VERSION 5.8 ;
BUSBITCHARS "[]" ;
DIVIDERCHAR "/" ;
UNITS
  DATABASE MICRONS 1000 ;
END UNITS
LAYER metal1
  TYPE ROUTING ;
  DIRECTION HORIZONTAL ;
  PITCH 0.1 ;
  WIDTH 0.1 ;
END metal1
MANUFACTURINGGRID 0.001 ;
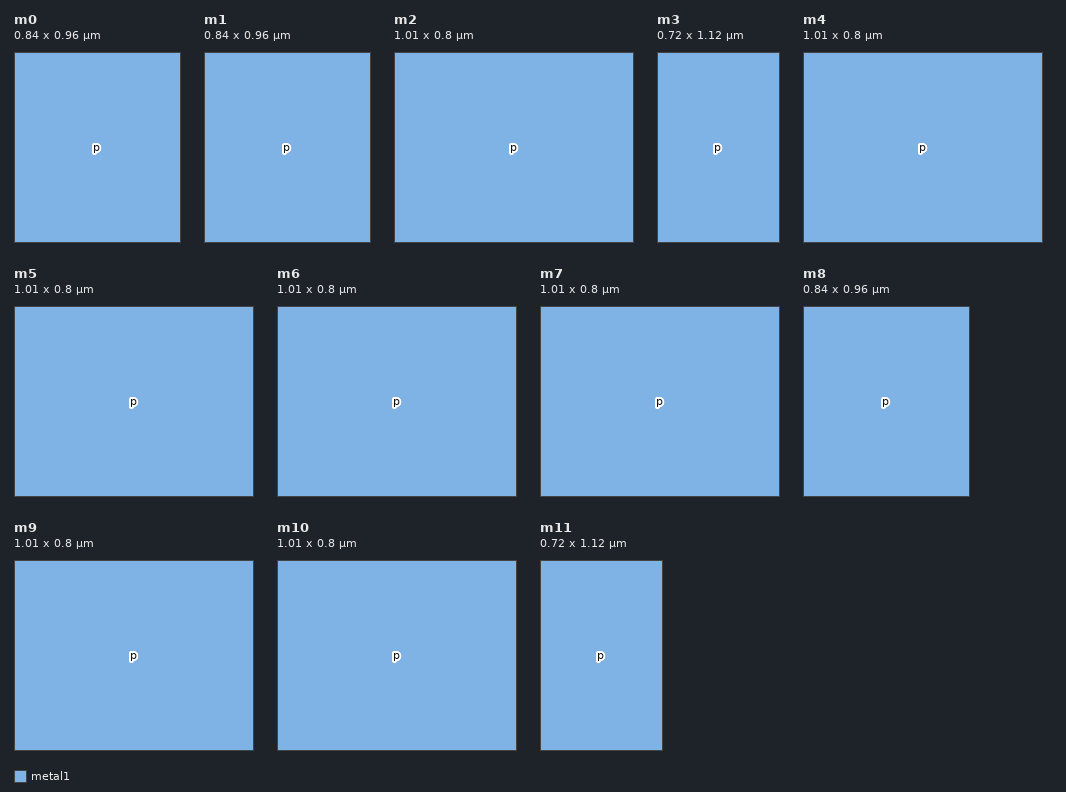
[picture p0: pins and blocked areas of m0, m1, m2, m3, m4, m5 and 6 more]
MACRO m0
  SIZE 0.840 BY 0.960 ;
  PIN p
    DIRECTION INOUT ;
    USE SIGNAL ;
    PORT
      LAYER metal1 ;
      RECT 0 0 0.840 0.960 ;
    END
  END p
END m0
MACRO m1
  SIZE 0.840 BY 0.960 ;
  PIN p
    DIRECTION INOUT ;
    USE SIGNAL ;
    PORT
      LAYER metal1 ;
      RECT 0 0 0.840 0.960 ;
    END
  END p
END m1
MACRO m2
  SIZE 1.010 BY 0.800 ;
  PIN p
    DIRECTION INOUT ;
    USE SIGNAL ;
    PORT
      LAYER metal1 ;
      RECT 0 0 1.010 0.800 ;
    END
  END p
END m2
MACRO m3
  SIZE 0.720 BY 1.120 ;
  PIN p
    DIRECTION INOUT ;
    USE SIGNAL ;
    PORT
      LAYER metal1 ;
      RECT 0 0 0.720 1.120 ;
    END
  END p
END m3
MACRO m4
  SIZE 1.010 BY 0.800 ;
  PIN p
    DIRECTION INOUT ;
    USE SIGNAL ;
    PORT
      LAYER metal1 ;
      RECT 0 0 1.010 0.800 ;
    END
  END p
END m4
MACRO m5
  SIZE 1.010 BY 0.800 ;
  PIN p
    DIRECTION INOUT ;
    USE SIGNAL ;
    PORT
      LAYER metal1 ;
      RECT 0 0 1.010 0.800 ;
    END
  END p
END m5
MACRO m6
  SIZE 1.010 BY 0.800 ;
  PIN p
    DIRECTION INOUT ;
    USE SIGNAL ;
    PORT
      LAYER metal1 ;
      RECT 0 0 1.010 0.800 ;
    END
  END p
END m6
MACRO m7
  SIZE 1.010 BY 0.800 ;
  PIN p
    DIRECTION INOUT ;
    USE SIGNAL ;
    PORT
      LAYER metal1 ;
      RECT 0 0 1.010 0.800 ;
    END
  END p
END m7
MACRO m8
  SIZE 0.840 BY 0.960 ;
  PIN p
    DIRECTION INOUT ;
    USE SIGNAL ;
    PORT
      LAYER metal1 ;
      RECT 0 0 0.840 0.960 ;
    END
  END p
END m8
MACRO m9
  SIZE 1.010 BY 0.800 ;
  PIN p
    DIRECTION INOUT ;
    USE SIGNAL ;
    PORT
      LAYER metal1 ;
      RECT 0 0 1.010 0.800 ;
    END
  END p
END m9
MACRO m10
  SIZE 1.010 BY 0.800 ;
  PIN p
    DIRECTION INOUT ;
    USE SIGNAL ;
    PORT
      LAYER metal1 ;
      RECT 0 0 1.010 0.800 ;
    END
  END p
END m10
MACRO m11
  SIZE 0.720 BY 1.120 ;
  PIN p
    DIRECTION INOUT ;
    USE SIGNAL ;
    PORT
      LAYER metal1 ;
      RECT 0 0 0.720 1.120 ;
    END
  END p
END m11
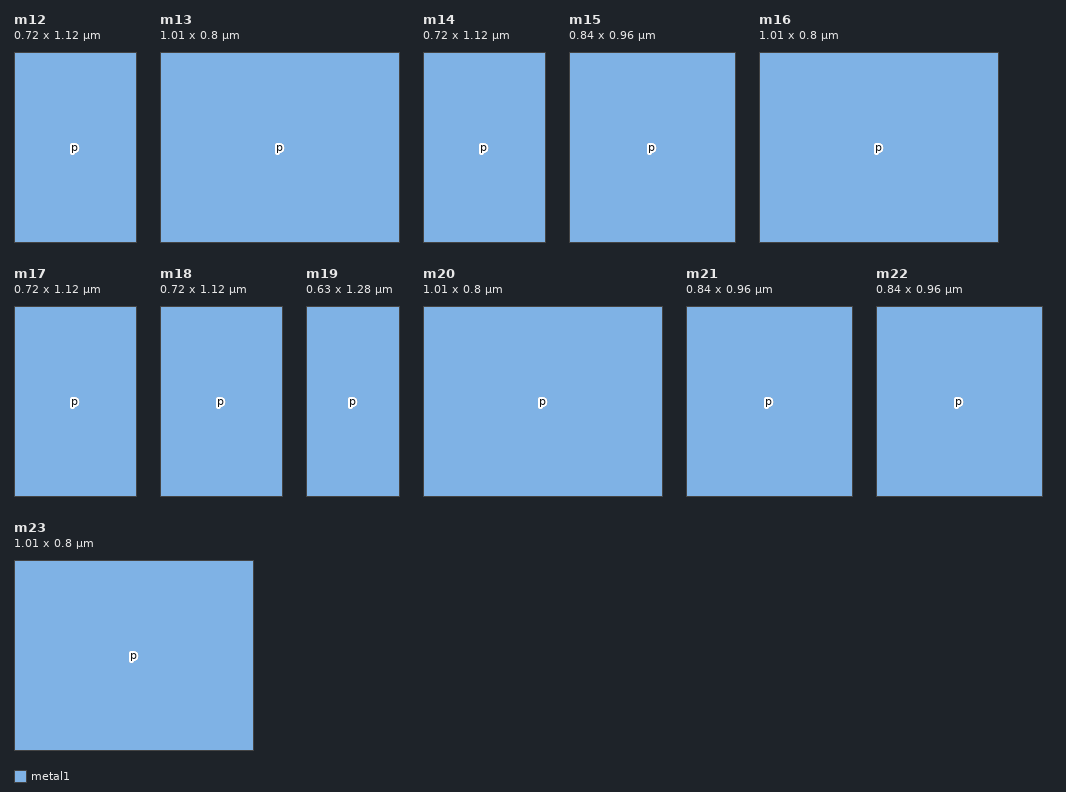
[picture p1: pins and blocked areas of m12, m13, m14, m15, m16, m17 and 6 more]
MACRO m12
  SIZE 0.720 BY 1.120 ;
  PIN p
    DIRECTION INOUT ;
    USE SIGNAL ;
    PORT
      LAYER metal1 ;
      RECT 0 0 0.720 1.120 ;
    END
  END p
END m12
MACRO m13
  SIZE 1.010 BY 0.800 ;
  PIN p
    DIRECTION INOUT ;
    USE SIGNAL ;
    PORT
      LAYER metal1 ;
      RECT 0 0 1.010 0.800 ;
    END
  END p
END m13
MACRO m14
  SIZE 0.720 BY 1.120 ;
  PIN p
    DIRECTION INOUT ;
    USE SIGNAL ;
    PORT
      LAYER metal1 ;
      RECT 0 0 0.720 1.120 ;
    END
  END p
END m14
MACRO m15
  SIZE 0.840 BY 0.960 ;
  PIN p
    DIRECTION INOUT ;
    USE SIGNAL ;
    PORT
      LAYER metal1 ;
      RECT 0 0 0.840 0.960 ;
    END
  END p
END m15
MACRO m16
  SIZE 1.010 BY 0.800 ;
  PIN p
    DIRECTION INOUT ;
    USE SIGNAL ;
    PORT
      LAYER metal1 ;
      RECT 0 0 1.010 0.800 ;
    END
  END p
END m16
MACRO m17
  SIZE 0.720 BY 1.120 ;
  PIN p
    DIRECTION INOUT ;
    USE SIGNAL ;
    PORT
      LAYER metal1 ;
      RECT 0 0 0.720 1.120 ;
    END
  END p
END m17
MACRO m18
  SIZE 0.720 BY 1.120 ;
  PIN p
    DIRECTION INOUT ;
    USE SIGNAL ;
    PORT
      LAYER metal1 ;
      RECT 0 0 0.720 1.120 ;
    END
  END p
END m18
MACRO m19
  SIZE 0.630 BY 1.280 ;
  PIN p
    DIRECTION INOUT ;
    USE SIGNAL ;
    PORT
      LAYER metal1 ;
      RECT 0 0 0.630 1.280 ;
    END
  END p
END m19
MACRO m20
  SIZE 1.010 BY 0.800 ;
  PIN p
    DIRECTION INOUT ;
    USE SIGNAL ;
    PORT
      LAYER metal1 ;
      RECT 0 0 1.010 0.800 ;
    END
  END p
END m20
MACRO m21
  SIZE 0.840 BY 0.960 ;
  PIN p
    DIRECTION INOUT ;
    USE SIGNAL ;
    PORT
      LAYER metal1 ;
      RECT 0 0 0.840 0.960 ;
    END
  END p
END m21
MACRO m22
  SIZE 0.840 BY 0.960 ;
  PIN p
    DIRECTION INOUT ;
    USE SIGNAL ;
    PORT
      LAYER metal1 ;
      RECT 0 0 0.840 0.960 ;
    END
  END p
END m22
MACRO m23
  SIZE 1.010 BY 0.800 ;
  PIN p
    DIRECTION INOUT ;
    USE SIGNAL ;
    PORT
      LAYER metal1 ;
      RECT 0 0 1.010 0.800 ;
    END
  END p
END m23
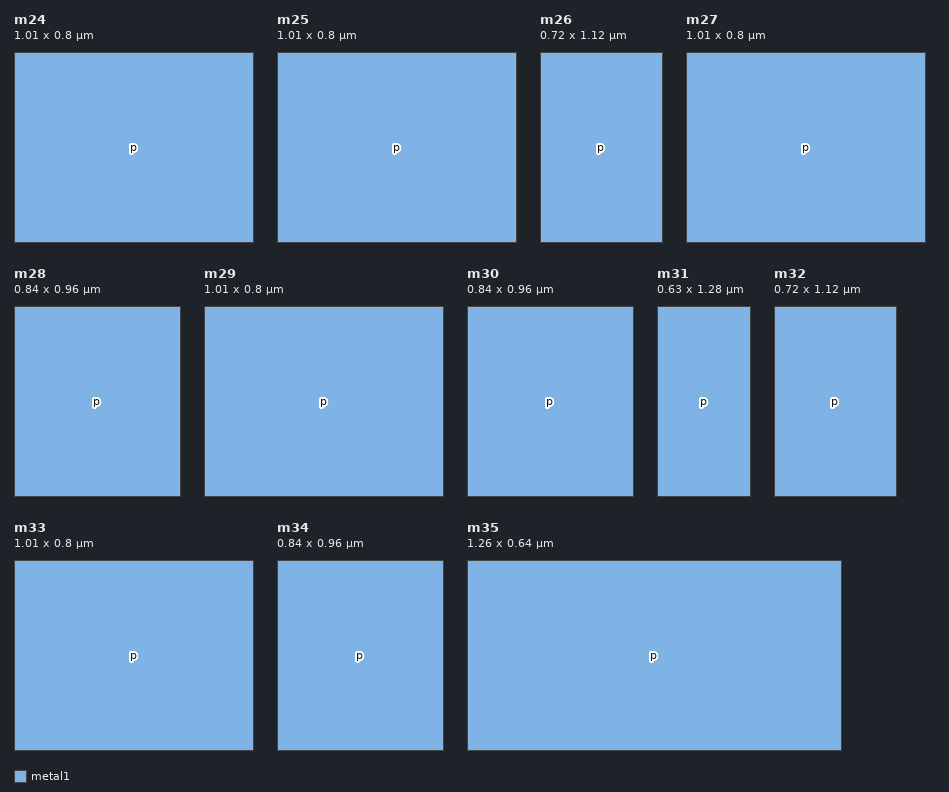
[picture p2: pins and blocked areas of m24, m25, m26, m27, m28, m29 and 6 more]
MACRO m24
  SIZE 1.010 BY 0.800 ;
  PIN p
    DIRECTION INOUT ;
    USE SIGNAL ;
    PORT
      LAYER metal1 ;
      RECT 0 0 1.010 0.800 ;
    END
  END p
END m24
MACRO m25
  SIZE 1.010 BY 0.800 ;
  PIN p
    DIRECTION INOUT ;
    USE SIGNAL ;
    PORT
      LAYER metal1 ;
      RECT 0 0 1.010 0.800 ;
    END
  END p
END m25
MACRO m26
  SIZE 0.720 BY 1.120 ;
  PIN p
    DIRECTION INOUT ;
    USE SIGNAL ;
    PORT
      LAYER metal1 ;
      RECT 0 0 0.720 1.120 ;
    END
  END p
END m26
MACRO m27
  SIZE 1.010 BY 0.800 ;
  PIN p
    DIRECTION INOUT ;
    USE SIGNAL ;
    PORT
      LAYER metal1 ;
      RECT 0 0 1.010 0.800 ;
    END
  END p
END m27
MACRO m28
  SIZE 0.840 BY 0.960 ;
  PIN p
    DIRECTION INOUT ;
    USE SIGNAL ;
    PORT
      LAYER metal1 ;
      RECT 0 0 0.840 0.960 ;
    END
  END p
END m28
MACRO m29
  SIZE 1.010 BY 0.800 ;
  PIN p
    DIRECTION INOUT ;
    USE SIGNAL ;
    PORT
      LAYER metal1 ;
      RECT 0 0 1.010 0.800 ;
    END
  END p
END m29
MACRO m30
  SIZE 0.840 BY 0.960 ;
  PIN p
    DIRECTION INOUT ;
    USE SIGNAL ;
    PORT
      LAYER metal1 ;
      RECT 0 0 0.840 0.960 ;
    END
  END p
END m30
MACRO m31
  SIZE 0.630 BY 1.280 ;
  PIN p
    DIRECTION INOUT ;
    USE SIGNAL ;
    PORT
      LAYER metal1 ;
      RECT 0 0 0.630 1.280 ;
    END
  END p
END m31
MACRO m32
  SIZE 0.720 BY 1.120 ;
  PIN p
    DIRECTION INOUT ;
    USE SIGNAL ;
    PORT
      LAYER metal1 ;
      RECT 0 0 0.720 1.120 ;
    END
  END p
END m32
MACRO m33
  SIZE 1.010 BY 0.800 ;
  PIN p
    DIRECTION INOUT ;
    USE SIGNAL ;
    PORT
      LAYER metal1 ;
      RECT 0 0 1.010 0.800 ;
    END
  END p
END m33
MACRO m34
  SIZE 0.840 BY 0.960 ;
  PIN p
    DIRECTION INOUT ;
    USE SIGNAL ;
    PORT
      LAYER metal1 ;
      RECT 0 0 0.840 0.960 ;
    END
  END p
END m34
MACRO m35
  SIZE 1.260 BY 0.640 ;
  PIN p
    DIRECTION INOUT ;
    USE SIGNAL ;
    PORT
      LAYER metal1 ;
      RECT 0 0 1.260 0.640 ;
    END
  END p
END m35
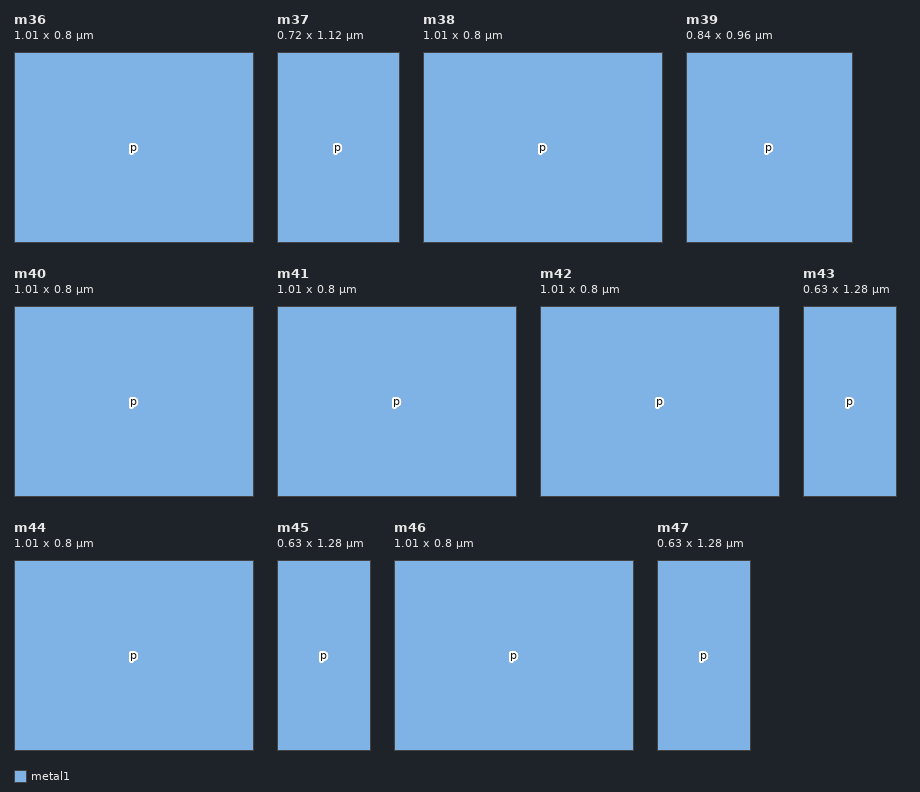
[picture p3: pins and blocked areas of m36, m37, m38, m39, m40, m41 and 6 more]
MACRO m36
  SIZE 1.010 BY 0.800 ;
  PIN p
    DIRECTION INOUT ;
    USE SIGNAL ;
    PORT
      LAYER metal1 ;
      RECT 0 0 1.010 0.800 ;
    END
  END p
END m36
MACRO m37
  SIZE 0.720 BY 1.120 ;
  PIN p
    DIRECTION INOUT ;
    USE SIGNAL ;
    PORT
      LAYER metal1 ;
      RECT 0 0 0.720 1.120 ;
    END
  END p
END m37
MACRO m38
  SIZE 1.010 BY 0.800 ;
  PIN p
    DIRECTION INOUT ;
    USE SIGNAL ;
    PORT
      LAYER metal1 ;
      RECT 0 0 1.010 0.800 ;
    END
  END p
END m38
MACRO m39
  SIZE 0.840 BY 0.960 ;
  PIN p
    DIRECTION INOUT ;
    USE SIGNAL ;
    PORT
      LAYER metal1 ;
      RECT 0 0 0.840 0.960 ;
    END
  END p
END m39
MACRO m40
  SIZE 1.010 BY 0.800 ;
  PIN p
    DIRECTION INOUT ;
    USE SIGNAL ;
    PORT
      LAYER metal1 ;
      RECT 0 0 1.010 0.800 ;
    END
  END p
END m40
MACRO m41
  SIZE 1.010 BY 0.800 ;
  PIN p
    DIRECTION INOUT ;
    USE SIGNAL ;
    PORT
      LAYER metal1 ;
      RECT 0 0 1.010 0.800 ;
    END
  END p
END m41
MACRO m42
  SIZE 1.010 BY 0.800 ;
  PIN p
    DIRECTION INOUT ;
    USE SIGNAL ;
    PORT
      LAYER metal1 ;
      RECT 0 0 1.010 0.800 ;
    END
  END p
END m42
MACRO m43
  SIZE 0.630 BY 1.280 ;
  PIN p
    DIRECTION INOUT ;
    USE SIGNAL ;
    PORT
      LAYER metal1 ;
      RECT 0 0 0.630 1.280 ;
    END
  END p
END m43
MACRO m44
  SIZE 1.010 BY 0.800 ;
  PIN p
    DIRECTION INOUT ;
    USE SIGNAL ;
    PORT
      LAYER metal1 ;
      RECT 0 0 1.010 0.800 ;
    END
  END p
END m44
MACRO m45
  SIZE 0.630 BY 1.280 ;
  PIN p
    DIRECTION INOUT ;
    USE SIGNAL ;
    PORT
      LAYER metal1 ;
      RECT 0 0 0.630 1.280 ;
    END
  END p
END m45
MACRO m46
  SIZE 1.010 BY 0.800 ;
  PIN p
    DIRECTION INOUT ;
    USE SIGNAL ;
    PORT
      LAYER metal1 ;
      RECT 0 0 1.010 0.800 ;
    END
  END p
END m46
MACRO m47
  SIZE 0.630 BY 1.280 ;
  PIN p
    DIRECTION INOUT ;
    USE SIGNAL ;
    PORT
      LAYER metal1 ;
      RECT 0 0 0.630 1.280 ;
    END
  END p
END m47
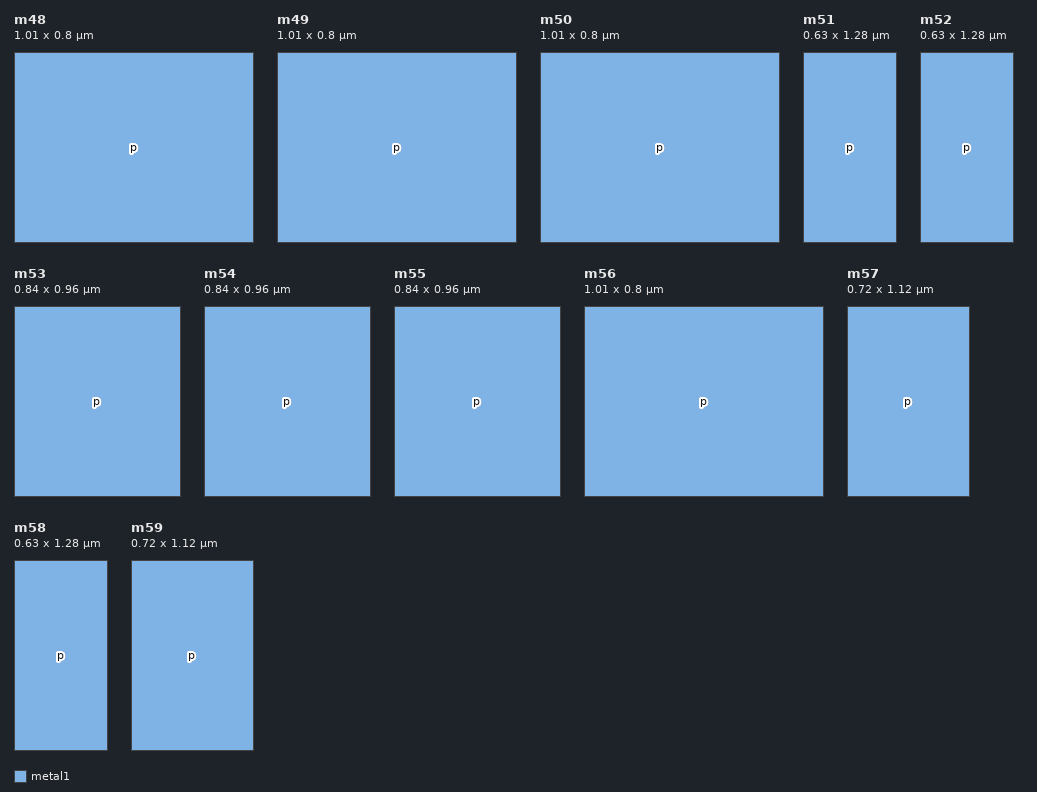
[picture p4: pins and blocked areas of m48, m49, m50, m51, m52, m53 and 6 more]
MACRO m48
  SIZE 1.010 BY 0.800 ;
  PIN p
    DIRECTION INOUT ;
    USE SIGNAL ;
    PORT
      LAYER metal1 ;
      RECT 0 0 1.010 0.800 ;
    END
  END p
END m48
MACRO m49
  SIZE 1.010 BY 0.800 ;
  PIN p
    DIRECTION INOUT ;
    USE SIGNAL ;
    PORT
      LAYER metal1 ;
      RECT 0 0 1.010 0.800 ;
    END
  END p
END m49
MACRO m50
  SIZE 1.010 BY 0.800 ;
  PIN p
    DIRECTION INOUT ;
    USE SIGNAL ;
    PORT
      LAYER metal1 ;
      RECT 0 0 1.010 0.800 ;
    END
  END p
END m50
MACRO m51
  SIZE 0.630 BY 1.280 ;
  PIN p
    DIRECTION INOUT ;
    USE SIGNAL ;
    PORT
      LAYER metal1 ;
      RECT 0 0 0.630 1.280 ;
    END
  END p
END m51
MACRO m52
  SIZE 0.630 BY 1.280 ;
  PIN p
    DIRECTION INOUT ;
    USE SIGNAL ;
    PORT
      LAYER metal1 ;
      RECT 0 0 0.630 1.280 ;
    END
  END p
END m52
MACRO m53
  SIZE 0.840 BY 0.960 ;
  PIN p
    DIRECTION INOUT ;
    USE SIGNAL ;
    PORT
      LAYER metal1 ;
      RECT 0 0 0.840 0.960 ;
    END
  END p
END m53
MACRO m54
  SIZE 0.840 BY 0.960 ;
  PIN p
    DIRECTION INOUT ;
    USE SIGNAL ;
    PORT
      LAYER metal1 ;
      RECT 0 0 0.840 0.960 ;
    END
  END p
END m54
MACRO m55
  SIZE 0.840 BY 0.960 ;
  PIN p
    DIRECTION INOUT ;
    USE SIGNAL ;
    PORT
      LAYER metal1 ;
      RECT 0 0 0.840 0.960 ;
    END
  END p
END m55
MACRO m56
  SIZE 1.010 BY 0.800 ;
  PIN p
    DIRECTION INOUT ;
    USE SIGNAL ;
    PORT
      LAYER metal1 ;
      RECT 0 0 1.010 0.800 ;
    END
  END p
END m56
MACRO m57
  SIZE 0.720 BY 1.120 ;
  PIN p
    DIRECTION INOUT ;
    USE SIGNAL ;
    PORT
      LAYER metal1 ;
      RECT 0 0 0.720 1.120 ;
    END
  END p
END m57
MACRO m58
  SIZE 0.630 BY 1.280 ;
  PIN p
    DIRECTION INOUT ;
    USE SIGNAL ;
    PORT
      LAYER metal1 ;
      RECT 0 0 0.630 1.280 ;
    END
  END p
END m58
MACRO m59
  SIZE 0.720 BY 1.120 ;
  PIN p
    DIRECTION INOUT ;
    USE SIGNAL ;
    PORT
      LAYER metal1 ;
      RECT 0 0 0.720 1.120 ;
    END
  END p
END m59
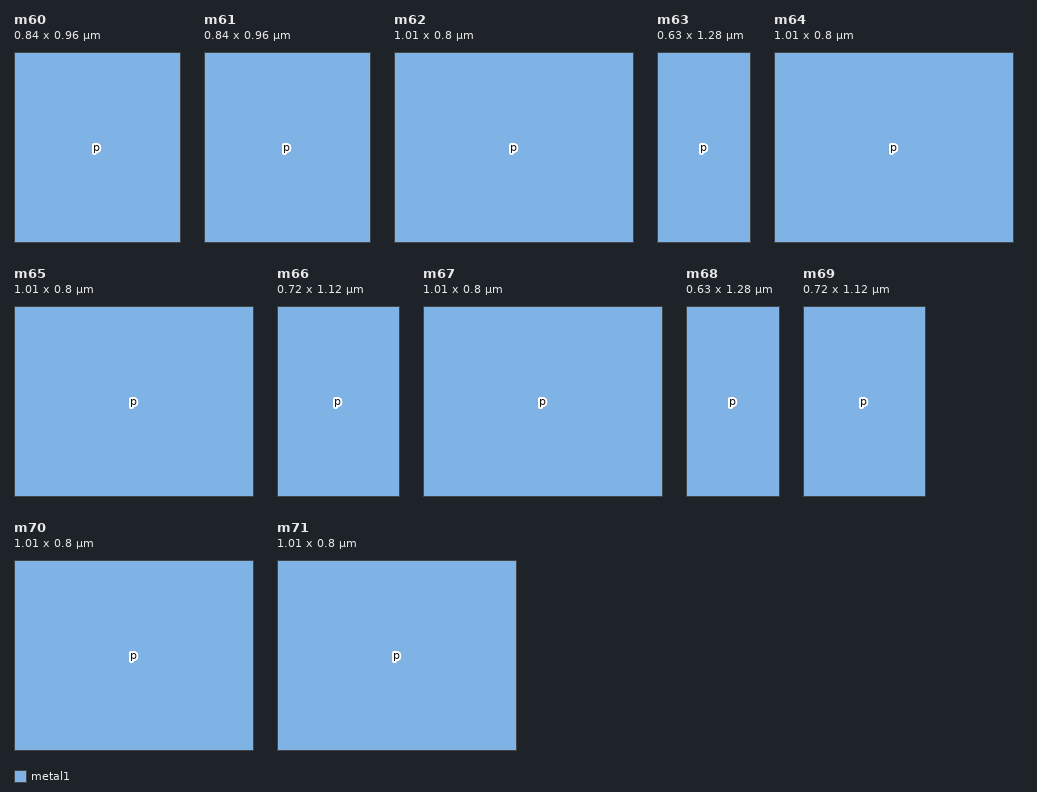
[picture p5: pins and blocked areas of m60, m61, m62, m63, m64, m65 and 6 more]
MACRO m60
  SIZE 0.840 BY 0.960 ;
  PIN p
    DIRECTION INOUT ;
    USE SIGNAL ;
    PORT
      LAYER metal1 ;
      RECT 0 0 0.840 0.960 ;
    END
  END p
END m60
MACRO m61
  SIZE 0.840 BY 0.960 ;
  PIN p
    DIRECTION INOUT ;
    USE SIGNAL ;
    PORT
      LAYER metal1 ;
      RECT 0 0 0.840 0.960 ;
    END
  END p
END m61
MACRO m62
  SIZE 1.010 BY 0.800 ;
  PIN p
    DIRECTION INOUT ;
    USE SIGNAL ;
    PORT
      LAYER metal1 ;
      RECT 0 0 1.010 0.800 ;
    END
  END p
END m62
MACRO m63
  SIZE 0.630 BY 1.280 ;
  PIN p
    DIRECTION INOUT ;
    USE SIGNAL ;
    PORT
      LAYER metal1 ;
      RECT 0 0 0.630 1.280 ;
    END
  END p
END m63
MACRO m64
  SIZE 1.010 BY 0.800 ;
  PIN p
    DIRECTION INOUT ;
    USE SIGNAL ;
    PORT
      LAYER metal1 ;
      RECT 0 0 1.010 0.800 ;
    END
  END p
END m64
MACRO m65
  SIZE 1.010 BY 0.800 ;
  PIN p
    DIRECTION INOUT ;
    USE SIGNAL ;
    PORT
      LAYER metal1 ;
      RECT 0 0 1.010 0.800 ;
    END
  END p
END m65
MACRO m66
  SIZE 0.720 BY 1.120 ;
  PIN p
    DIRECTION INOUT ;
    USE SIGNAL ;
    PORT
      LAYER metal1 ;
      RECT 0 0 0.720 1.120 ;
    END
  END p
END m66
MACRO m67
  SIZE 1.010 BY 0.800 ;
  PIN p
    DIRECTION INOUT ;
    USE SIGNAL ;
    PORT
      LAYER metal1 ;
      RECT 0 0 1.010 0.800 ;
    END
  END p
END m67
MACRO m68
  SIZE 0.630 BY 1.280 ;
  PIN p
    DIRECTION INOUT ;
    USE SIGNAL ;
    PORT
      LAYER metal1 ;
      RECT 0 0 0.630 1.280 ;
    END
  END p
END m68
MACRO m69
  SIZE 0.720 BY 1.120 ;
  PIN p
    DIRECTION INOUT ;
    USE SIGNAL ;
    PORT
      LAYER metal1 ;
      RECT 0 0 0.720 1.120 ;
    END
  END p
END m69
MACRO m70
  SIZE 1.010 BY 0.800 ;
  PIN p
    DIRECTION INOUT ;
    USE SIGNAL ;
    PORT
      LAYER metal1 ;
      RECT 0 0 1.010 0.800 ;
    END
  END p
END m70
MACRO m71
  SIZE 1.010 BY 0.800 ;
  PIN p
    DIRECTION INOUT ;
    USE SIGNAL ;
    PORT
      LAYER metal1 ;
      RECT 0 0 1.010 0.800 ;
    END
  END p
END m71
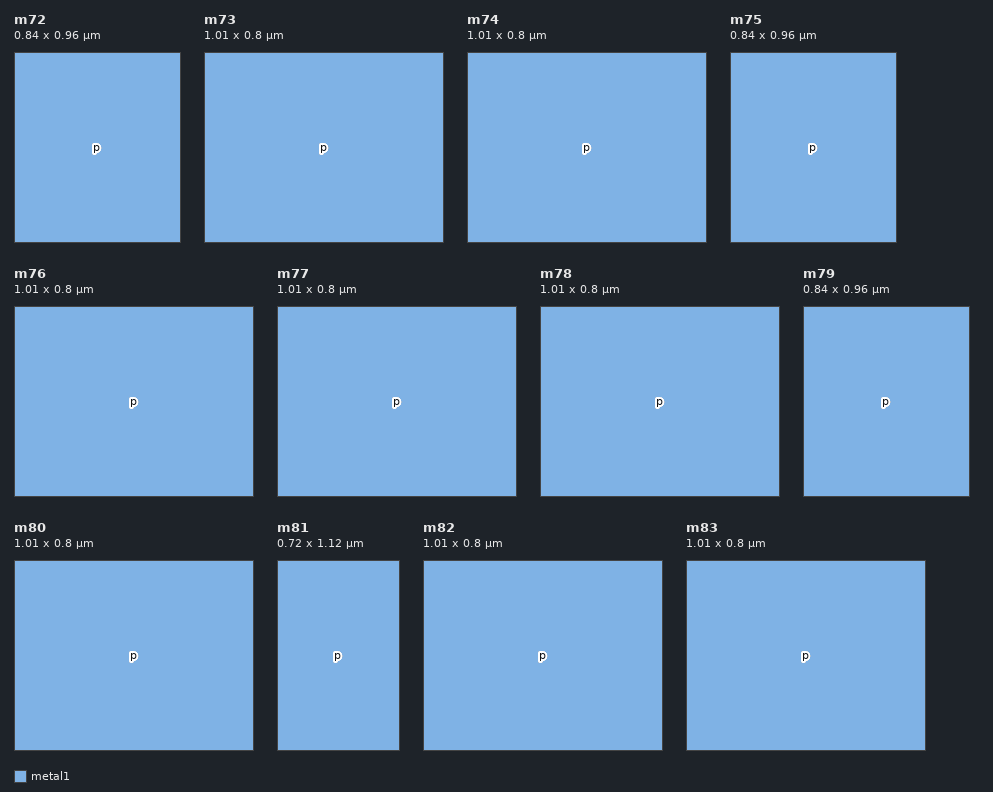
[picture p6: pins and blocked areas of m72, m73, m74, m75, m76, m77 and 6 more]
MACRO m72
  SIZE 0.840 BY 0.960 ;
  PIN p
    DIRECTION INOUT ;
    USE SIGNAL ;
    PORT
      LAYER metal1 ;
      RECT 0 0 0.840 0.960 ;
    END
  END p
END m72
MACRO m73
  SIZE 1.010 BY 0.800 ;
  PIN p
    DIRECTION INOUT ;
    USE SIGNAL ;
    PORT
      LAYER metal1 ;
      RECT 0 0 1.010 0.800 ;
    END
  END p
END m73
MACRO m74
  SIZE 1.010 BY 0.800 ;
  PIN p
    DIRECTION INOUT ;
    USE SIGNAL ;
    PORT
      LAYER metal1 ;
      RECT 0 0 1.010 0.800 ;
    END
  END p
END m74
MACRO m75
  SIZE 0.840 BY 0.960 ;
  PIN p
    DIRECTION INOUT ;
    USE SIGNAL ;
    PORT
      LAYER metal1 ;
      RECT 0 0 0.840 0.960 ;
    END
  END p
END m75
MACRO m76
  SIZE 1.010 BY 0.800 ;
  PIN p
    DIRECTION INOUT ;
    USE SIGNAL ;
    PORT
      LAYER metal1 ;
      RECT 0 0 1.010 0.800 ;
    END
  END p
END m76
MACRO m77
  SIZE 1.010 BY 0.800 ;
  PIN p
    DIRECTION INOUT ;
    USE SIGNAL ;
    PORT
      LAYER metal1 ;
      RECT 0 0 1.010 0.800 ;
    END
  END p
END m77
MACRO m78
  SIZE 1.010 BY 0.800 ;
  PIN p
    DIRECTION INOUT ;
    USE SIGNAL ;
    PORT
      LAYER metal1 ;
      RECT 0 0 1.010 0.800 ;
    END
  END p
END m78
MACRO m79
  SIZE 0.840 BY 0.960 ;
  PIN p
    DIRECTION INOUT ;
    USE SIGNAL ;
    PORT
      LAYER metal1 ;
      RECT 0 0 0.840 0.960 ;
    END
  END p
END m79
MACRO m80
  SIZE 1.010 BY 0.800 ;
  PIN p
    DIRECTION INOUT ;
    USE SIGNAL ;
    PORT
      LAYER metal1 ;
      RECT 0 0 1.010 0.800 ;
    END
  END p
END m80
MACRO m81
  SIZE 0.720 BY 1.120 ;
  PIN p
    DIRECTION INOUT ;
    USE SIGNAL ;
    PORT
      LAYER metal1 ;
      RECT 0 0 0.720 1.120 ;
    END
  END p
END m81
MACRO m82
  SIZE 1.010 BY 0.800 ;
  PIN p
    DIRECTION INOUT ;
    USE SIGNAL ;
    PORT
      LAYER metal1 ;
      RECT 0 0 1.010 0.800 ;
    END
  END p
END m82
MACRO m83
  SIZE 1.010 BY 0.800 ;
  PIN p
    DIRECTION INOUT ;
    USE SIGNAL ;
    PORT
      LAYER metal1 ;
      RECT 0 0 1.010 0.800 ;
    END
  END p
END m83
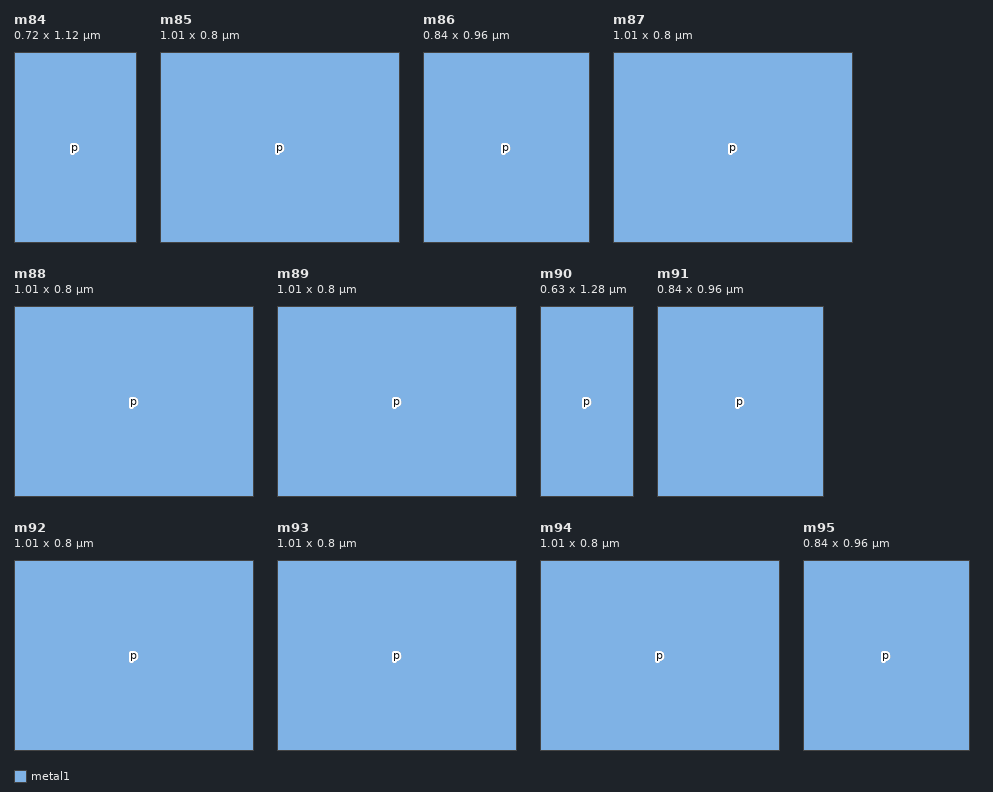
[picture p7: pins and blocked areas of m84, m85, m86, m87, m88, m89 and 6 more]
MACRO m84
  SIZE 0.720 BY 1.120 ;
  PIN p
    DIRECTION INOUT ;
    USE SIGNAL ;
    PORT
      LAYER metal1 ;
      RECT 0 0 0.720 1.120 ;
    END
  END p
END m84
MACRO m85
  SIZE 1.010 BY 0.800 ;
  PIN p
    DIRECTION INOUT ;
    USE SIGNAL ;
    PORT
      LAYER metal1 ;
      RECT 0 0 1.010 0.800 ;
    END
  END p
END m85
MACRO m86
  SIZE 0.840 BY 0.960 ;
  PIN p
    DIRECTION INOUT ;
    USE SIGNAL ;
    PORT
      LAYER metal1 ;
      RECT 0 0 0.840 0.960 ;
    END
  END p
END m86
MACRO m87
  SIZE 1.010 BY 0.800 ;
  PIN p
    DIRECTION INOUT ;
    USE SIGNAL ;
    PORT
      LAYER metal1 ;
      RECT 0 0 1.010 0.800 ;
    END
  END p
END m87
MACRO m88
  SIZE 1.010 BY 0.800 ;
  PIN p
    DIRECTION INOUT ;
    USE SIGNAL ;
    PORT
      LAYER metal1 ;
      RECT 0 0 1.010 0.800 ;
    END
  END p
END m88
MACRO m89
  SIZE 1.010 BY 0.800 ;
  PIN p
    DIRECTION INOUT ;
    USE SIGNAL ;
    PORT
      LAYER metal1 ;
      RECT 0 0 1.010 0.800 ;
    END
  END p
END m89
MACRO m90
  SIZE 0.630 BY 1.280 ;
  PIN p
    DIRECTION INOUT ;
    USE SIGNAL ;
    PORT
      LAYER metal1 ;
      RECT 0 0 0.630 1.280 ;
    END
  END p
END m90
MACRO m91
  SIZE 0.840 BY 0.960 ;
  PIN p
    DIRECTION INOUT ;
    USE SIGNAL ;
    PORT
      LAYER metal1 ;
      RECT 0 0 0.840 0.960 ;
    END
  END p
END m91
MACRO m92
  SIZE 1.010 BY 0.800 ;
  PIN p
    DIRECTION INOUT ;
    USE SIGNAL ;
    PORT
      LAYER metal1 ;
      RECT 0 0 1.010 0.800 ;
    END
  END p
END m92
MACRO m93
  SIZE 1.010 BY 0.800 ;
  PIN p
    DIRECTION INOUT ;
    USE SIGNAL ;
    PORT
      LAYER metal1 ;
      RECT 0 0 1.010 0.800 ;
    END
  END p
END m93
MACRO m94
  SIZE 1.010 BY 0.800 ;
  PIN p
    DIRECTION INOUT ;
    USE SIGNAL ;
    PORT
      LAYER metal1 ;
      RECT 0 0 1.010 0.800 ;
    END
  END p
END m94
MACRO m95
  SIZE 0.840 BY 0.960 ;
  PIN p
    DIRECTION INOUT ;
    USE SIGNAL ;
    PORT
      LAYER metal1 ;
      RECT 0 0 0.840 0.960 ;
    END
  END p
END m95
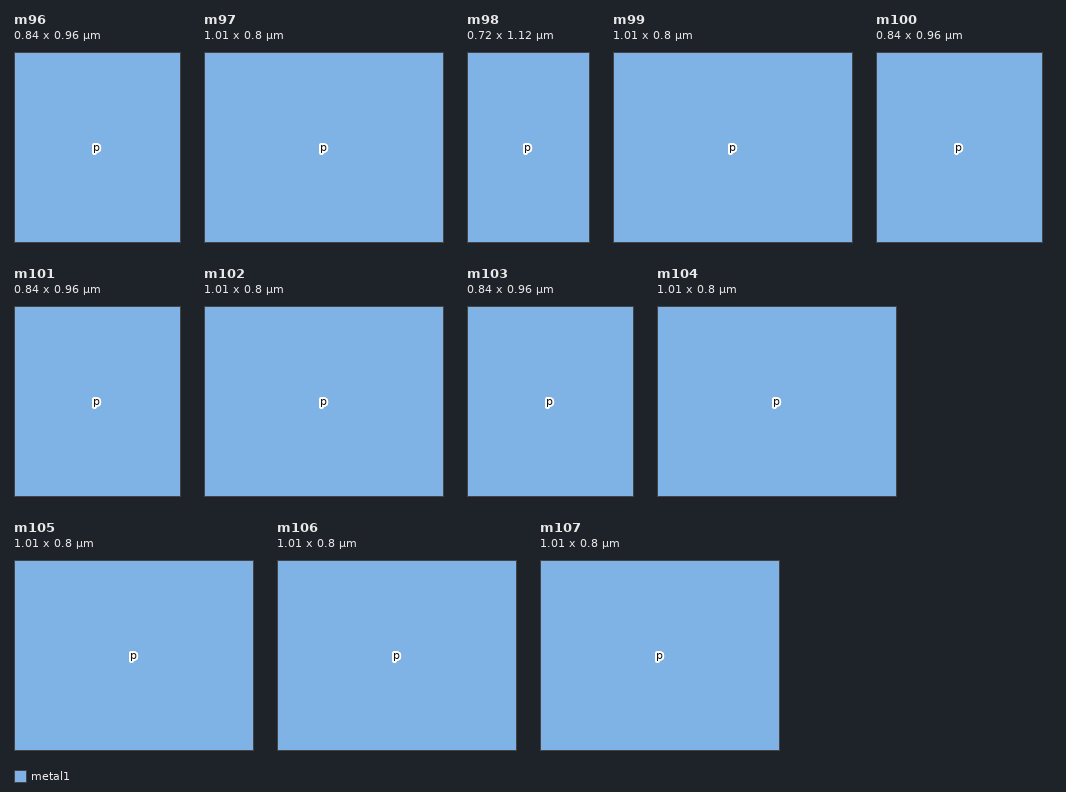
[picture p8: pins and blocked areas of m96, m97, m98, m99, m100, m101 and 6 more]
MACRO m96
  SIZE 0.840 BY 0.960 ;
  PIN p
    DIRECTION INOUT ;
    USE SIGNAL ;
    PORT
      LAYER metal1 ;
      RECT 0 0 0.840 0.960 ;
    END
  END p
END m96
MACRO m97
  SIZE 1.010 BY 0.800 ;
  PIN p
    DIRECTION INOUT ;
    USE SIGNAL ;
    PORT
      LAYER metal1 ;
      RECT 0 0 1.010 0.800 ;
    END
  END p
END m97
MACRO m98
  SIZE 0.720 BY 1.120 ;
  PIN p
    DIRECTION INOUT ;
    USE SIGNAL ;
    PORT
      LAYER metal1 ;
      RECT 0 0 0.720 1.120 ;
    END
  END p
END m98
MACRO m99
  SIZE 1.010 BY 0.800 ;
  PIN p
    DIRECTION INOUT ;
    USE SIGNAL ;
    PORT
      LAYER metal1 ;
      RECT 0 0 1.010 0.800 ;
    END
  END p
END m99
MACRO m100
  SIZE 0.840 BY 0.960 ;
  PIN p
    DIRECTION INOUT ;
    USE SIGNAL ;
    PORT
      LAYER metal1 ;
      RECT 0 0 0.840 0.960 ;
    END
  END p
END m100
MACRO m101
  SIZE 0.840 BY 0.960 ;
  PIN p
    DIRECTION INOUT ;
    USE SIGNAL ;
    PORT
      LAYER metal1 ;
      RECT 0 0 0.840 0.960 ;
    END
  END p
END m101
MACRO m102
  SIZE 1.010 BY 0.800 ;
  PIN p
    DIRECTION INOUT ;
    USE SIGNAL ;
    PORT
      LAYER metal1 ;
      RECT 0 0 1.010 0.800 ;
    END
  END p
END m102
MACRO m103
  SIZE 0.840 BY 0.960 ;
  PIN p
    DIRECTION INOUT ;
    USE SIGNAL ;
    PORT
      LAYER metal1 ;
      RECT 0 0 0.840 0.960 ;
    END
  END p
END m103
MACRO m104
  SIZE 1.010 BY 0.800 ;
  PIN p
    DIRECTION INOUT ;
    USE SIGNAL ;
    PORT
      LAYER metal1 ;
      RECT 0 0 1.010 0.800 ;
    END
  END p
END m104
MACRO m105
  SIZE 1.010 BY 0.800 ;
  PIN p
    DIRECTION INOUT ;
    USE SIGNAL ;
    PORT
      LAYER metal1 ;
      RECT 0 0 1.010 0.800 ;
    END
  END p
END m105
MACRO m106
  SIZE 1.010 BY 0.800 ;
  PIN p
    DIRECTION INOUT ;
    USE SIGNAL ;
    PORT
      LAYER metal1 ;
      RECT 0 0 1.010 0.800 ;
    END
  END p
END m106
MACRO m107
  SIZE 1.010 BY 0.800 ;
  PIN p
    DIRECTION INOUT ;
    USE SIGNAL ;
    PORT
      LAYER metal1 ;
      RECT 0 0 1.010 0.800 ;
    END
  END p
END m107
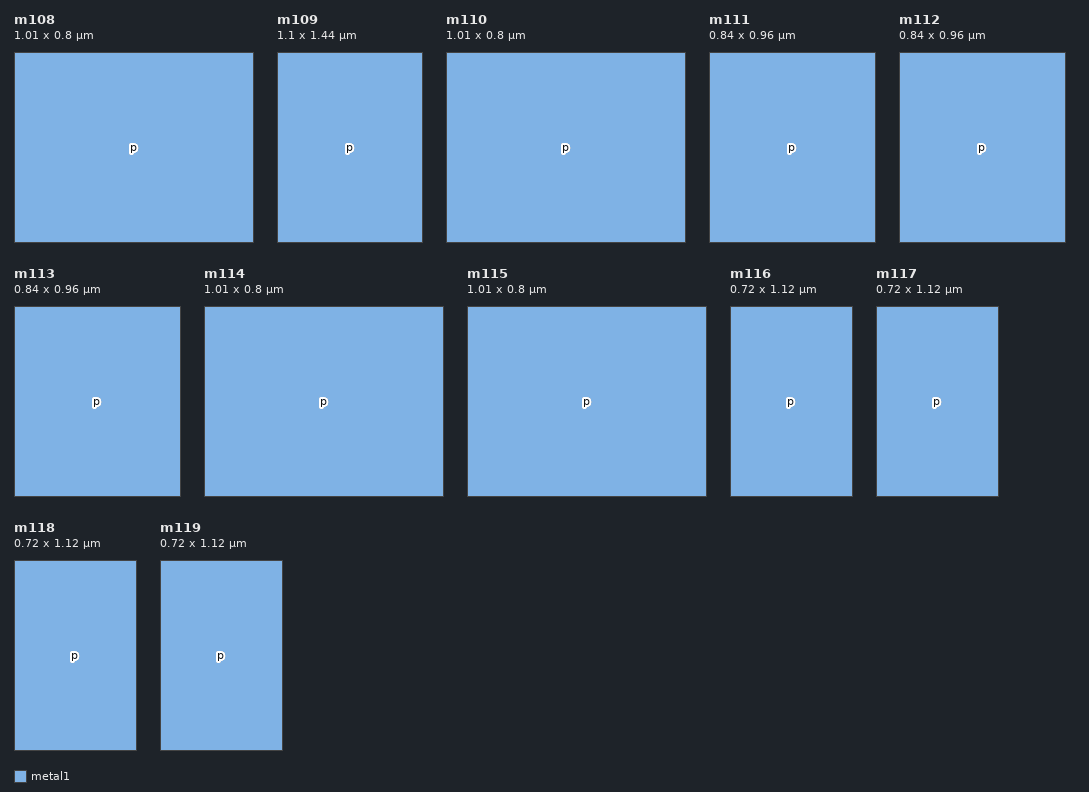
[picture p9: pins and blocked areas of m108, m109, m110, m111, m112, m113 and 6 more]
MACRO m108
  SIZE 1.010 BY 0.800 ;
  PIN p
    DIRECTION INOUT ;
    USE SIGNAL ;
    PORT
      LAYER metal1 ;
      RECT 0 0 1.010 0.800 ;
    END
  END p
END m108
MACRO m109
  SIZE 1.100 BY 1.440 ;
  PIN p
    DIRECTION INOUT ;
    USE SIGNAL ;
    PORT
      LAYER metal1 ;
      RECT 0 0 1.100 1.440 ;
    END
  END p
END m109
MACRO m110
  SIZE 1.010 BY 0.800 ;
  PIN p
    DIRECTION INOUT ;
    USE SIGNAL ;
    PORT
      LAYER metal1 ;
      RECT 0 0 1.010 0.800 ;
    END
  END p
END m110
MACRO m111
  SIZE 0.840 BY 0.960 ;
  PIN p
    DIRECTION INOUT ;
    USE SIGNAL ;
    PORT
      LAYER metal1 ;
      RECT 0 0 0.840 0.960 ;
    END
  END p
END m111
MACRO m112
  SIZE 0.840 BY 0.960 ;
  PIN p
    DIRECTION INOUT ;
    USE SIGNAL ;
    PORT
      LAYER metal1 ;
      RECT 0 0 0.840 0.960 ;
    END
  END p
END m112
MACRO m113
  SIZE 0.840 BY 0.960 ;
  PIN p
    DIRECTION INOUT ;
    USE SIGNAL ;
    PORT
      LAYER metal1 ;
      RECT 0 0 0.840 0.960 ;
    END
  END p
END m113
MACRO m114
  SIZE 1.010 BY 0.800 ;
  PIN p
    DIRECTION INOUT ;
    USE SIGNAL ;
    PORT
      LAYER metal1 ;
      RECT 0 0 1.010 0.800 ;
    END
  END p
END m114
MACRO m115
  SIZE 1.010 BY 0.800 ;
  PIN p
    DIRECTION INOUT ;
    USE SIGNAL ;
    PORT
      LAYER metal1 ;
      RECT 0 0 1.010 0.800 ;
    END
  END p
END m115
MACRO m116
  SIZE 0.720 BY 1.120 ;
  PIN p
    DIRECTION INOUT ;
    USE SIGNAL ;
    PORT
      LAYER metal1 ;
      RECT 0 0 0.720 1.120 ;
    END
  END p
END m116
MACRO m117
  SIZE 0.720 BY 1.120 ;
  PIN p
    DIRECTION INOUT ;
    USE SIGNAL ;
    PORT
      LAYER metal1 ;
      RECT 0 0 0.720 1.120 ;
    END
  END p
END m117
MACRO m118
  SIZE 0.720 BY 1.120 ;
  PIN p
    DIRECTION INOUT ;
    USE SIGNAL ;
    PORT
      LAYER metal1 ;
      RECT 0 0 0.720 1.120 ;
    END
  END p
END m118
MACRO m119
  SIZE 0.720 BY 1.120 ;
  PIN p
    DIRECTION INOUT ;
    USE SIGNAL ;
    PORT
      LAYER metal1 ;
      RECT 0 0 0.720 1.120 ;
    END
  END p
END m119
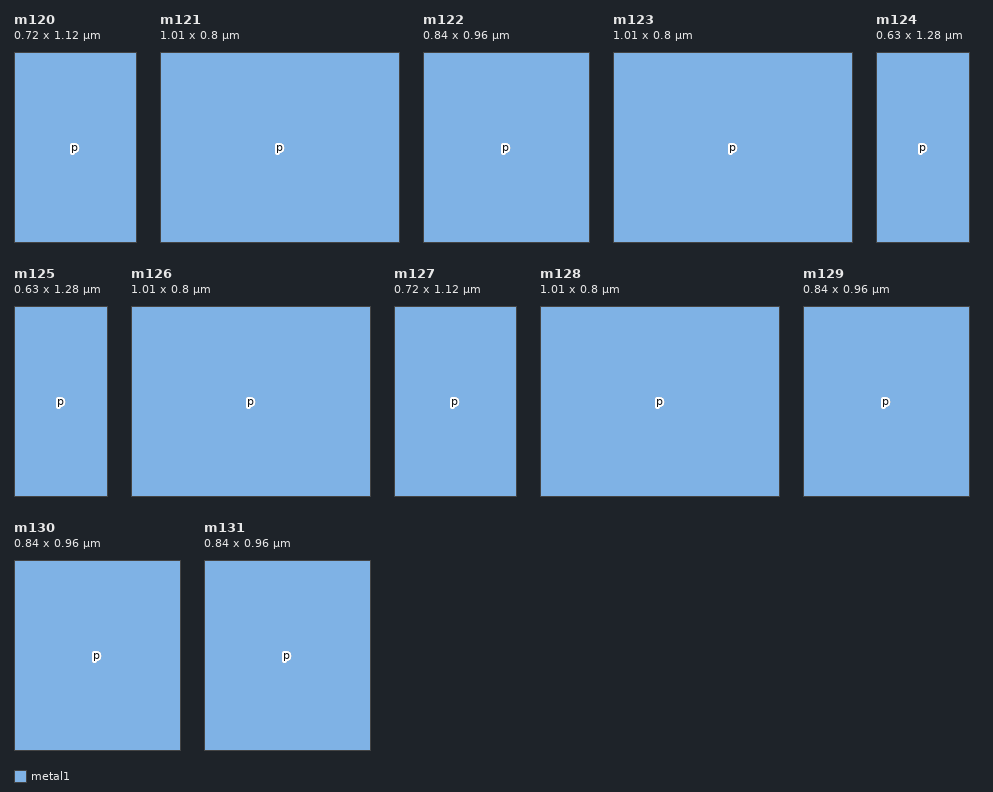
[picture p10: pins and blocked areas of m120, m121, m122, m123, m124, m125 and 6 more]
MACRO m120
  SIZE 0.720 BY 1.120 ;
  PIN p
    DIRECTION INOUT ;
    USE SIGNAL ;
    PORT
      LAYER metal1 ;
      RECT 0 0 0.720 1.120 ;
    END
  END p
END m120
MACRO m121
  SIZE 1.010 BY 0.800 ;
  PIN p
    DIRECTION INOUT ;
    USE SIGNAL ;
    PORT
      LAYER metal1 ;
      RECT 0 0 1.010 0.800 ;
    END
  END p
END m121
MACRO m122
  SIZE 0.840 BY 0.960 ;
  PIN p
    DIRECTION INOUT ;
    USE SIGNAL ;
    PORT
      LAYER metal1 ;
      RECT 0 0 0.840 0.960 ;
    END
  END p
END m122
MACRO m123
  SIZE 1.010 BY 0.800 ;
  PIN p
    DIRECTION INOUT ;
    USE SIGNAL ;
    PORT
      LAYER metal1 ;
      RECT 0 0 1.010 0.800 ;
    END
  END p
END m123
MACRO m124
  SIZE 0.630 BY 1.280 ;
  PIN p
    DIRECTION INOUT ;
    USE SIGNAL ;
    PORT
      LAYER metal1 ;
      RECT 0 0 0.630 1.280 ;
    END
  END p
END m124
MACRO m125
  SIZE 0.630 BY 1.280 ;
  PIN p
    DIRECTION INOUT ;
    USE SIGNAL ;
    PORT
      LAYER metal1 ;
      RECT 0 0 0.630 1.280 ;
    END
  END p
END m125
MACRO m126
  SIZE 1.010 BY 0.800 ;
  PIN p
    DIRECTION INOUT ;
    USE SIGNAL ;
    PORT
      LAYER metal1 ;
      RECT 0 0 1.010 0.800 ;
    END
  END p
END m126
MACRO m127
  SIZE 0.720 BY 1.120 ;
  PIN p
    DIRECTION INOUT ;
    USE SIGNAL ;
    PORT
      LAYER metal1 ;
      RECT 0 0 0.720 1.120 ;
    END
  END p
END m127
MACRO m128
  SIZE 1.010 BY 0.800 ;
  PIN p
    DIRECTION INOUT ;
    USE SIGNAL ;
    PORT
      LAYER metal1 ;
      RECT 0 0 1.010 0.800 ;
    END
  END p
END m128
MACRO m129
  SIZE 0.840 BY 0.960 ;
  PIN p
    DIRECTION INOUT ;
    USE SIGNAL ;
    PORT
      LAYER metal1 ;
      RECT 0 0 0.840 0.960 ;
    END
  END p
END m129
MACRO m130
  SIZE 0.840 BY 0.960 ;
  PIN p
    DIRECTION INOUT ;
    USE SIGNAL ;
    PORT
      LAYER metal1 ;
      RECT 0 0 0.840 0.960 ;
    END
  END p
END m130
MACRO m131
  SIZE 0.840 BY 0.960 ;
  PIN p
    DIRECTION INOUT ;
    USE SIGNAL ;
    PORT
      LAYER metal1 ;
      RECT 0 0 0.840 0.960 ;
    END
  END p
END m131
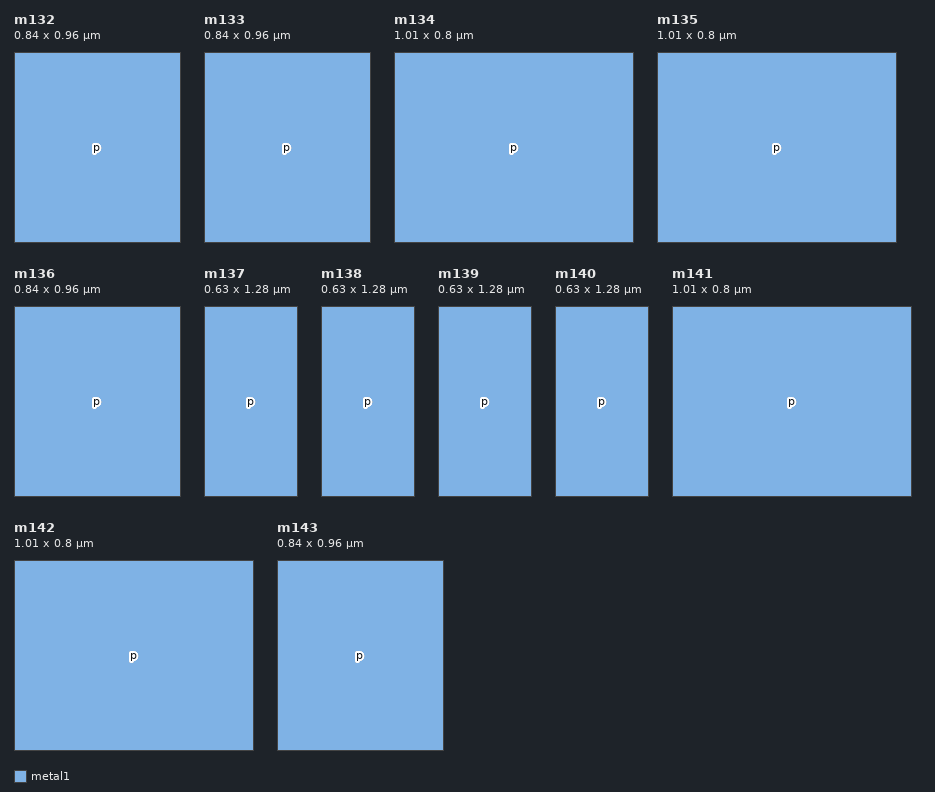
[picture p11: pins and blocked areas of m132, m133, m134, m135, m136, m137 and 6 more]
MACRO m132
  SIZE 0.840 BY 0.960 ;
  PIN p
    DIRECTION INOUT ;
    USE SIGNAL ;
    PORT
      LAYER metal1 ;
      RECT 0 0 0.840 0.960 ;
    END
  END p
END m132
MACRO m133
  SIZE 0.840 BY 0.960 ;
  PIN p
    DIRECTION INOUT ;
    USE SIGNAL ;
    PORT
      LAYER metal1 ;
      RECT 0 0 0.840 0.960 ;
    END
  END p
END m133
MACRO m134
  SIZE 1.010 BY 0.800 ;
  PIN p
    DIRECTION INOUT ;
    USE SIGNAL ;
    PORT
      LAYER metal1 ;
      RECT 0 0 1.010 0.800 ;
    END
  END p
END m134
MACRO m135
  SIZE 1.010 BY 0.800 ;
  PIN p
    DIRECTION INOUT ;
    USE SIGNAL ;
    PORT
      LAYER metal1 ;
      RECT 0 0 1.010 0.800 ;
    END
  END p
END m135
MACRO m136
  SIZE 0.840 BY 0.960 ;
  PIN p
    DIRECTION INOUT ;
    USE SIGNAL ;
    PORT
      LAYER metal1 ;
      RECT 0 0 0.840 0.960 ;
    END
  END p
END m136
MACRO m137
  SIZE 0.630 BY 1.280 ;
  PIN p
    DIRECTION INOUT ;
    USE SIGNAL ;
    PORT
      LAYER metal1 ;
      RECT 0 0 0.630 1.280 ;
    END
  END p
END m137
MACRO m138
  SIZE 0.630 BY 1.280 ;
  PIN p
    DIRECTION INOUT ;
    USE SIGNAL ;
    PORT
      LAYER metal1 ;
      RECT 0 0 0.630 1.280 ;
    END
  END p
END m138
MACRO m139
  SIZE 0.630 BY 1.280 ;
  PIN p
    DIRECTION INOUT ;
    USE SIGNAL ;
    PORT
      LAYER metal1 ;
      RECT 0 0 0.630 1.280 ;
    END
  END p
END m139
MACRO m140
  SIZE 0.630 BY 1.280 ;
  PIN p
    DIRECTION INOUT ;
    USE SIGNAL ;
    PORT
      LAYER metal1 ;
      RECT 0 0 0.630 1.280 ;
    END
  END p
END m140
MACRO m141
  SIZE 1.010 BY 0.800 ;
  PIN p
    DIRECTION INOUT ;
    USE SIGNAL ;
    PORT
      LAYER metal1 ;
      RECT 0 0 1.010 0.800 ;
    END
  END p
END m141
MACRO m142
  SIZE 1.010 BY 0.800 ;
  PIN p
    DIRECTION INOUT ;
    USE SIGNAL ;
    PORT
      LAYER metal1 ;
      RECT 0 0 1.010 0.800 ;
    END
  END p
END m142
MACRO m143
  SIZE 0.840 BY 0.960 ;
  PIN p
    DIRECTION INOUT ;
    USE SIGNAL ;
    PORT
      LAYER metal1 ;
      RECT 0 0 0.840 0.960 ;
    END
  END p
END m143
MACRO m144
  SIZE 0.840 BY 0.960 ;
  PIN p
    DIRECTION INOUT ;
    USE SIGNAL ;
    PORT
      LAYER metal1 ;
      RECT 0 0 0.840 0.960 ;
    END
  END p
END m144
MACRO m145
  SIZE 0.840 BY 0.960 ;
  PIN p
    DIRECTION INOUT ;
    USE SIGNAL ;
    PORT
      LAYER metal1 ;
      RECT 0 0 0.840 0.960 ;
    END
  END p
END m145
MACRO m146
  SIZE 0.720 BY 1.120 ;
  PIN p
    DIRECTION INOUT ;
    USE SIGNAL ;
    PORT
      LAYER metal1 ;
      RECT 0 0 0.720 1.120 ;
    END
  END p
END m146
MACRO m147
  SIZE 0.720 BY 1.120 ;
  PIN p
    DIRECTION INOUT ;
    USE SIGNAL ;
    PORT
      LAYER metal1 ;
      RECT 0 0 0.720 1.120 ;
    END
  END p
END m147
MACRO m148
  SIZE 0.720 BY 1.120 ;
  PIN p
    DIRECTION INOUT ;
    USE SIGNAL ;
    PORT
      LAYER metal1 ;
      RECT 0 0 0.720 1.120 ;
    END
  END p
END m148
MACRO m149
  SIZE 0.630 BY 1.280 ;
  PIN p
    DIRECTION INOUT ;
    USE SIGNAL ;
    PORT
      LAYER metal1 ;
      RECT 0 0 0.630 1.280 ;
    END
  END p
END m149
MACRO m150
  SIZE 1.010 BY 0.800 ;
  PIN p
    DIRECTION INOUT ;
    USE SIGNAL ;
    PORT
      LAYER metal1 ;
      RECT 0 0 1.010 0.800 ;
    END
  END p
END m150
MACRO m151
  SIZE 1.440 BY 1.120 ;
  PIN p
    DIRECTION INOUT ;
    USE SIGNAL ;
    PORT
      LAYER metal1 ;
      RECT 0 0 1.440 1.120 ;
    END
  END p
END m151
MACRO m152
  SIZE 0.840 BY 0.960 ;
  PIN p
    DIRECTION INOUT ;
    USE SIGNAL ;
    PORT
      LAYER metal1 ;
      RECT 0 0 0.840 0.960 ;
    END
  END p
END m152
MACRO m153
  SIZE 0.720 BY 1.120 ;
  PIN p
    DIRECTION INOUT ;
    USE SIGNAL ;
    PORT
      LAYER metal1 ;
      RECT 0 0 0.720 1.120 ;
    END
  END p
END m153
MACRO m154
  SIZE 0.840 BY 0.960 ;
  PIN p
    DIRECTION INOUT ;
    USE SIGNAL ;
    PORT
      LAYER metal1 ;
      RECT 0 0 0.840 0.960 ;
    END
  END p
END m154
MACRO m155
  SIZE 1.010 BY 0.800 ;
  PIN p
    DIRECTION INOUT ;
    USE SIGNAL ;
    PORT
      LAYER metal1 ;
      RECT 0 0 1.010 0.800 ;
    END
  END p
END m155
MACRO m156
  SIZE 0.840 BY 0.960 ;
  PIN p
    DIRECTION INOUT ;
    USE SIGNAL ;
    PORT
      LAYER metal1 ;
      RECT 0 0 0.840 0.960 ;
    END
  END p
END m156
MACRO m157
  SIZE 0.630 BY 1.280 ;
  PIN p
    DIRECTION INOUT ;
    USE SIGNAL ;
    PORT
      LAYER metal1 ;
      RECT 0 0 0.630 1.280 ;
    END
  END p
END m157
MACRO m158
  SIZE 1.010 BY 0.800 ;
  PIN p
    DIRECTION INOUT ;
    USE SIGNAL ;
    PORT
      LAYER metal1 ;
      RECT 0 0 1.010 0.800 ;
    END
  END p
END m158
MACRO m159
  SIZE 1.010 BY 0.800 ;
  PIN p
    DIRECTION INOUT ;
    USE SIGNAL ;
    PORT
      LAYER metal1 ;
      RECT 0 0 1.010 0.800 ;
    END
  END p
END m159
MACRO m160
  SIZE 0.840 BY 0.960 ;
  PIN p
    DIRECTION INOUT ;
    USE SIGNAL ;
    PORT
      LAYER metal1 ;
      RECT 0 0 0.840 0.960 ;
    END
  END p
END m160
MACRO m161
  SIZE 1.010 BY 0.800 ;
  PIN p
    DIRECTION INOUT ;
    USE SIGNAL ;
    PORT
      LAYER metal1 ;
      RECT 0 0 1.010 0.800 ;
    END
  END p
END m161
MACRO m162
  SIZE 0.840 BY 0.960 ;
  PIN p
    DIRECTION INOUT ;
    USE SIGNAL ;
    PORT
      LAYER metal1 ;
      RECT 0 0 0.840 0.960 ;
    END
  END p
END m162
MACRO m163
  SIZE 0.840 BY 0.960 ;
  PIN p
    DIRECTION INOUT ;
    USE SIGNAL ;
    PORT
      LAYER metal1 ;
      RECT 0 0 0.840 0.960 ;
    END
  END p
END m163
MACRO m164
  SIZE 1.010 BY 0.800 ;
  PIN p
    DIRECTION INOUT ;
    USE SIGNAL ;
    PORT
      LAYER metal1 ;
      RECT 0 0 1.010 0.800 ;
    END
  END p
END m164
MACRO m165
  SIZE 1.010 BY 0.800 ;
  PIN p
    DIRECTION INOUT ;
    USE SIGNAL ;
    PORT
      LAYER metal1 ;
      RECT 0 0 1.010 0.800 ;
    END
  END p
END m165
MACRO m166
  SIZE 0.840 BY 0.960 ;
  PIN p
    DIRECTION INOUT ;
    USE SIGNAL ;
    PORT
      LAYER metal1 ;
      RECT 0 0 0.840 0.960 ;
    END
  END p
END m166
MACRO m167
  SIZE 0.840 BY 0.960 ;
  PIN p
    DIRECTION INOUT ;
    USE SIGNAL ;
    PORT
      LAYER metal1 ;
      RECT 0 0 0.840 0.960 ;
    END
  END p
END m167
MACRO m168
  SIZE 1.010 BY 0.800 ;
  PIN p
    DIRECTION INOUT ;
    USE SIGNAL ;
    PORT
      LAYER metal1 ;
      RECT 0 0 1.010 0.800 ;
    END
  END p
END m168
MACRO m169
  SIZE 1.010 BY 0.800 ;
  PIN p
    DIRECTION INOUT ;
    USE SIGNAL ;
    PORT
      LAYER metal1 ;
      RECT 0 0 1.010 0.800 ;
    END
  END p
END m169
MACRO m170
  SIZE 0.840 BY 0.960 ;
  PIN p
    DIRECTION INOUT ;
    USE SIGNAL ;
    PORT
      LAYER metal1 ;
      RECT 0 0 0.840 0.960 ;
    END
  END p
END m170
MACRO m171
  SIZE 0.720 BY 1.120 ;
  PIN p
    DIRECTION INOUT ;
    USE SIGNAL ;
    PORT
      LAYER metal1 ;
      RECT 0 0 0.720 1.120 ;
    END
  END p
END m171
MACRO m172
  SIZE 1.010 BY 0.800 ;
  PIN p
    DIRECTION INOUT ;
    USE SIGNAL ;
    PORT
      LAYER metal1 ;
      RECT 0 0 1.010 0.800 ;
    END
  END p
END m172
MACRO m173
  SIZE 1.010 BY 0.800 ;
  PIN p
    DIRECTION INOUT ;
    USE SIGNAL ;
    PORT
      LAYER metal1 ;
      RECT 0 0 1.010 0.800 ;
    END
  END p
END m173
MACRO m174
  SIZE 1.010 BY 0.800 ;
  PIN p
    DIRECTION INOUT ;
    USE SIGNAL ;
    PORT
      LAYER metal1 ;
      RECT 0 0 1.010 0.800 ;
    END
  END p
END m174
MACRO m175
  SIZE 0.840 BY 0.960 ;
  PIN p
    DIRECTION INOUT ;
    USE SIGNAL ;
    PORT
      LAYER metal1 ;
      RECT 0 0 0.840 0.960 ;
    END
  END p
END m175
MACRO m176
  SIZE 1.010 BY 0.800 ;
  PIN p
    DIRECTION INOUT ;
    USE SIGNAL ;
    PORT
      LAYER metal1 ;
      RECT 0 0 1.010 0.800 ;
    END
  END p
END m176
MACRO m177
  SIZE 0.630 BY 1.280 ;
  PIN p
    DIRECTION INOUT ;
    USE SIGNAL ;
    PORT
      LAYER metal1 ;
      RECT 0 0 0.630 1.280 ;
    END
  END p
END m177
MACRO m178
  SIZE 1.010 BY 0.800 ;
  PIN p
    DIRECTION INOUT ;
    USE SIGNAL ;
    PORT
      LAYER metal1 ;
      RECT 0 0 1.010 0.800 ;
    END
  END p
END m178
MACRO m179
  SIZE 0.840 BY 0.960 ;
  PIN p
    DIRECTION INOUT ;
    USE SIGNAL ;
    PORT
      LAYER metal1 ;
      RECT 0 0 0.840 0.960 ;
    END
  END p
END m179
MACRO m180
  SIZE 1.010 BY 0.800 ;
  PIN p
    DIRECTION INOUT ;
    USE SIGNAL ;
    PORT
      LAYER metal1 ;
      RECT 0 0 1.010 0.800 ;
    END
  END p
END m180
MACRO m181
  SIZE 1.010 BY 0.800 ;
  PIN p
    DIRECTION INOUT ;
    USE SIGNAL ;
    PORT
      LAYER metal1 ;
      RECT 0 0 1.010 0.800 ;
    END
  END p
END m181
MACRO m182
  SIZE 1.010 BY 0.800 ;
  PIN p
    DIRECTION INOUT ;
    USE SIGNAL ;
    PORT
      LAYER metal1 ;
      RECT 0 0 1.010 0.800 ;
    END
  END p
END m182
MACRO m183
  SIZE 0.840 BY 0.960 ;
  PIN p
    DIRECTION INOUT ;
    USE SIGNAL ;
    PORT
      LAYER metal1 ;
      RECT 0 0 0.840 0.960 ;
    END
  END p
END m183
MACRO m184
  SIZE 0.840 BY 0.960 ;
  PIN p
    DIRECTION INOUT ;
    USE SIGNAL ;
    PORT
      LAYER metal1 ;
      RECT 0 0 0.840 0.960 ;
    END
  END p
END m184
MACRO m185
  SIZE 1.010 BY 0.800 ;
  PIN p
    DIRECTION INOUT ;
    USE SIGNAL ;
    PORT
      LAYER metal1 ;
      RECT 0 0 1.010 0.800 ;
    END
  END p
END m185
MACRO m186
  SIZE 1.010 BY 0.800 ;
  PIN p
    DIRECTION INOUT ;
    USE SIGNAL ;
    PORT
      LAYER metal1 ;
      RECT 0 0 1.010 0.800 ;
    END
  END p
END m186
MACRO m187
  SIZE 1.010 BY 0.800 ;
  PIN p
    DIRECTION INOUT ;
    USE SIGNAL ;
    PORT
      LAYER metal1 ;
      RECT 0 0 1.010 0.800 ;
    END
  END p
END m187
MACRO m188
  SIZE 1.010 BY 0.800 ;
  PIN p
    DIRECTION INOUT ;
    USE SIGNAL ;
    PORT
      LAYER metal1 ;
      RECT 0 0 1.010 0.800 ;
    END
  END p
END m188
MACRO m189
  SIZE 1.010 BY 0.800 ;
  PIN p
    DIRECTION INOUT ;
    USE SIGNAL ;
    PORT
      LAYER metal1 ;
      RECT 0 0 1.010 0.800 ;
    END
  END p
END m189
MACRO m190
  SIZE 1.010 BY 0.800 ;
  PIN p
    DIRECTION INOUT ;
    USE SIGNAL ;
    PORT
      LAYER metal1 ;
      RECT 0 0 1.010 0.800 ;
    END
  END p
END m190
MACRO m191
  SIZE 1.010 BY 0.800 ;
  PIN p
    DIRECTION INOUT ;
    USE SIGNAL ;
    PORT
      LAYER metal1 ;
      RECT 0 0 1.010 0.800 ;
    END
  END p
END m191
MACRO m192
  SIZE 0.720 BY 1.120 ;
  PIN p
    DIRECTION INOUT ;
    USE SIGNAL ;
    PORT
      LAYER metal1 ;
      RECT 0 0 0.720 1.120 ;
    END
  END p
END m192
MACRO m193
  SIZE 0.720 BY 1.120 ;
  PIN p
    DIRECTION INOUT ;
    USE SIGNAL ;
    PORT
      LAYER metal1 ;
      RECT 0 0 0.720 1.120 ;
    END
  END p
END m193
MACRO m194
  SIZE 1.010 BY 0.800 ;
  PIN p
    DIRECTION INOUT ;
    USE SIGNAL ;
    PORT
      LAYER metal1 ;
      RECT 0 0 1.010 0.800 ;
    END
  END p
END m194
MACRO m195
  SIZE 0.720 BY 1.120 ;
  PIN p
    DIRECTION INOUT ;
    USE SIGNAL ;
    PORT
      LAYER metal1 ;
      RECT 0 0 0.720 1.120 ;
    END
  END p
END m195
MACRO m196
  SIZE 1.010 BY 0.800 ;
  PIN p
    DIRECTION INOUT ;
    USE SIGNAL ;
    PORT
      LAYER metal1 ;
      RECT 0 0 1.010 0.800 ;
    END
  END p
END m196
MACRO m197
  SIZE 1.010 BY 0.800 ;
  PIN p
    DIRECTION INOUT ;
    USE SIGNAL ;
    PORT
      LAYER metal1 ;
      RECT 0 0 1.010 0.800 ;
    END
  END p
END m197
MACRO m198
  SIZE 1.010 BY 0.800 ;
  PIN p
    DIRECTION INOUT ;
    USE SIGNAL ;
    PORT
      LAYER metal1 ;
      RECT 0 0 1.010 0.800 ;
    END
  END p
END m198
MACRO m199
  SIZE 1.010 BY 0.800 ;
  PIN p
    DIRECTION INOUT ;
    USE SIGNAL ;
    PORT
      LAYER metal1 ;
      RECT 0 0 1.010 0.800 ;
    END
  END p
END m199
MACRO m200
  SIZE 0.840 BY 0.960 ;
  PIN p
    DIRECTION INOUT ;
    USE SIGNAL ;
    PORT
      LAYER metal1 ;
      RECT 0 0 0.840 0.960 ;
    END
  END p
END m200
MACRO m201
  SIZE 1.010 BY 0.800 ;
  PIN p
    DIRECTION INOUT ;
    USE SIGNAL ;
    PORT
      LAYER metal1 ;
      RECT 0 0 1.010 0.800 ;
    END
  END p
END m201
MACRO m202
  SIZE 1.010 BY 0.800 ;
  PIN p
    DIRECTION INOUT ;
    USE SIGNAL ;
    PORT
      LAYER metal1 ;
      RECT 0 0 1.010 0.800 ;
    END
  END p
END m202
MACRO m203
  SIZE 0.840 BY 0.960 ;
  PIN p
    DIRECTION INOUT ;
    USE SIGNAL ;
    PORT
      LAYER metal1 ;
      RECT 0 0 0.840 0.960 ;
    END
  END p
END m203
MACRO m204
  SIZE 1.010 BY 0.800 ;
  PIN p
    DIRECTION INOUT ;
    USE SIGNAL ;
    PORT
      LAYER metal1 ;
      RECT 0 0 1.010 0.800 ;
    END
  END p
END m204
MACRO m205
  SIZE 0.840 BY 0.960 ;
  PIN p
    DIRECTION INOUT ;
    USE SIGNAL ;
    PORT
      LAYER metal1 ;
      RECT 0 0 0.840 0.960 ;
    END
  END p
END m205
MACRO m206
  SIZE 1.010 BY 0.800 ;
  PIN p
    DIRECTION INOUT ;
    USE SIGNAL ;
    PORT
      LAYER metal1 ;
      RECT 0 0 1.010 0.800 ;
    END
  END p
END m206
MACRO m207
  SIZE 0.840 BY 0.960 ;
  PIN p
    DIRECTION INOUT ;
    USE SIGNAL ;
    PORT
      LAYER metal1 ;
      RECT 0 0 0.840 0.960 ;
    END
  END p
END m207
MACRO m208
  SIZE 1.010 BY 0.800 ;
  PIN p
    DIRECTION INOUT ;
    USE SIGNAL ;
    PORT
      LAYER metal1 ;
      RECT 0 0 1.010 0.800 ;
    END
  END p
END m208
MACRO m209
  SIZE 0.840 BY 0.960 ;
  PIN p
    DIRECTION INOUT ;
    USE SIGNAL ;
    PORT
      LAYER metal1 ;
      RECT 0 0 0.840 0.960 ;
    END
  END p
END m209
MACRO m210
  SIZE 0.840 BY 0.960 ;
  PIN p
    DIRECTION INOUT ;
    USE SIGNAL ;
    PORT
      LAYER metal1 ;
      RECT 0 0 0.840 0.960 ;
    END
  END p
END m210
MACRO m211
  SIZE 0.720 BY 1.120 ;
  PIN p
    DIRECTION INOUT ;
    USE SIGNAL ;
    PORT
      LAYER metal1 ;
      RECT 0 0 0.720 1.120 ;
    END
  END p
END m211
MACRO m212
  SIZE 1.010 BY 0.800 ;
  PIN p
    DIRECTION INOUT ;
    USE SIGNAL ;
    PORT
      LAYER metal1 ;
      RECT 0 0 1.010 0.800 ;
    END
  END p
END m212
MACRO m213
  SIZE 1.010 BY 0.800 ;
  PIN p
    DIRECTION INOUT ;
    USE SIGNAL ;
    PORT
      LAYER metal1 ;
      RECT 0 0 1.010 0.800 ;
    END
  END p
END m213
MACRO m214
  SIZE 0.720 BY 1.120 ;
  PIN p
    DIRECTION INOUT ;
    USE SIGNAL ;
    PORT
      LAYER metal1 ;
      RECT 0 0 0.720 1.120 ;
    END
  END p
END m214
MACRO m215
  SIZE 1.010 BY 0.800 ;
  PIN p
    DIRECTION INOUT ;
    USE SIGNAL ;
    PORT
      LAYER metal1 ;
      RECT 0 0 1.010 0.800 ;
    END
  END p
END m215
MACRO m216
  SIZE 1.260 BY 0.640 ;
  PIN p
    DIRECTION INOUT ;
    USE SIGNAL ;
    PORT
      LAYER metal1 ;
      RECT 0 0 1.260 0.640 ;
    END
  END p
END m216
MACRO m217
  SIZE 0.630 BY 1.280 ;
  PIN p
    DIRECTION INOUT ;
    USE SIGNAL ;
    PORT
      LAYER metal1 ;
      RECT 0 0 0.630 1.280 ;
    END
  END p
END m217
MACRO m218
  SIZE 0.840 BY 0.960 ;
  PIN p
    DIRECTION INOUT ;
    USE SIGNAL ;
    PORT
      LAYER metal1 ;
      RECT 0 0 0.840 0.960 ;
    END
  END p
END m218
MACRO m219
  SIZE 1.010 BY 0.800 ;
  PIN p
    DIRECTION INOUT ;
    USE SIGNAL ;
    PORT
      LAYER metal1 ;
      RECT 0 0 1.010 0.800 ;
    END
  END p
END m219
MACRO m220
  SIZE 1.010 BY 0.800 ;
  PIN p
    DIRECTION INOUT ;
    USE SIGNAL ;
    PORT
      LAYER metal1 ;
      RECT 0 0 1.010 0.800 ;
    END
  END p
END m220
MACRO m221
  SIZE 1.010 BY 0.800 ;
  PIN p
    DIRECTION INOUT ;
    USE SIGNAL ;
    PORT
      LAYER metal1 ;
      RECT 0 0 1.010 0.800 ;
    END
  END p
END m221
MACRO m222
  SIZE 0.840 BY 0.960 ;
  PIN p
    DIRECTION INOUT ;
    USE SIGNAL ;
    PORT
      LAYER metal1 ;
      RECT 0 0 0.840 0.960 ;
    END
  END p
END m222
MACRO m223
  SIZE 0.840 BY 0.960 ;
  PIN p
    DIRECTION INOUT ;
    USE SIGNAL ;
    PORT
      LAYER metal1 ;
      RECT 0 0 0.840 0.960 ;
    END
  END p
END m223
MACRO m224
  SIZE 1.010 BY 0.800 ;
  PIN p
    DIRECTION INOUT ;
    USE SIGNAL ;
    PORT
      LAYER metal1 ;
      RECT 0 0 1.010 0.800 ;
    END
  END p
END m224
MACRO m225
  SIZE 1.010 BY 0.800 ;
  PIN p
    DIRECTION INOUT ;
    USE SIGNAL ;
    PORT
      LAYER metal1 ;
      RECT 0 0 1.010 0.800 ;
    END
  END p
END m225
MACRO m226
  SIZE 0.840 BY 0.960 ;
  PIN p
    DIRECTION INOUT ;
    USE SIGNAL ;
    PORT
      LAYER metal1 ;
      RECT 0 0 0.840 0.960 ;
    END
  END p
END m226
MACRO m227
  SIZE 1.010 BY 0.800 ;
  PIN p
    DIRECTION INOUT ;
    USE SIGNAL ;
    PORT
      LAYER metal1 ;
      RECT 0 0 1.010 0.800 ;
    END
  END p
END m227
MACRO m228
  SIZE 0.840 BY 0.960 ;
  PIN p
    DIRECTION INOUT ;
    USE SIGNAL ;
    PORT
      LAYER metal1 ;
      RECT 0 0 0.840 0.960 ;
    END
  END p
END m228
MACRO m229
  SIZE 0.630 BY 1.280 ;
  PIN p
    DIRECTION INOUT ;
    USE SIGNAL ;
    PORT
      LAYER metal1 ;
      RECT 0 0 0.630 1.280 ;
    END
  END p
END m229
MACRO m230
  SIZE 0.840 BY 0.960 ;
  PIN p
    DIRECTION INOUT ;
    USE SIGNAL ;
    PORT
      LAYER metal1 ;
      RECT 0 0 0.840 0.960 ;
    END
  END p
END m230
MACRO m231
  SIZE 0.840 BY 0.960 ;
  PIN p
    DIRECTION INOUT ;
    USE SIGNAL ;
    PORT
      LAYER metal1 ;
      RECT 0 0 0.840 0.960 ;
    END
  END p
END m231
MACRO m232
  SIZE 1.010 BY 0.800 ;
  PIN p
    DIRECTION INOUT ;
    USE SIGNAL ;
    PORT
      LAYER metal1 ;
      RECT 0 0 1.010 0.800 ;
    END
  END p
END m232
MACRO m233
  SIZE 1.010 BY 0.800 ;
  PIN p
    DIRECTION INOUT ;
    USE SIGNAL ;
    PORT
      LAYER metal1 ;
      RECT 0 0 1.010 0.800 ;
    END
  END p
END m233
MACRO m234
  SIZE 0.720 BY 1.120 ;
  PIN p
    DIRECTION INOUT ;
    USE SIGNAL ;
    PORT
      LAYER metal1 ;
      RECT 0 0 0.720 1.120 ;
    END
  END p
END m234
MACRO m235
  SIZE 1.010 BY 0.800 ;
  PIN p
    DIRECTION INOUT ;
    USE SIGNAL ;
    PORT
      LAYER metal1 ;
      RECT 0 0 1.010 0.800 ;
    END
  END p
END m235
MACRO m236
  SIZE 0.720 BY 1.120 ;
  PIN p
    DIRECTION INOUT ;
    USE SIGNAL ;
    PORT
      LAYER metal1 ;
      RECT 0 0 0.720 1.120 ;
    END
  END p
END m236
MACRO m237
  SIZE 0.720 BY 1.120 ;
  PIN p
    DIRECTION INOUT ;
    USE SIGNAL ;
    PORT
      LAYER metal1 ;
      RECT 0 0 0.720 1.120 ;
    END
  END p
END m237
MACRO m238
  SIZE 1.010 BY 0.800 ;
  PIN p
    DIRECTION INOUT ;
    USE SIGNAL ;
    PORT
      LAYER metal1 ;
      RECT 0 0 1.010 0.800 ;
    END
  END p
END m238
MACRO m239
  SIZE 1.010 BY 0.800 ;
  PIN p
    DIRECTION INOUT ;
    USE SIGNAL ;
    PORT
      LAYER metal1 ;
      RECT 0 0 1.010 0.800 ;
    END
  END p
END m239
MACRO m240
  SIZE 0.630 BY 1.280 ;
  PIN p
    DIRECTION INOUT ;
    USE SIGNAL ;
    PORT
      LAYER metal1 ;
      RECT 0 0 0.630 1.280 ;
    END
  END p
END m240
MACRO m241
  SIZE 0.840 BY 0.960 ;
  PIN p
    DIRECTION INOUT ;
    USE SIGNAL ;
    PORT
      LAYER metal1 ;
      RECT 0 0 0.840 0.960 ;
    END
  END p
END m241
MACRO m242
  SIZE 0.840 BY 0.960 ;
  PIN p
    DIRECTION INOUT ;
    USE SIGNAL ;
    PORT
      LAYER metal1 ;
      RECT 0 0 0.840 0.960 ;
    END
  END p
END m242
MACRO m243
  SIZE 7.010 BY 3.840 ;
  PIN p
    DIRECTION INOUT ;
    USE SIGNAL ;
    PORT
      LAYER metal1 ;
      RECT 0 0 7.010 3.840 ;
    END
  END p
END m243
MACRO m244
  SIZE 1.010 BY 0.800 ;
  PIN p
    DIRECTION INOUT ;
    USE SIGNAL ;
    PORT
      LAYER metal1 ;
      RECT 0 0 1.010 0.800 ;
    END
  END p
END m244
MACRO m245
  SIZE 1.010 BY 0.800 ;
  PIN p
    DIRECTION INOUT ;
    USE SIGNAL ;
    PORT
      LAYER metal1 ;
      RECT 0 0 1.010 0.800 ;
    END
  END p
END m245
MACRO m246
  SIZE 0.510 BY 0.226 ;
  PIN p
    DIRECTION INOUT ;
    USE SIGNAL ;
    PORT
      LAYER metal1 ;
      RECT 0 0 0.510 0.226 ;
    END
  END p
END m246
MACRO m247
  SIZE 0.510 BY 0.207 ;
  PIN p
    DIRECTION INOUT ;
    USE SIGNAL ;
    PORT
      LAYER metal1 ;
      RECT 0 0 0.510 0.207 ;
    END
  END p
END m247
MACRO m248
  SIZE 0.510 BY 0.533 ;
  PIN p
    DIRECTION INOUT ;
    USE SIGNAL ;
    PORT
      LAYER metal1 ;
      RECT 0 0 0.510 0.533 ;
    END
  END p
END m248
MACRO m249
  SIZE 0.510 BY 0.307 ;
  PIN p
    DIRECTION INOUT ;
    USE SIGNAL ;
    PORT
      LAYER metal1 ;
      RECT 0 0 0.510 0.307 ;
    END
  END p
END m249
MACRO m250
  SIZE 0.510 BY 0.264 ;
  PIN p
    DIRECTION INOUT ;
    USE SIGNAL ;
    PORT
      LAYER metal1 ;
      RECT 0 0 0.510 0.264 ;
    END
  END p
END m250
MACRO m251
  SIZE 0.510 BY 0.496 ;
  PIN p
    DIRECTION INOUT ;
    USE SIGNAL ;
    PORT
      LAYER metal1 ;
      RECT 0 0 0.510 0.496 ;
    END
  END p
END m251
MACRO m252
  SIZE 0.510 BY 0.464 ;
  PIN p
    DIRECTION INOUT ;
    USE SIGNAL ;
    PORT
      LAYER metal1 ;
      RECT 0 0 0.510 0.464 ;
    END
  END p
END m252
MACRO m253
  SIZE 0.510 BY 0.226 ;
  PIN p
    DIRECTION INOUT ;
    USE SIGNAL ;
    PORT
      LAYER metal1 ;
      RECT 0 0 0.510 0.226 ;
    END
  END p
END m253
MACRO m254
  SIZE 0.510 BY 0.540 ;
  PIN p
    DIRECTION INOUT ;
    USE SIGNAL ;
    PORT
      LAYER metal1 ;
      RECT 0 0 0.510 0.540 ;
    END
  END p
END m254
MACRO m255
  SIZE 0.510 BY 0.264 ;
  PIN p
    DIRECTION INOUT ;
    USE SIGNAL ;
    PORT
      LAYER metal1 ;
      RECT 0 0 0.510 0.264 ;
    END
  END p
END m255
MACRO m256
  SIZE 0.510 BY 0.408 ;
  PIN p
    DIRECTION INOUT ;
    USE SIGNAL ;
    PORT
      LAYER metal1 ;
      RECT 0 0 0.510 0.408 ;
    END
  END p
END m256
MACRO m257
  SIZE 0.510 BY 0.333 ;
  PIN p
    DIRECTION INOUT ;
    USE SIGNAL ;
    PORT
      LAYER metal1 ;
      RECT 0 0 0.510 0.333 ;
    END
  END p
END m257
MACRO m258
  SIZE 0.510 BY 0.270 ;
  PIN p
    DIRECTION INOUT ;
    USE SIGNAL ;
    PORT
      LAYER metal1 ;
      RECT 0 0 0.510 0.270 ;
    END
  END p
END m258
MACRO m259
  SIZE 0.510 BY 0.345 ;
  PIN p
    DIRECTION INOUT ;
    USE SIGNAL ;
    PORT
      LAYER metal1 ;
      RECT 0 0 0.510 0.345 ;
    END
  END p
END m259
MACRO m260
  SIZE 0.510 BY 0.295 ;
  PIN p
    DIRECTION INOUT ;
    USE SIGNAL ;
    PORT
      LAYER metal1 ;
      RECT 0 0 0.510 0.295 ;
    END
  END p
END m260
MACRO m261
  SIZE 0.510 BY 0.264 ;
  PIN p
    DIRECTION INOUT ;
    USE SIGNAL ;
    PORT
      LAYER metal1 ;
      RECT 0 0 0.510 0.264 ;
    END
  END p
END m261
MACRO m262
  SIZE 0.510 BY 0.207 ;
  PIN p
    DIRECTION INOUT ;
    USE SIGNAL ;
    PORT
      LAYER metal1 ;
      RECT 0 0 0.510 0.207 ;
    END
  END p
END m262
MACRO m263
  SIZE 0.510 BY 0.289 ;
  PIN p
    DIRECTION INOUT ;
    USE SIGNAL ;
    PORT
      LAYER metal1 ;
      RECT 0 0 0.510 0.289 ;
    END
  END p
END m263
MACRO m264
  SIZE 0.510 BY 0.251 ;
  PIN p
    DIRECTION INOUT ;
    USE SIGNAL ;
    PORT
      LAYER metal1 ;
      RECT 0 0 0.510 0.251 ;
    END
  END p
END m264
MACRO m265
  SIZE 0.510 BY 0.245 ;
  PIN p
    DIRECTION INOUT ;
    USE SIGNAL ;
    PORT
      LAYER metal1 ;
      RECT 0 0 0.510 0.245 ;
    END
  END p
END m265
MACRO m266
  SIZE 0.510 BY 0.345 ;
  PIN p
    DIRECTION INOUT ;
    USE SIGNAL ;
    PORT
      LAYER metal1 ;
      RECT 0 0 0.510 0.345 ;
    END
  END p
END m266
MACRO m267
  SIZE 0.510 BY 0.257 ;
  PIN p
    DIRECTION INOUT ;
    USE SIGNAL ;
    PORT
      LAYER metal1 ;
      RECT 0 0 0.510 0.257 ;
    END
  END p
END m267
MACRO m268
  SIZE 0.510 BY 0.207 ;
  PIN p
    DIRECTION INOUT ;
    USE SIGNAL ;
    PORT
      LAYER metal1 ;
      RECT 0 0 0.510 0.207 ;
    END
  END p
END m268
MACRO m269
  SIZE 0.510 BY 0.264 ;
  PIN p
    DIRECTION INOUT ;
    USE SIGNAL ;
    PORT
      LAYER metal1 ;
      RECT 0 0 0.510 0.264 ;
    END
  END p
END m269
MACRO m270
  SIZE 0.510 BY 0.207 ;
  PIN p
    DIRECTION INOUT ;
    USE SIGNAL ;
    PORT
      LAYER metal1 ;
      RECT 0 0 0.510 0.207 ;
    END
  END p
END m270
MACRO m271
  SIZE 0.510 BY 0.427 ;
  PIN p
    DIRECTION INOUT ;
    USE SIGNAL ;
    PORT
      LAYER metal1 ;
      RECT 0 0 0.510 0.427 ;
    END
  END p
END m271
MACRO m272
  SIZE 0.510 BY 0.226 ;
  PIN p
    DIRECTION INOUT ;
    USE SIGNAL ;
    PORT
      LAYER metal1 ;
      RECT 0 0 0.510 0.226 ;
    END
  END p
END m272
MACRO m273
  SIZE 0.510 BY 0.226 ;
  PIN p
    DIRECTION INOUT ;
    USE SIGNAL ;
    PORT
      LAYER metal1 ;
      RECT 0 0 0.510 0.226 ;
    END
  END p
END m273
MACRO m274
  SIZE 0.510 BY 0.201 ;
  PIN p
    DIRECTION INOUT ;
    USE SIGNAL ;
    PORT
      LAYER metal1 ;
      RECT 0 0 0.510 0.201 ;
    END
  END p
END m274
MACRO m275
  SIZE 0.510 BY 0.207 ;
  PIN p
    DIRECTION INOUT ;
    USE SIGNAL ;
    PORT
      LAYER metal1 ;
      RECT 0 0 0.510 0.207 ;
    END
  END p
END m275
MACRO m276
  SIZE 0.510 BY 0.207 ;
  PIN p
    DIRECTION INOUT ;
    USE SIGNAL ;
    PORT
      LAYER metal1 ;
      RECT 0 0 0.510 0.207 ;
    END
  END p
END m276
MACRO m277
  SIZE 0.510 BY 0.207 ;
  PIN p
    DIRECTION INOUT ;
    USE SIGNAL ;
    PORT
      LAYER metal1 ;
      RECT 0 0 0.510 0.207 ;
    END
  END p
END m277
MACRO m278
  SIZE 0.510 BY 0.358 ;
  PIN p
    DIRECTION INOUT ;
    USE SIGNAL ;
    PORT
      LAYER metal1 ;
      RECT 0 0 0.510 0.358 ;
    END
  END p
END m278
MACRO m279
  SIZE 0.510 BY 0.295 ;
  PIN p
    DIRECTION INOUT ;
    USE SIGNAL ;
    PORT
      LAYER metal1 ;
      RECT 0 0 0.510 0.295 ;
    END
  END p
END m279
MACRO m280
  SIZE 0.510 BY 0.207 ;
  PIN p
    DIRECTION INOUT ;
    USE SIGNAL ;
    PORT
      LAYER metal1 ;
      RECT 0 0 0.510 0.207 ;
    END
  END p
END m280
MACRO m281
  SIZE 0.510 BY 0.232 ;
  PIN p
    DIRECTION INOUT ;
    USE SIGNAL ;
    PORT
      LAYER metal1 ;
      RECT 0 0 0.510 0.232 ;
    END
  END p
END m281
MACRO m282
  SIZE 0.510 BY 0.207 ;
  PIN p
    DIRECTION INOUT ;
    USE SIGNAL ;
    PORT
      LAYER metal1 ;
      RECT 0 0 0.510 0.207 ;
    END
  END p
END m282
MACRO m283
  SIZE 0.510 BY 0.207 ;
  PIN p
    DIRECTION INOUT ;
    USE SIGNAL ;
    PORT
      LAYER metal1 ;
      RECT 0 0 0.510 0.207 ;
    END
  END p
END m283
MACRO m284
  SIZE 0.510 BY 0.351 ;
  PIN p
    DIRECTION INOUT ;
    USE SIGNAL ;
    PORT
      LAYER metal1 ;
      RECT 0 0 0.510 0.351 ;
    END
  END p
END m284
MACRO m285
  SIZE 0.510 BY 0.251 ;
  PIN p
    DIRECTION INOUT ;
    USE SIGNAL ;
    PORT
      LAYER metal1 ;
      RECT 0 0 0.510 0.251 ;
    END
  END p
END m285
MACRO m286
  SIZE 0.510 BY 0.257 ;
  PIN p
    DIRECTION INOUT ;
    USE SIGNAL ;
    PORT
      LAYER metal1 ;
      RECT 0 0 0.510 0.257 ;
    END
  END p
END m286
MACRO m287
  SIZE 0.510 BY 0.364 ;
  PIN p
    DIRECTION INOUT ;
    USE SIGNAL ;
    PORT
      LAYER metal1 ;
      RECT 0 0 0.510 0.364 ;
    END
  END p
END m287
MACRO m288
  SIZE 0.510 BY 0.207 ;
  PIN p
    DIRECTION INOUT ;
    USE SIGNAL ;
    PORT
      LAYER metal1 ;
      RECT 0 0 0.510 0.207 ;
    END
  END p
END m288
MACRO m289
  SIZE 0.510 BY 0.207 ;
  PIN p
    DIRECTION INOUT ;
    USE SIGNAL ;
    PORT
      LAYER metal1 ;
      RECT 0 0 0.510 0.207 ;
    END
  END p
END m289
MACRO m290
  SIZE 0.510 BY 0.238 ;
  PIN p
    DIRECTION INOUT ;
    USE SIGNAL ;
    PORT
      LAYER metal1 ;
      RECT 0 0 0.510 0.238 ;
    END
  END p
END m290
MACRO m291
  SIZE 0.510 BY 0.207 ;
  PIN p
    DIRECTION INOUT ;
    USE SIGNAL ;
    PORT
      LAYER metal1 ;
      RECT 0 0 0.510 0.207 ;
    END
  END p
END m291
MACRO m292
  SIZE 0.510 BY 0.151 ;
  PIN p
    DIRECTION INOUT ;
    USE SIGNAL ;
    PORT
      LAYER metal1 ;
      RECT 0 0 0.510 0.151 ;
    END
  END p
END m292
MACRO m293
  SIZE 0.510 BY 0.207 ;
  PIN p
    DIRECTION INOUT ;
    USE SIGNAL ;
    PORT
      LAYER metal1 ;
      RECT 0 0 0.510 0.207 ;
    END
  END p
END m293
MACRO m294
  SIZE 0.510 BY 0.207 ;
  PIN p
    DIRECTION INOUT ;
    USE SIGNAL ;
    PORT
      LAYER metal1 ;
      RECT 0 0 0.510 0.207 ;
    END
  END p
END m294
MACRO m295
  SIZE 0.510 BY 0.207 ;
  PIN p
    DIRECTION INOUT ;
    USE SIGNAL ;
    PORT
      LAYER metal1 ;
      RECT 0 0 0.510 0.207 ;
    END
  END p
END m295
MACRO m296
  SIZE 0.510 BY 0.207 ;
  PIN p
    DIRECTION INOUT ;
    USE SIGNAL ;
    PORT
      LAYER metal1 ;
      RECT 0 0 0.510 0.207 ;
    END
  END p
END m296
MACRO m297
  SIZE 0.510 BY 0.489 ;
  PIN p
    DIRECTION INOUT ;
    USE SIGNAL ;
    PORT
      LAYER metal1 ;
      RECT 0 0 0.510 0.489 ;
    END
  END p
END m297
MACRO m298
  SIZE 0.510 BY 0.019 ;
  PIN p
    DIRECTION INOUT ;
    USE SIGNAL ;
    PORT
      LAYER metal1 ;
      RECT 0 0 0.510 0.019 ;
    END
  END p
END m298
MACRO m299
  SIZE 0.510 BY 0.458 ;
  PIN p
    DIRECTION INOUT ;
    USE SIGNAL ;
    PORT
      LAYER metal1 ;
      RECT 0 0 0.510 0.458 ;
    END
  END p
END m299
MACRO m300
  SIZE 0.510 BY 0.395 ;
  PIN p
    DIRECTION INOUT ;
    USE SIGNAL ;
    PORT
      LAYER metal1 ;
      RECT 0 0 0.510 0.395 ;
    END
  END p
END m300
MACRO m301
  SIZE 0.510 BY 0.207 ;
  PIN p
    DIRECTION INOUT ;
    USE SIGNAL ;
    PORT
      LAYER metal1 ;
      RECT 0 0 0.510 0.207 ;
    END
  END p
END m301
MACRO m302
  SIZE 0.510 BY 0.207 ;
  PIN p
    DIRECTION INOUT ;
    USE SIGNAL ;
    PORT
      LAYER metal1 ;
      RECT 0 0 0.510 0.207 ;
    END
  END p
END m302
MACRO m303
  SIZE 0.510 BY 0.207 ;
  PIN p
    DIRECTION INOUT ;
    USE SIGNAL ;
    PORT
      LAYER metal1 ;
      RECT 0 0 0.510 0.207 ;
    END
  END p
END m303
MACRO m304
  SIZE 0.510 BY 0.207 ;
  PIN p
    DIRECTION INOUT ;
    USE SIGNAL ;
    PORT
      LAYER metal1 ;
      RECT 0 0 0.510 0.207 ;
    END
  END p
END m304
MACRO m305
  SIZE 0.510 BY 0.232 ;
  PIN p
    DIRECTION INOUT ;
    USE SIGNAL ;
    PORT
      LAYER metal1 ;
      RECT 0 0 0.510 0.232 ;
    END
  END p
END m305
MACRO m306
  SIZE 0.510 BY 0.282 ;
  PIN p
    DIRECTION INOUT ;
    USE SIGNAL ;
    PORT
      LAYER metal1 ;
      RECT 0 0 0.510 0.282 ;
    END
  END p
END m306
MACRO m307
  SIZE 0.510 BY 0.358 ;
  PIN p
    DIRECTION INOUT ;
    USE SIGNAL ;
    PORT
      LAYER metal1 ;
      RECT 0 0 0.510 0.358 ;
    END
  END p
END m307
MACRO m308
  SIZE 0.510 BY 0.207 ;
  PIN p
    DIRECTION INOUT ;
    USE SIGNAL ;
    PORT
      LAYER metal1 ;
      RECT 0 0 0.510 0.207 ;
    END
  END p
END m308
MACRO m309
  SIZE 0.510 BY 0.207 ;
  PIN p
    DIRECTION INOUT ;
    USE SIGNAL ;
    PORT
      LAYER metal1 ;
      RECT 0 0 0.510 0.207 ;
    END
  END p
END m309
MACRO m310
  SIZE 0.510 BY 0.207 ;
  PIN p
    DIRECTION INOUT ;
    USE SIGNAL ;
    PORT
      LAYER metal1 ;
      RECT 0 0 0.510 0.207 ;
    END
  END p
END m310
MACRO m311
  SIZE 0.510 BY 0.251 ;
  PIN p
    DIRECTION INOUT ;
    USE SIGNAL ;
    PORT
      LAYER metal1 ;
      RECT 0 0 0.510 0.251 ;
    END
  END p
END m311
MACRO m312
  SIZE 0.510 BY 0.207 ;
  PIN p
    DIRECTION INOUT ;
    USE SIGNAL ;
    PORT
      LAYER metal1 ;
      RECT 0 0 0.510 0.207 ;
    END
  END p
END m312
MACRO m313
  SIZE 0.510 BY 0.207 ;
  PIN p
    DIRECTION INOUT ;
    USE SIGNAL ;
    PORT
      LAYER metal1 ;
      RECT 0 0 0.510 0.207 ;
    END
  END p
END m313
MACRO m314
  SIZE 0.510 BY 0.107 ;
  PIN p
    DIRECTION INOUT ;
    USE SIGNAL ;
    PORT
      LAYER metal1 ;
      RECT 0 0 0.510 0.107 ;
    END
  END p
END m314
MACRO m315
  SIZE 0.510 BY 0.402 ;
  PIN p
    DIRECTION INOUT ;
    USE SIGNAL ;
    PORT
      LAYER metal1 ;
      RECT 0 0 0.510 0.402 ;
    END
  END p
END m315
MACRO m316
  SIZE 0.510 BY 0.207 ;
  PIN p
    DIRECTION INOUT ;
    USE SIGNAL ;
    PORT
      LAYER metal1 ;
      RECT 0 0 0.510 0.207 ;
    END
  END p
END m316
MACRO m317
  SIZE 0.510 BY 0.282 ;
  PIN p
    DIRECTION INOUT ;
    USE SIGNAL ;
    PORT
      LAYER metal1 ;
      RECT 0 0 0.510 0.282 ;
    END
  END p
END m317
MACRO m318
  SIZE 0.510 BY 0.276 ;
  PIN p
    DIRECTION INOUT ;
    USE SIGNAL ;
    PORT
      LAYER metal1 ;
      RECT 0 0 0.510 0.276 ;
    END
  END p
END m318
MACRO m319
  SIZE 0.510 BY 0.552 ;
  PIN p
    DIRECTION INOUT ;
    USE SIGNAL ;
    PORT
      LAYER metal1 ;
      RECT 0 0 0.510 0.552 ;
    END
  END p
END m319
MACRO m320
  SIZE 0.510 BY 0.270 ;
  PIN p
    DIRECTION INOUT ;
    USE SIGNAL ;
    PORT
      LAYER metal1 ;
      RECT 0 0 0.510 0.270 ;
    END
  END p
END m320
MACRO m321
  SIZE 0.510 BY 0.307 ;
  PIN p
    DIRECTION INOUT ;
    USE SIGNAL ;
    PORT
      LAYER metal1 ;
      RECT 0 0 0.510 0.307 ;
    END
  END p
END m321
MACRO m322
  SIZE 0.510 BY 0.207 ;
  PIN p
    DIRECTION INOUT ;
    USE SIGNAL ;
    PORT
      LAYER metal1 ;
      RECT 0 0 0.510 0.207 ;
    END
  END p
END m322
MACRO m323
  SIZE 0.510 BY 0.207 ;
  PIN p
    DIRECTION INOUT ;
    USE SIGNAL ;
    PORT
      LAYER metal1 ;
      RECT 0 0 0.510 0.207 ;
    END
  END p
END m323
MACRO m324
  SIZE 0.510 BY 0.013 ;
  PIN p
    DIRECTION INOUT ;
    USE SIGNAL ;
    PORT
      LAYER metal1 ;
      RECT 0 0 0.510 0.013 ;
    END
  END p
END m324
MACRO m325
  SIZE 0.510 BY 0.270 ;
  PIN p
    DIRECTION INOUT ;
    USE SIGNAL ;
    PORT
      LAYER metal1 ;
      RECT 0 0 0.510 0.270 ;
    END
  END p
END m325
MACRO m326
  SIZE 0.510 BY 0.207 ;
  PIN p
    DIRECTION INOUT ;
    USE SIGNAL ;
    PORT
      LAYER metal1 ;
      RECT 0 0 0.510 0.207 ;
    END
  END p
END m326
MACRO m327
  SIZE 0.510 BY 0.207 ;
  PIN p
    DIRECTION INOUT ;
    USE SIGNAL ;
    PORT
      LAYER metal1 ;
      RECT 0 0 0.510 0.207 ;
    END
  END p
END m327
MACRO m328
  SIZE 0.510 BY 0.207 ;
  PIN p
    DIRECTION INOUT ;
    USE SIGNAL ;
    PORT
      LAYER metal1 ;
      RECT 0 0 0.510 0.207 ;
    END
  END p
END m328
MACRO m329
  SIZE 0.510 BY 0.207 ;
  PIN p
    DIRECTION INOUT ;
    USE SIGNAL ;
    PORT
      LAYER metal1 ;
      RECT 0 0 0.510 0.207 ;
    END
  END p
END m329
MACRO m330
  SIZE 0.510 BY 0.207 ;
  PIN p
    DIRECTION INOUT ;
    USE SIGNAL ;
    PORT
      LAYER metal1 ;
      RECT 0 0 0.510 0.207 ;
    END
  END p
END m330
MACRO m331
  SIZE 0.510 BY 0.264 ;
  PIN p
    DIRECTION INOUT ;
    USE SIGNAL ;
    PORT
      LAYER metal1 ;
      RECT 0 0 0.510 0.264 ;
    END
  END p
END m331
MACRO m332
  SIZE 0.510 BY 0.207 ;
  PIN p
    DIRECTION INOUT ;
    USE SIGNAL ;
    PORT
      LAYER metal1 ;
      RECT 0 0 0.510 0.207 ;
    END
  END p
END m332
MACRO m333
  SIZE 0.510 BY 0.207 ;
  PIN p
    DIRECTION INOUT ;
    USE SIGNAL ;
    PORT
      LAYER metal1 ;
      RECT 0 0 0.510 0.207 ;
    END
  END p
END m333
MACRO m334
  SIZE 0.510 BY 0.207 ;
  PIN p
    DIRECTION INOUT ;
    USE SIGNAL ;
    PORT
      LAYER metal1 ;
      RECT 0 0 0.510 0.207 ;
    END
  END p
END m334
MACRO m335
  SIZE 0.510 BY 0.207 ;
  PIN p
    DIRECTION INOUT ;
    USE SIGNAL ;
    PORT
      LAYER metal1 ;
      RECT 0 0 0.510 0.207 ;
    END
  END p
END m335
MACRO m336
  SIZE 0.510 BY 0.264 ;
  PIN p
    DIRECTION INOUT ;
    USE SIGNAL ;
    PORT
      LAYER metal1 ;
      RECT 0 0 0.510 0.264 ;
    END
  END p
END m336
MACRO m337
  SIZE 0.510 BY 0.207 ;
  PIN p
    DIRECTION INOUT ;
    USE SIGNAL ;
    PORT
      LAYER metal1 ;
      RECT 0 0 0.510 0.207 ;
    END
  END p
END m337
MACRO m338
  SIZE 0.510 BY 0.207 ;
  PIN p
    DIRECTION INOUT ;
    USE SIGNAL ;
    PORT
      LAYER metal1 ;
      RECT 0 0 0.510 0.207 ;
    END
  END p
END m338
MACRO m339
  SIZE 0.510 BY 0.282 ;
  PIN p
    DIRECTION INOUT ;
    USE SIGNAL ;
    PORT
      LAYER metal1 ;
      RECT 0 0 0.510 0.282 ;
    END
  END p
END m339
MACRO m340
  SIZE 0.510 BY 0.445 ;
  PIN p
    DIRECTION INOUT ;
    USE SIGNAL ;
    PORT
      LAYER metal1 ;
      RECT 0 0 0.510 0.445 ;
    END
  END p
END m340
MACRO m341
  SIZE 0.510 BY 0.207 ;
  PIN p
    DIRECTION INOUT ;
    USE SIGNAL ;
    PORT
      LAYER metal1 ;
      RECT 0 0 0.510 0.207 ;
    END
  END p
END m341
MACRO m342
  SIZE 0.510 BY 0.264 ;
  PIN p
    DIRECTION INOUT ;
    USE SIGNAL ;
    PORT
      LAYER metal1 ;
      RECT 0 0 0.510 0.264 ;
    END
  END p
END m342
MACRO m343
  SIZE 0.510 BY 0.207 ;
  PIN p
    DIRECTION INOUT ;
    USE SIGNAL ;
    PORT
      LAYER metal1 ;
      RECT 0 0 0.510 0.207 ;
    END
  END p
END m343
MACRO m344
  SIZE 0.510 BY 0.006 ;
  PIN p
    DIRECTION INOUT ;
    USE SIGNAL ;
    PORT
      LAYER metal1 ;
      RECT 0 0 0.510 0.006 ;
    END
  END p
END m344
MACRO m345
  SIZE 0.510 BY 0.809 ;
  PIN p
    DIRECTION INOUT ;
    USE SIGNAL ;
    PORT
      LAYER metal1 ;
      RECT 0 0 0.510 0.809 ;
    END
  END p
END m345
MACRO m346
  SIZE 0.510 BY 0.245 ;
  PIN p
    DIRECTION INOUT ;
    USE SIGNAL ;
    PORT
      LAYER metal1 ;
      RECT 0 0 0.510 0.245 ;
    END
  END p
END m346
MACRO m347
  SIZE 0.510 BY 0.232 ;
  PIN p
    DIRECTION INOUT ;
    USE SIGNAL ;
    PORT
      LAYER metal1 ;
      RECT 0 0 0.510 0.232 ;
    END
  END p
END m347
MACRO m348
  SIZE 0.510 BY 0.207 ;
  PIN p
    DIRECTION INOUT ;
    USE SIGNAL ;
    PORT
      LAYER metal1 ;
      RECT 0 0 0.510 0.207 ;
    END
  END p
END m348
MACRO m349
  SIZE 0.510 BY 0.220 ;
  PIN p
    DIRECTION INOUT ;
    USE SIGNAL ;
    PORT
      LAYER metal1 ;
      RECT 0 0 0.510 0.220 ;
    END
  END p
END m349
MACRO m350
  SIZE 0.510 BY 0.301 ;
  PIN p
    DIRECTION INOUT ;
    USE SIGNAL ;
    PORT
      LAYER metal1 ;
      RECT 0 0 0.510 0.301 ;
    END
  END p
END m350
MACRO m351
  SIZE 0.510 BY 0.251 ;
  PIN p
    DIRECTION INOUT ;
    USE SIGNAL ;
    PORT
      LAYER metal1 ;
      RECT 0 0 0.510 0.251 ;
    END
  END p
END m351
MACRO m352
  SIZE 0.510 BY 0.207 ;
  PIN p
    DIRECTION INOUT ;
    USE SIGNAL ;
    PORT
      LAYER metal1 ;
      RECT 0 0 0.510 0.207 ;
    END
  END p
END m352
MACRO m353
  SIZE 0.510 BY 0.207 ;
  PIN p
    DIRECTION INOUT ;
    USE SIGNAL ;
    PORT
      LAYER metal1 ;
      RECT 0 0 0.510 0.207 ;
    END
  END p
END m353
MACRO m354
  SIZE 0.510 BY 0.220 ;
  PIN p
    DIRECTION INOUT ;
    USE SIGNAL ;
    PORT
      LAYER metal1 ;
      RECT 0 0 0.510 0.220 ;
    END
  END p
END m354
MACRO m355
  SIZE 0.510 BY 0.251 ;
  PIN p
    DIRECTION INOUT ;
    USE SIGNAL ;
    PORT
      LAYER metal1 ;
      RECT 0 0 0.510 0.251 ;
    END
  END p
END m355
MACRO m356
  SIZE 0.510 BY 0.207 ;
  PIN p
    DIRECTION INOUT ;
    USE SIGNAL ;
    PORT
      LAYER metal1 ;
      RECT 0 0 0.510 0.207 ;
    END
  END p
END m356
MACRO m357
  SIZE 0.510 BY 0.207 ;
  PIN p
    DIRECTION INOUT ;
    USE SIGNAL ;
    PORT
      LAYER metal1 ;
      RECT 0 0 0.510 0.207 ;
    END
  END p
END m357
MACRO m358
  SIZE 0.510 BY 0.207 ;
  PIN p
    DIRECTION INOUT ;
    USE SIGNAL ;
    PORT
      LAYER metal1 ;
      RECT 0 0 0.510 0.207 ;
    END
  END p
END m358
MACRO m359
  SIZE 0.510 BY 0.207 ;
  PIN p
    DIRECTION INOUT ;
    USE SIGNAL ;
    PORT
      LAYER metal1 ;
      RECT 0 0 0.510 0.207 ;
    END
  END p
END m359
MACRO m360
  SIZE 0.510 BY 0.006 ;
  PIN p
    DIRECTION INOUT ;
    USE SIGNAL ;
    PORT
      LAYER metal1 ;
      RECT 0 0 0.510 0.006 ;
    END
  END p
END m360
MACRO m361
  SIZE 0.510 BY 0.207 ;
  PIN p
    DIRECTION INOUT ;
    USE SIGNAL ;
    PORT
      LAYER metal1 ;
      RECT 0 0 0.510 0.207 ;
    END
  END p
END m361
MACRO m362
  SIZE 0.510 BY 0.220 ;
  PIN p
    DIRECTION INOUT ;
    USE SIGNAL ;
    PORT
      LAYER metal1 ;
      RECT 0 0 0.510 0.220 ;
    END
  END p
END m362
MACRO m363
  SIZE 0.510 BY 0.238 ;
  PIN p
    DIRECTION INOUT ;
    USE SIGNAL ;
    PORT
      LAYER metal1 ;
      RECT 0 0 0.510 0.238 ;
    END
  END p
END m363
MACRO m364
  SIZE 0.510 BY 0.207 ;
  PIN p
    DIRECTION INOUT ;
    USE SIGNAL ;
    PORT
      LAYER metal1 ;
      RECT 0 0 0.510 0.207 ;
    END
  END p
END m364
MACRO m365
  SIZE 0.510 BY 0.690 ;
  PIN p
    DIRECTION INOUT ;
    USE SIGNAL ;
    PORT
      LAYER metal1 ;
      RECT 0 0 0.510 0.690 ;
    END
  END p
END m365
MACRO m366
  SIZE 0.510 BY 0.207 ;
  PIN p
    DIRECTION INOUT ;
    USE SIGNAL ;
    PORT
      LAYER metal1 ;
      RECT 0 0 0.510 0.207 ;
    END
  END p
END m366
MACRO m367
  SIZE 0.510 BY 0.207 ;
  PIN p
    DIRECTION INOUT ;
    USE SIGNAL ;
    PORT
      LAYER metal1 ;
      RECT 0 0 0.510 0.207 ;
    END
  END p
END m367
MACRO m368
  SIZE 0.510 BY 0.207 ;
  PIN p
    DIRECTION INOUT ;
    USE SIGNAL ;
    PORT
      LAYER metal1 ;
      RECT 0 0 0.510 0.207 ;
    END
  END p
END m368
MACRO m369
  SIZE 0.510 BY 0.226 ;
  PIN p
    DIRECTION INOUT ;
    USE SIGNAL ;
    PORT
      LAYER metal1 ;
      RECT 0 0 0.510 0.226 ;
    END
  END p
END m369
MACRO m370
  SIZE 0.510 BY 0.207 ;
  PIN p
    DIRECTION INOUT ;
    USE SIGNAL ;
    PORT
      LAYER metal1 ;
      RECT 0 0 0.510 0.207 ;
    END
  END p
END m370
MACRO m371
  SIZE 0.510 BY 0.207 ;
  PIN p
    DIRECTION INOUT ;
    USE SIGNAL ;
    PORT
      LAYER metal1 ;
      RECT 0 0 0.510 0.207 ;
    END
  END p
END m371
MACRO m372
  SIZE 0.510 BY 0.207 ;
  PIN p
    DIRECTION INOUT ;
    USE SIGNAL ;
    PORT
      LAYER metal1 ;
      RECT 0 0 0.510 0.207 ;
    END
  END p
END m372
MACRO m373
  SIZE 0.510 BY 0.226 ;
  PIN p
    DIRECTION INOUT ;
    USE SIGNAL ;
    PORT
      LAYER metal1 ;
      RECT 0 0 0.510 0.226 ;
    END
  END p
END m373
MACRO m374
  SIZE 0.510 BY 0.207 ;
  PIN p
    DIRECTION INOUT ;
    USE SIGNAL ;
    PORT
      LAYER metal1 ;
      RECT 0 0 0.510 0.207 ;
    END
  END p
END m374
MACRO m375
  SIZE 0.510 BY 0.251 ;
  PIN p
    DIRECTION INOUT ;
    USE SIGNAL ;
    PORT
      LAYER metal1 ;
      RECT 0 0 0.510 0.251 ;
    END
  END p
END m375
MACRO m376
  SIZE 0.510 BY 0.226 ;
  PIN p
    DIRECTION INOUT ;
    USE SIGNAL ;
    PORT
      LAYER metal1 ;
      RECT 0 0 0.510 0.226 ;
    END
  END p
END m376
MACRO m377
  SIZE 0.510 BY 0.207 ;
  PIN p
    DIRECTION INOUT ;
    USE SIGNAL ;
    PORT
      LAYER metal1 ;
      RECT 0 0 0.510 0.207 ;
    END
  END p
END m377
MACRO m378
  SIZE 0.510 BY 0.207 ;
  PIN p
    DIRECTION INOUT ;
    USE SIGNAL ;
    PORT
      LAYER metal1 ;
      RECT 0 0 0.510 0.207 ;
    END
  END p
END m378
MACRO m379
  SIZE 0.510 BY 0.207 ;
  PIN p
    DIRECTION INOUT ;
    USE SIGNAL ;
    PORT
      LAYER metal1 ;
      RECT 0 0 0.510 0.207 ;
    END
  END p
END m379
MACRO m380
  SIZE 0.510 BY 0.207 ;
  PIN p
    DIRECTION INOUT ;
    USE SIGNAL ;
    PORT
      LAYER metal1 ;
      RECT 0 0 0.510 0.207 ;
    END
  END p
END m380
MACRO m381
  SIZE 0.510 BY 0.207 ;
  PIN p
    DIRECTION INOUT ;
    USE SIGNAL ;
    PORT
      LAYER metal1 ;
      RECT 0 0 0.510 0.207 ;
    END
  END p
END m381
MACRO m382
  SIZE 0.510 BY 0.452 ;
  PIN p
    DIRECTION INOUT ;
    USE SIGNAL ;
    PORT
      LAYER metal1 ;
      RECT 0 0 0.510 0.452 ;
    END
  END p
END m382
MACRO m383
  SIZE 0.510 BY 0.207 ;
  PIN p
    DIRECTION INOUT ;
    USE SIGNAL ;
    PORT
      LAYER metal1 ;
      RECT 0 0 0.510 0.207 ;
    END
  END p
END m383
MACRO m384
  SIZE 0.510 BY 0.207 ;
  PIN p
    DIRECTION INOUT ;
    USE SIGNAL ;
    PORT
      LAYER metal1 ;
      RECT 0 0 0.510 0.207 ;
    END
  END p
END m384
MACRO m385
  SIZE 0.510 BY 0.207 ;
  PIN p
    DIRECTION INOUT ;
    USE SIGNAL ;
    PORT
      LAYER metal1 ;
      RECT 0 0 0.510 0.207 ;
    END
  END p
END m385
MACRO m386
  SIZE 0.510 BY 0.207 ;
  PIN p
    DIRECTION INOUT ;
    USE SIGNAL ;
    PORT
      LAYER metal1 ;
      RECT 0 0 0.510 0.207 ;
    END
  END p
END m386
MACRO m387
  SIZE 0.510 BY 0.213 ;
  PIN p
    DIRECTION INOUT ;
    USE SIGNAL ;
    PORT
      LAYER metal1 ;
      RECT 0 0 0.510 0.213 ;
    END
  END p
END m387
MACRO m388
  SIZE 0.510 BY 0.207 ;
  PIN p
    DIRECTION INOUT ;
    USE SIGNAL ;
    PORT
      LAYER metal1 ;
      RECT 0 0 0.510 0.207 ;
    END
  END p
END m388
MACRO m389
  SIZE 0.510 BY 0.264 ;
  PIN p
    DIRECTION INOUT ;
    USE SIGNAL ;
    PORT
      LAYER metal1 ;
      RECT 0 0 0.510 0.264 ;
    END
  END p
END m389
MACRO m390
  SIZE 0.510 BY 0.207 ;
  PIN p
    DIRECTION INOUT ;
    USE SIGNAL ;
    PORT
      LAYER metal1 ;
      RECT 0 0 0.510 0.207 ;
    END
  END p
END m390
MACRO m391
  SIZE 0.510 BY 0.207 ;
  PIN p
    DIRECTION INOUT ;
    USE SIGNAL ;
    PORT
      LAYER metal1 ;
      RECT 0 0 0.510 0.207 ;
    END
  END p
END m391
MACRO m392
  SIZE 0.510 BY 0.207 ;
  PIN p
    DIRECTION INOUT ;
    USE SIGNAL ;
    PORT
      LAYER metal1 ;
      RECT 0 0 0.510 0.207 ;
    END
  END p
END m392
MACRO m393
  SIZE 0.510 BY 0.245 ;
  PIN p
    DIRECTION INOUT ;
    USE SIGNAL ;
    PORT
      LAYER metal1 ;
      RECT 0 0 0.510 0.245 ;
    END
  END p
END m393
MACRO m394
  SIZE 0.510 BY 0.251 ;
  PIN p
    DIRECTION INOUT ;
    USE SIGNAL ;
    PORT
      LAYER metal1 ;
      RECT 0 0 0.510 0.251 ;
    END
  END p
END m394
MACRO m395
  SIZE 0.510 BY 0.257 ;
  PIN p
    DIRECTION INOUT ;
    USE SIGNAL ;
    PORT
      LAYER metal1 ;
      RECT 0 0 0.510 0.257 ;
    END
  END p
END m395
MACRO m396
  SIZE 0.510 BY 0.207 ;
  PIN p
    DIRECTION INOUT ;
    USE SIGNAL ;
    PORT
      LAYER metal1 ;
      RECT 0 0 0.510 0.207 ;
    END
  END p
END m396
MACRO m397
  SIZE 0.510 BY 0.307 ;
  PIN p
    DIRECTION INOUT ;
    USE SIGNAL ;
    PORT
      LAYER metal1 ;
      RECT 0 0 0.510 0.307 ;
    END
  END p
END m397
MACRO m398
  SIZE 0.510 BY 0.207 ;
  PIN p
    DIRECTION INOUT ;
    USE SIGNAL ;
    PORT
      LAYER metal1 ;
      RECT 0 0 0.510 0.207 ;
    END
  END p
END m398
MACRO m399
  SIZE 0.510 BY 0.207 ;
  PIN p
    DIRECTION INOUT ;
    USE SIGNAL ;
    PORT
      LAYER metal1 ;
      RECT 0 0 0.510 0.207 ;
    END
  END p
END m399
MACRO m400
  SIZE 0.510 BY 0.257 ;
  PIN p
    DIRECTION INOUT ;
    USE SIGNAL ;
    PORT
      LAYER metal1 ;
      RECT 0 0 0.510 0.257 ;
    END
  END p
END m400
MACRO m401
  SIZE 0.510 BY 0.295 ;
  PIN p
    DIRECTION INOUT ;
    USE SIGNAL ;
    PORT
      LAYER metal1 ;
      RECT 0 0 0.510 0.295 ;
    END
  END p
END m401
MACRO m402
  SIZE 0.510 BY 0.207 ;
  PIN p
    DIRECTION INOUT ;
    USE SIGNAL ;
    PORT
      LAYER metal1 ;
      RECT 0 0 0.510 0.207 ;
    END
  END p
END m402
MACRO m403
  SIZE 0.510 BY 0.207 ;
  PIN p
    DIRECTION INOUT ;
    USE SIGNAL ;
    PORT
      LAYER metal1 ;
      RECT 0 0 0.510 0.207 ;
    END
  END p
END m403
MACRO m404
  SIZE 0.510 BY 0.245 ;
  PIN p
    DIRECTION INOUT ;
    USE SIGNAL ;
    PORT
      LAYER metal1 ;
      RECT 0 0 0.510 0.245 ;
    END
  END p
END m404
MACRO m405
  SIZE 0.510 BY 0.207 ;
  PIN p
    DIRECTION INOUT ;
    USE SIGNAL ;
    PORT
      LAYER metal1 ;
      RECT 0 0 0.510 0.207 ;
    END
  END p
END m405
MACRO m406
  SIZE 0.510 BY 0.295 ;
  PIN p
    DIRECTION INOUT ;
    USE SIGNAL ;
    PORT
      LAYER metal1 ;
      RECT 0 0 0.510 0.295 ;
    END
  END p
END m406
MACRO m407
  SIZE 0.510 BY 0.207 ;
  PIN p
    DIRECTION INOUT ;
    USE SIGNAL ;
    PORT
      LAYER metal1 ;
      RECT 0 0 0.510 0.207 ;
    END
  END p
END m407
MACRO m408
  SIZE 0.510 BY 0.207 ;
  PIN p
    DIRECTION INOUT ;
    USE SIGNAL ;
    PORT
      LAYER metal1 ;
      RECT 0 0 0.510 0.207 ;
    END
  END p
END m408
MACRO m409
  SIZE 0.510 BY 0.301 ;
  PIN p
    DIRECTION INOUT ;
    USE SIGNAL ;
    PORT
      LAYER metal1 ;
      RECT 0 0 0.510 0.301 ;
    END
  END p
END m409
MACRO m410
  SIZE 0.510 BY 0.251 ;
  PIN p
    DIRECTION INOUT ;
    USE SIGNAL ;
    PORT
      LAYER metal1 ;
      RECT 0 0 0.510 0.251 ;
    END
  END p
END m410
MACRO m411
  SIZE 0.510 BY 0.207 ;
  PIN p
    DIRECTION INOUT ;
    USE SIGNAL ;
    PORT
      LAYER metal1 ;
      RECT 0 0 0.510 0.207 ;
    END
  END p
END m411
MACRO m412
  SIZE 0.510 BY 0.220 ;
  PIN p
    DIRECTION INOUT ;
    USE SIGNAL ;
    PORT
      LAYER metal1 ;
      RECT 0 0 0.510 0.220 ;
    END
  END p
END m412
MACRO m413
  SIZE 0.510 BY 0.207 ;
  PIN p
    DIRECTION INOUT ;
    USE SIGNAL ;
    PORT
      LAYER metal1 ;
      RECT 0 0 0.510 0.207 ;
    END
  END p
END m413
MACRO m414
  SIZE 0.510 BY 0.270 ;
  PIN p
    DIRECTION INOUT ;
    USE SIGNAL ;
    PORT
      LAYER metal1 ;
      RECT 0 0 0.510 0.270 ;
    END
  END p
END m414
MACRO m415
  SIZE 0.510 BY 0.207 ;
  PIN p
    DIRECTION INOUT ;
    USE SIGNAL ;
    PORT
      LAYER metal1 ;
      RECT 0 0 0.510 0.207 ;
    END
  END p
END m415
MACRO m416
  SIZE 0.510 BY 0.207 ;
  PIN p
    DIRECTION INOUT ;
    USE SIGNAL ;
    PORT
      LAYER metal1 ;
      RECT 0 0 0.510 0.207 ;
    END
  END p
END m416
MACRO m417
  SIZE 0.510 BY 0.207 ;
  PIN p
    DIRECTION INOUT ;
    USE SIGNAL ;
    PORT
      LAYER metal1 ;
      RECT 0 0 0.510 0.207 ;
    END
  END p
END m417
MACRO m418
  SIZE 0.510 BY 0.207 ;
  PIN p
    DIRECTION INOUT ;
    USE SIGNAL ;
    PORT
      LAYER metal1 ;
      RECT 0 0 0.510 0.207 ;
    END
  END p
END m418
MACRO m419
  SIZE 0.510 BY 0.207 ;
  PIN p
    DIRECTION INOUT ;
    USE SIGNAL ;
    PORT
      LAYER metal1 ;
      RECT 0 0 0.510 0.207 ;
    END
  END p
END m419
MACRO m420
  SIZE 0.510 BY 0.264 ;
  PIN p
    DIRECTION INOUT ;
    USE SIGNAL ;
    PORT
      LAYER metal1 ;
      RECT 0 0 0.510 0.264 ;
    END
  END p
END m420
MACRO m421
  SIZE 0.510 BY 0.207 ;
  PIN p
    DIRECTION INOUT ;
    USE SIGNAL ;
    PORT
      LAYER metal1 ;
      RECT 0 0 0.510 0.207 ;
    END
  END p
END m421
MACRO m422
  SIZE 0.510 BY 0.257 ;
  PIN p
    DIRECTION INOUT ;
    USE SIGNAL ;
    PORT
      LAYER metal1 ;
      RECT 0 0 0.510 0.257 ;
    END
  END p
END m422
MACRO m423
  SIZE 0.510 BY 0.282 ;
  PIN p
    DIRECTION INOUT ;
    USE SIGNAL ;
    PORT
      LAYER metal1 ;
      RECT 0 0 0.510 0.282 ;
    END
  END p
END m423
MACRO m424
  SIZE 0.510 BY 0.232 ;
  PIN p
    DIRECTION INOUT ;
    USE SIGNAL ;
    PORT
      LAYER metal1 ;
      RECT 0 0 0.510 0.232 ;
    END
  END p
END m424
MACRO m425
  SIZE 0.510 BY 0.207 ;
  PIN p
    DIRECTION INOUT ;
    USE SIGNAL ;
    PORT
      LAYER metal1 ;
      RECT 0 0 0.510 0.207 ;
    END
  END p
END m425
MACRO m426
  SIZE 0.510 BY 0.207 ;
  PIN p
    DIRECTION INOUT ;
    USE SIGNAL ;
    PORT
      LAYER metal1 ;
      RECT 0 0 0.510 0.207 ;
    END
  END p
END m426
MACRO m427
  SIZE 0.510 BY 0.207 ;
  PIN p
    DIRECTION INOUT ;
    USE SIGNAL ;
    PORT
      LAYER metal1 ;
      RECT 0 0 0.510 0.207 ;
    END
  END p
END m427
MACRO m428
  SIZE 0.510 BY 0.207 ;
  PIN p
    DIRECTION INOUT ;
    USE SIGNAL ;
    PORT
      LAYER metal1 ;
      RECT 0 0 0.510 0.207 ;
    END
  END p
END m428
MACRO m429
  SIZE 0.510 BY 0.207 ;
  PIN p
    DIRECTION INOUT ;
    USE SIGNAL ;
    PORT
      LAYER metal1 ;
      RECT 0 0 0.510 0.207 ;
    END
  END p
END m429
MACRO m430
  SIZE 0.510 BY 0.207 ;
  PIN p
    DIRECTION INOUT ;
    USE SIGNAL ;
    PORT
      LAYER metal1 ;
      RECT 0 0 0.510 0.207 ;
    END
  END p
END m430
MACRO m431
  SIZE 0.510 BY 0.207 ;
  PIN p
    DIRECTION INOUT ;
    USE SIGNAL ;
    PORT
      LAYER metal1 ;
      RECT 0 0 0.510 0.207 ;
    END
  END p
END m431
MACRO m432
  SIZE 0.510 BY 0.207 ;
  PIN p
    DIRECTION INOUT ;
    USE SIGNAL ;
    PORT
      LAYER metal1 ;
      RECT 0 0 0.510 0.207 ;
    END
  END p
END m432
MACRO m433
  SIZE 0.510 BY 0.602 ;
  PIN p
    DIRECTION INOUT ;
    USE SIGNAL ;
    PORT
      LAYER metal1 ;
      RECT 0 0 0.510 0.602 ;
    END
  END p
END m433
MACRO m434
  SIZE 0.510 BY 0.207 ;
  PIN p
    DIRECTION INOUT ;
    USE SIGNAL ;
    PORT
      LAYER metal1 ;
      RECT 0 0 0.510 0.207 ;
    END
  END p
END m434
MACRO m435
  SIZE 0.510 BY 0.276 ;
  PIN p
    DIRECTION INOUT ;
    USE SIGNAL ;
    PORT
      LAYER metal1 ;
      RECT 0 0 0.510 0.276 ;
    END
  END p
END m435
MACRO m436
  SIZE 0.510 BY 0.207 ;
  PIN p
    DIRECTION INOUT ;
    USE SIGNAL ;
    PORT
      LAYER metal1 ;
      RECT 0 0 0.510 0.207 ;
    END
  END p
END m436
MACRO m437
  SIZE 0.510 BY 0.207 ;
  PIN p
    DIRECTION INOUT ;
    USE SIGNAL ;
    PORT
      LAYER metal1 ;
      RECT 0 0 0.510 0.207 ;
    END
  END p
END m437
MACRO m438
  SIZE 0.510 BY 0.207 ;
  PIN p
    DIRECTION INOUT ;
    USE SIGNAL ;
    PORT
      LAYER metal1 ;
      RECT 0 0 0.510 0.207 ;
    END
  END p
END m438
MACRO m439
  SIZE 0.510 BY 0.207 ;
  PIN p
    DIRECTION INOUT ;
    USE SIGNAL ;
    PORT
      LAYER metal1 ;
      RECT 0 0 0.510 0.207 ;
    END
  END p
END m439
MACRO m440
  SIZE 0.510 BY 0.207 ;
  PIN p
    DIRECTION INOUT ;
    USE SIGNAL ;
    PORT
      LAYER metal1 ;
      RECT 0 0 0.510 0.207 ;
    END
  END p
END m440
MACRO m441
  SIZE 0.510 BY 0.207 ;
  PIN p
    DIRECTION INOUT ;
    USE SIGNAL ;
    PORT
      LAYER metal1 ;
      RECT 0 0 0.510 0.207 ;
    END
  END p
END m441
MACRO m442
  SIZE 0.510 BY 0.207 ;
  PIN p
    DIRECTION INOUT ;
    USE SIGNAL ;
    PORT
      LAYER metal1 ;
      RECT 0 0 0.510 0.207 ;
    END
  END p
END m442
MACRO m443
  SIZE 0.510 BY 0.264 ;
  PIN p
    DIRECTION INOUT ;
    USE SIGNAL ;
    PORT
      LAYER metal1 ;
      RECT 0 0 0.510 0.264 ;
    END
  END p
END m443
MACRO m444
  SIZE 0.510 BY 0.257 ;
  PIN p
    DIRECTION INOUT ;
    USE SIGNAL ;
    PORT
      LAYER metal1 ;
      RECT 0 0 0.510 0.257 ;
    END
  END p
END m444
MACRO m445
  SIZE 0.510 BY 0.207 ;
  PIN p
    DIRECTION INOUT ;
    USE SIGNAL ;
    PORT
      LAYER metal1 ;
      RECT 0 0 0.510 0.207 ;
    END
  END p
END m445
MACRO m446
  SIZE 0.510 BY 0.207 ;
  PIN p
    DIRECTION INOUT ;
    USE SIGNAL ;
    PORT
      LAYER metal1 ;
      RECT 0 0 0.510 0.207 ;
    END
  END p
END m446
MACRO m447
  SIZE 0.510 BY 0.245 ;
  PIN p
    DIRECTION INOUT ;
    USE SIGNAL ;
    PORT
      LAYER metal1 ;
      RECT 0 0 0.510 0.245 ;
    END
  END p
END m447
MACRO m448
  SIZE 0.510 BY 0.207 ;
  PIN p
    DIRECTION INOUT ;
    USE SIGNAL ;
    PORT
      LAYER metal1 ;
      RECT 0 0 0.510 0.207 ;
    END
  END p
END m448
MACRO m449
  SIZE 0.510 BY 0.207 ;
  PIN p
    DIRECTION INOUT ;
    USE SIGNAL ;
    PORT
      LAYER metal1 ;
      RECT 0 0 0.510 0.207 ;
    END
  END p
END m449
MACRO m450
  SIZE 0.510 BY 0.207 ;
  PIN p
    DIRECTION INOUT ;
    USE SIGNAL ;
    PORT
      LAYER metal1 ;
      RECT 0 0 0.510 0.207 ;
    END
  END p
END m450
MACRO m451
  SIZE 0.510 BY 0.207 ;
  PIN p
    DIRECTION INOUT ;
    USE SIGNAL ;
    PORT
      LAYER metal1 ;
      RECT 0 0 0.510 0.207 ;
    END
  END p
END m451
MACRO m452
  SIZE 0.510 BY 0.207 ;
  PIN p
    DIRECTION INOUT ;
    USE SIGNAL ;
    PORT
      LAYER metal1 ;
      RECT 0 0 0.510 0.207 ;
    END
  END p
END m452
MACRO m453
  SIZE 0.510 BY 0.207 ;
  PIN p
    DIRECTION INOUT ;
    USE SIGNAL ;
    PORT
      LAYER metal1 ;
      RECT 0 0 0.510 0.207 ;
    END
  END p
END m453
MACRO m454
  SIZE 0.510 BY 0.282 ;
  PIN p
    DIRECTION INOUT ;
    USE SIGNAL ;
    PORT
      LAYER metal1 ;
      RECT 0 0 0.510 0.282 ;
    END
  END p
END m454
MACRO m455
  SIZE 0.510 BY 0.207 ;
  PIN p
    DIRECTION INOUT ;
    USE SIGNAL ;
    PORT
      LAYER metal1 ;
      RECT 0 0 0.510 0.207 ;
    END
  END p
END m455
MACRO m456
  SIZE 0.510 BY 0.207 ;
  PIN p
    DIRECTION INOUT ;
    USE SIGNAL ;
    PORT
      LAYER metal1 ;
      RECT 0 0 0.510 0.207 ;
    END
  END p
END m456
MACRO m457
  SIZE 0.510 BY 0.207 ;
  PIN p
    DIRECTION INOUT ;
    USE SIGNAL ;
    PORT
      LAYER metal1 ;
      RECT 0 0 0.510 0.207 ;
    END
  END p
END m457
MACRO m458
  SIZE 0.510 BY 0.207 ;
  PIN p
    DIRECTION INOUT ;
    USE SIGNAL ;
    PORT
      LAYER metal1 ;
      RECT 0 0 0.510 0.207 ;
    END
  END p
END m458
MACRO m459
  SIZE 0.510 BY 0.207 ;
  PIN p
    DIRECTION INOUT ;
    USE SIGNAL ;
    PORT
      LAYER metal1 ;
      RECT 0 0 0.510 0.207 ;
    END
  END p
END m459
MACRO m460
  SIZE 0.510 BY 0.207 ;
  PIN p
    DIRECTION INOUT ;
    USE SIGNAL ;
    PORT
      LAYER metal1 ;
      RECT 0 0 0.510 0.207 ;
    END
  END p
END m460
MACRO m461
  SIZE 0.510 BY 0.207 ;
  PIN p
    DIRECTION INOUT ;
    USE SIGNAL ;
    PORT
      LAYER metal1 ;
      RECT 0 0 0.510 0.207 ;
    END
  END p
END m461
MACRO m462
  SIZE 0.510 BY 0.207 ;
  PIN p
    DIRECTION INOUT ;
    USE SIGNAL ;
    PORT
      LAYER metal1 ;
      RECT 0 0 0.510 0.207 ;
    END
  END p
END m462
MACRO m463
  SIZE 0.510 BY 0.307 ;
  PIN p
    DIRECTION INOUT ;
    USE SIGNAL ;
    PORT
      LAYER metal1 ;
      RECT 0 0 0.510 0.307 ;
    END
  END p
END m463
MACRO m464
  SIZE 0.510 BY 0.207 ;
  PIN p
    DIRECTION INOUT ;
    USE SIGNAL ;
    PORT
      LAYER metal1 ;
      RECT 0 0 0.510 0.207 ;
    END
  END p
END m464
MACRO m465
  SIZE 0.510 BY 0.226 ;
  PIN p
    DIRECTION INOUT ;
    USE SIGNAL ;
    PORT
      LAYER metal1 ;
      RECT 0 0 0.510 0.226 ;
    END
  END p
END m465
MACRO m466
  SIZE 0.510 BY 0.257 ;
  PIN p
    DIRECTION INOUT ;
    USE SIGNAL ;
    PORT
      LAYER metal1 ;
      RECT 0 0 0.510 0.257 ;
    END
  END p
END m466
MACRO m467
  SIZE 0.510 BY 0.207 ;
  PIN p
    DIRECTION INOUT ;
    USE SIGNAL ;
    PORT
      LAYER metal1 ;
      RECT 0 0 0.510 0.207 ;
    END
  END p
END m467
MACRO m468
  SIZE 0.510 BY 0.289 ;
  PIN p
    DIRECTION INOUT ;
    USE SIGNAL ;
    PORT
      LAYER metal1 ;
      RECT 0 0 0.510 0.289 ;
    END
  END p
END m468
MACRO m469
  SIZE 0.510 BY 0.207 ;
  PIN p
    DIRECTION INOUT ;
    USE SIGNAL ;
    PORT
      LAYER metal1 ;
      RECT 0 0 0.510 0.207 ;
    END
  END p
END m469
MACRO m470
  SIZE 0.510 BY 1.161 ;
  PIN p
    DIRECTION INOUT ;
    USE SIGNAL ;
    PORT
      LAYER metal1 ;
      RECT 0 0 0.510 1.161 ;
    END
  END p
END m470
MACRO m471
  SIZE 0.510 BY 0.207 ;
  PIN p
    DIRECTION INOUT ;
    USE SIGNAL ;
    PORT
      LAYER metal1 ;
      RECT 0 0 0.510 0.207 ;
    END
  END p
END m471
MACRO m472
  SIZE 0.510 BY 0.207 ;
  PIN p
    DIRECTION INOUT ;
    USE SIGNAL ;
    PORT
      LAYER metal1 ;
      RECT 0 0 0.510 0.207 ;
    END
  END p
END m472
MACRO m473
  SIZE 0.510 BY 0.301 ;
  PIN p
    DIRECTION INOUT ;
    USE SIGNAL ;
    PORT
      LAYER metal1 ;
      RECT 0 0 0.510 0.301 ;
    END
  END p
END m473
MACRO m474
  SIZE 0.510 BY 0.013 ;
  PIN p
    DIRECTION INOUT ;
    USE SIGNAL ;
    PORT
      LAYER metal1 ;
      RECT 0 0 0.510 0.013 ;
    END
  END p
END m474
MACRO m475
  SIZE 0.510 BY 0.013 ;
  PIN p
    DIRECTION INOUT ;
    USE SIGNAL ;
    PORT
      LAYER metal1 ;
      RECT 0 0 0.510 0.013 ;
    END
  END p
END m475
MACRO m476
  SIZE 0.510 BY 0.496 ;
  PIN p
    DIRECTION INOUT ;
    USE SIGNAL ;
    PORT
      LAYER metal1 ;
      RECT 0 0 0.510 0.496 ;
    END
  END p
END m476
MACRO m477
  SIZE 0.510 BY 0.050 ;
  PIN p
    DIRECTION INOUT ;
    USE SIGNAL ;
    PORT
      LAYER metal1 ;
      RECT 0 0 0.510 0.050 ;
    END
  END p
END m477
MACRO m478
  SIZE 0.510 BY 0.088 ;
  PIN p
    DIRECTION INOUT ;
    USE SIGNAL ;
    PORT
      LAYER metal1 ;
      RECT 0 0 0.510 0.088 ;
    END
  END p
END m478
MACRO m479
  SIZE 0.510 BY 0.326 ;
  PIN p
    DIRECTION INOUT ;
    USE SIGNAL ;
    PORT
      LAYER metal1 ;
      RECT 0 0 0.510 0.326 ;
    END
  END p
END m479
MACRO m480
  SIZE 0.510 BY 0.339 ;
  PIN p
    DIRECTION INOUT ;
    USE SIGNAL ;
    PORT
      LAYER metal1 ;
      RECT 0 0 0.510 0.339 ;
    END
  END p
END m480
MACRO m481
  SIZE 0.510 BY 0.257 ;
  PIN p
    DIRECTION INOUT ;
    USE SIGNAL ;
    PORT
      LAYER metal1 ;
      RECT 0 0 0.510 0.257 ;
    END
  END p
END m481
MACRO m482
  SIZE 0.510 BY 0.094 ;
  PIN p
    DIRECTION INOUT ;
    USE SIGNAL ;
    PORT
      LAYER metal1 ;
      RECT 0 0 0.510 0.094 ;
    END
  END p
END m482
MACRO m483
  SIZE 0.510 BY 0.326 ;
  PIN p
    DIRECTION INOUT ;
    USE SIGNAL ;
    PORT
      LAYER metal1 ;
      RECT 0 0 0.510 0.326 ;
    END
  END p
END m483
MACRO m484
  SIZE 0.510 BY 0.063 ;
  PIN p
    DIRECTION INOUT ;
    USE SIGNAL ;
    PORT
      LAYER metal1 ;
      RECT 0 0 0.510 0.063 ;
    END
  END p
END m484
MACRO m485
  SIZE 0.510 BY 0.176 ;
  PIN p
    DIRECTION INOUT ;
    USE SIGNAL ;
    PORT
      LAYER metal1 ;
      RECT 0 0 0.510 0.176 ;
    END
  END p
END m485
MACRO m486
  SIZE 0.510 BY 0.056 ;
  PIN p
    DIRECTION INOUT ;
    USE SIGNAL ;
    PORT
      LAYER metal1 ;
      RECT 0 0 0.510 0.056 ;
    END
  END p
END m486
MACRO m487
  SIZE 0.510 BY 0.094 ;
  PIN p
    DIRECTION INOUT ;
    USE SIGNAL ;
    PORT
      LAYER metal1 ;
      RECT 0 0 0.510 0.094 ;
    END
  END p
END m487
MACRO m488
  SIZE 0.510 BY 0.013 ;
  PIN p
    DIRECTION INOUT ;
    USE SIGNAL ;
    PORT
      LAYER metal1 ;
      RECT 0 0 0.510 0.013 ;
    END
  END p
END m488
MACRO m489
  SIZE 0.510 BY 0.671 ;
  PIN p
    DIRECTION INOUT ;
    USE SIGNAL ;
    PORT
      LAYER metal1 ;
      RECT 0 0 0.510 0.671 ;
    END
  END p
END m489
MACRO m490
  SIZE 0.510 BY 0.019 ;
  PIN p
    DIRECTION INOUT ;
    USE SIGNAL ;
    PORT
      LAYER metal1 ;
      RECT 0 0 0.510 0.019 ;
    END
  END p
END m490
MACRO m491
  SIZE 0.510 BY 0.565 ;
  PIN p
    DIRECTION INOUT ;
    USE SIGNAL ;
    PORT
      LAYER metal1 ;
      RECT 0 0 0.510 0.565 ;
    END
  END p
END m491
MACRO m492
  SIZE 0.510 BY 0.358 ;
  PIN p
    DIRECTION INOUT ;
    USE SIGNAL ;
    PORT
      LAYER metal1 ;
      RECT 0 0 0.510 0.358 ;
    END
  END p
END m492
MACRO m493
  SIZE 0.510 BY 0.050 ;
  PIN p
    DIRECTION INOUT ;
    USE SIGNAL ;
    PORT
      LAYER metal1 ;
      RECT 0 0 0.510 0.050 ;
    END
  END p
END m493
MACRO m494
  SIZE 0.510 BY 0.232 ;
  PIN p
    DIRECTION INOUT ;
    USE SIGNAL ;
    PORT
      LAYER metal1 ;
      RECT 0 0 0.510 0.232 ;
    END
  END p
END m494
MACRO m495
  SIZE 0.510 BY 0.082 ;
  PIN p
    DIRECTION INOUT ;
    USE SIGNAL ;
    PORT
      LAYER metal1 ;
      RECT 0 0 0.510 0.082 ;
    END
  END p
END m495
MACRO m496
  SIZE 0.510 BY 0.238 ;
  PIN p
    DIRECTION INOUT ;
    USE SIGNAL ;
    PORT
      LAYER metal1 ;
      RECT 0 0 0.510 0.238 ;
    END
  END p
END m496
MACRO m497
  SIZE 0.510 BY 0.144 ;
  PIN p
    DIRECTION INOUT ;
    USE SIGNAL ;
    PORT
      LAYER metal1 ;
      RECT 0 0 0.510 0.144 ;
    END
  END p
END m497
MACRO m498
  SIZE 0.510 BY 0.056 ;
  PIN p
    DIRECTION INOUT ;
    USE SIGNAL ;
    PORT
      LAYER metal1 ;
      RECT 0 0 0.510 0.056 ;
    END
  END p
END m498
MACRO m499
  SIZE 0.510 BY 0.220 ;
  PIN p
    DIRECTION INOUT ;
    USE SIGNAL ;
    PORT
      LAYER metal1 ;
      RECT 0 0 0.510 0.220 ;
    END
  END p
END m499
MACRO m500
  SIZE 0.510 BY 0.383 ;
  PIN p
    DIRECTION INOUT ;
    USE SIGNAL ;
    PORT
      LAYER metal1 ;
      RECT 0 0 0.510 0.383 ;
    END
  END p
END m500
MACRO m501
  SIZE 0.510 BY 0.320 ;
  PIN p
    DIRECTION INOUT ;
    USE SIGNAL ;
    PORT
      LAYER metal1 ;
      RECT 0 0 0.510 0.320 ;
    END
  END p
END m501
MACRO m502
  SIZE 0.510 BY 0.056 ;
  PIN p
    DIRECTION INOUT ;
    USE SIGNAL ;
    PORT
      LAYER metal1 ;
      RECT 0 0 0.510 0.056 ;
    END
  END p
END m502
MACRO m503
  SIZE 0.510 BY 0.207 ;
  PIN p
    DIRECTION INOUT ;
    USE SIGNAL ;
    PORT
      LAYER metal1 ;
      RECT 0 0 0.510 0.207 ;
    END
  END p
END m503
MACRO m504
  SIZE 0.510 BY 0.201 ;
  PIN p
    DIRECTION INOUT ;
    USE SIGNAL ;
    PORT
      LAYER metal1 ;
      RECT 0 0 0.510 0.201 ;
    END
  END p
END m504
MACRO m505
  SIZE 0.510 BY 0.132 ;
  PIN p
    DIRECTION INOUT ;
    USE SIGNAL ;
    PORT
      LAYER metal1 ;
      RECT 0 0 0.510 0.132 ;
    END
  END p
END m505
MACRO m506
  SIZE 0.510 BY 0.289 ;
  PIN p
    DIRECTION INOUT ;
    USE SIGNAL ;
    PORT
      LAYER metal1 ;
      RECT 0 0 0.510 0.289 ;
    END
  END p
END m506
MACRO m507
  SIZE 0.510 BY 0.427 ;
  PIN p
    DIRECTION INOUT ;
    USE SIGNAL ;
    PORT
      LAYER metal1 ;
      RECT 0 0 0.510 0.427 ;
    END
  END p
END m507
MACRO m508
  SIZE 0.510 BY 0.471 ;
  PIN p
    DIRECTION INOUT ;
    USE SIGNAL ;
    PORT
      LAYER metal1 ;
      RECT 0 0 0.510 0.471 ;
    END
  END p
END m508
MACRO m509
  SIZE 0.510 BY 0.207 ;
  PIN p
    DIRECTION INOUT ;
    USE SIGNAL ;
    PORT
      LAYER metal1 ;
      RECT 0 0 0.510 0.207 ;
    END
  END p
END m509
MACRO m510
  SIZE 0.510 BY 0.113 ;
  PIN p
    DIRECTION INOUT ;
    USE SIGNAL ;
    PORT
      LAYER metal1 ;
      RECT 0 0 0.510 0.113 ;
    END
  END p
END m510
MACRO m511
  SIZE 0.510 BY 0.125 ;
  PIN p
    DIRECTION INOUT ;
    USE SIGNAL ;
    PORT
      LAYER metal1 ;
      RECT 0 0 0.510 0.125 ;
    END
  END p
END m511
MACRO m512
  SIZE 0.510 BY 0.220 ;
  PIN p
    DIRECTION INOUT ;
    USE SIGNAL ;
    PORT
      LAYER metal1 ;
      RECT 0 0 0.510 0.220 ;
    END
  END p
END m512
MACRO m513
  SIZE 0.510 BY 0.125 ;
  PIN p
    DIRECTION INOUT ;
    USE SIGNAL ;
    PORT
      LAYER metal1 ;
      RECT 0 0 0.510 0.125 ;
    END
  END p
END m513
MACRO m514
  SIZE 0.510 BY 0.257 ;
  PIN p
    DIRECTION INOUT ;
    USE SIGNAL ;
    PORT
      LAYER metal1 ;
      RECT 0 0 0.510 0.257 ;
    END
  END p
END m514
MACRO m515
  SIZE 0.510 BY 0.301 ;
  PIN p
    DIRECTION INOUT ;
    USE SIGNAL ;
    PORT
      LAYER metal1 ;
      RECT 0 0 0.510 0.301 ;
    END
  END p
END m515
MACRO m516
  SIZE 0.510 BY 0.414 ;
  PIN p
    DIRECTION INOUT ;
    USE SIGNAL ;
    PORT
      LAYER metal1 ;
      RECT 0 0 0.510 0.414 ;
    END
  END p
END m516
MACRO m517
  SIZE 0.510 BY 0.471 ;
  PIN p
    DIRECTION INOUT ;
    USE SIGNAL ;
    PORT
      LAYER metal1 ;
      RECT 0 0 0.510 0.471 ;
    END
  END p
END m517
MACRO m518
  SIZE 0.510 BY 0.370 ;
  PIN p
    DIRECTION INOUT ;
    USE SIGNAL ;
    PORT
      LAYER metal1 ;
      RECT 0 0 0.510 0.370 ;
    END
  END p
END m518
MACRO m519
  SIZE 0.510 BY 0.264 ;
  PIN p
    DIRECTION INOUT ;
    USE SIGNAL ;
    PORT
      LAYER metal1 ;
      RECT 0 0 0.510 0.264 ;
    END
  END p
END m519
MACRO m520
  SIZE 0.510 BY 0.326 ;
  PIN p
    DIRECTION INOUT ;
    USE SIGNAL ;
    PORT
      LAYER metal1 ;
      RECT 0 0 0.510 0.326 ;
    END
  END p
END m520
MACRO m521
  SIZE 0.510 BY 0.050 ;
  PIN p
    DIRECTION INOUT ;
    USE SIGNAL ;
    PORT
      LAYER metal1 ;
      RECT 0 0 0.510 0.050 ;
    END
  END p
END m521
MACRO m522
  SIZE 0.510 BY 0.301 ;
  PIN p
    DIRECTION INOUT ;
    USE SIGNAL ;
    PORT
      LAYER metal1 ;
      RECT 0 0 0.510 0.301 ;
    END
  END p
END m522
MACRO m523
  SIZE 0.510 BY 0.326 ;
  PIN p
    DIRECTION INOUT ;
    USE SIGNAL ;
    PORT
      LAYER metal1 ;
      RECT 0 0 0.510 0.326 ;
    END
  END p
END m523
MACRO m524
  SIZE 0.510 BY 0.326 ;
  PIN p
    DIRECTION INOUT ;
    USE SIGNAL ;
    PORT
      LAYER metal1 ;
      RECT 0 0 0.510 0.326 ;
    END
  END p
END m524
MACRO m525
  SIZE 0.510 BY 0.314 ;
  PIN p
    DIRECTION INOUT ;
    USE SIGNAL ;
    PORT
      LAYER metal1 ;
      RECT 0 0 0.510 0.314 ;
    END
  END p
END m525
MACRO m526
  SIZE 0.510 BY 0.201 ;
  PIN p
    DIRECTION INOUT ;
    USE SIGNAL ;
    PORT
      LAYER metal1 ;
      RECT 0 0 0.510 0.201 ;
    END
  END p
END m526
MACRO m527
  SIZE 0.510 BY 0.527 ;
  PIN p
    DIRECTION INOUT ;
    USE SIGNAL ;
    PORT
      LAYER metal1 ;
      RECT 0 0 0.510 0.527 ;
    END
  END p
END m527
MACRO m528
  SIZE 0.510 BY 0.389 ;
  PIN p
    DIRECTION INOUT ;
    USE SIGNAL ;
    PORT
      LAYER metal1 ;
      RECT 0 0 0.510 0.389 ;
    END
  END p
END m528
MACRO m529
  SIZE 0.510 BY 0.477 ;
  PIN p
    DIRECTION INOUT ;
    USE SIGNAL ;
    PORT
      LAYER metal1 ;
      RECT 0 0 0.510 0.477 ;
    END
  END p
END m529
MACRO m530
  SIZE 0.510 BY 0.238 ;
  PIN p
    DIRECTION INOUT ;
    USE SIGNAL ;
    PORT
      LAYER metal1 ;
      RECT 0 0 0.510 0.238 ;
    END
  END p
END m530
MACRO m531
  SIZE 0.510 BY 0.791 ;
  PIN p
    DIRECTION INOUT ;
    USE SIGNAL ;
    PORT
      LAYER metal1 ;
      RECT 0 0 0.510 0.791 ;
    END
  END p
END m531
MACRO m532
  SIZE 0.510 BY 0.364 ;
  PIN p
    DIRECTION INOUT ;
    USE SIGNAL ;
    PORT
      LAYER metal1 ;
      RECT 0 0 0.510 0.364 ;
    END
  END p
END m532
MACRO m533
  SIZE 0.510 BY 0.082 ;
  PIN p
    DIRECTION INOUT ;
    USE SIGNAL ;
    PORT
      LAYER metal1 ;
      RECT 0 0 0.510 0.082 ;
    END
  END p
END m533
MACRO m534
  SIZE 0.510 BY 0.301 ;
  PIN p
    DIRECTION INOUT ;
    USE SIGNAL ;
    PORT
      LAYER metal1 ;
      RECT 0 0 0.510 0.301 ;
    END
  END p
END m534
MACRO m535
  SIZE 0.510 BY 0.125 ;
  PIN p
    DIRECTION INOUT ;
    USE SIGNAL ;
    PORT
      LAYER metal1 ;
      RECT 0 0 0.510 0.125 ;
    END
  END p
END m535
MACRO m536
  SIZE 0.510 BY 0.264 ;
  PIN p
    DIRECTION INOUT ;
    USE SIGNAL ;
    PORT
      LAYER metal1 ;
      RECT 0 0 0.510 0.264 ;
    END
  END p
END m536
MACRO m537
  SIZE 0.510 BY 0.602 ;
  PIN p
    DIRECTION INOUT ;
    USE SIGNAL ;
    PORT
      LAYER metal1 ;
      RECT 0 0 0.510 0.602 ;
    END
  END p
END m537
MACRO m538
  SIZE 0.510 BY 0.264 ;
  PIN p
    DIRECTION INOUT ;
    USE SIGNAL ;
    PORT
      LAYER metal1 ;
      RECT 0 0 0.510 0.264 ;
    END
  END p
END m538
MACRO m539
  SIZE 0.510 BY 0.345 ;
  PIN p
    DIRECTION INOUT ;
    USE SIGNAL ;
    PORT
      LAYER metal1 ;
      RECT 0 0 0.510 0.345 ;
    END
  END p
END m539
MACRO m540
  SIZE 0.510 BY 0.640 ;
  PIN p
    DIRECTION INOUT ;
    USE SIGNAL ;
    PORT
      LAYER metal1 ;
      RECT 0 0 0.510 0.640 ;
    END
  END p
END m540
MACRO m541
  SIZE 0.510 BY 0.276 ;
  PIN p
    DIRECTION INOUT ;
    USE SIGNAL ;
    PORT
      LAYER metal1 ;
      RECT 0 0 0.510 0.276 ;
    END
  END p
END m541
MACRO m542
  SIZE 0.510 BY 0.245 ;
  PIN p
    DIRECTION INOUT ;
    USE SIGNAL ;
    PORT
      LAYER metal1 ;
      RECT 0 0 0.510 0.245 ;
    END
  END p
END m542
MACRO m543
  SIZE 0.510 BY 0.370 ;
  PIN p
    DIRECTION INOUT ;
    USE SIGNAL ;
    PORT
      LAYER metal1 ;
      RECT 0 0 0.510 0.370 ;
    END
  END p
END m543
MACRO m544
  SIZE 0.510 BY 0.320 ;
  PIN p
    DIRECTION INOUT ;
    USE SIGNAL ;
    PORT
      LAYER metal1 ;
      RECT 0 0 0.510 0.320 ;
    END
  END p
END m544
MACRO m545
  SIZE 0.510 BY 0.320 ;
  PIN p
    DIRECTION INOUT ;
    USE SIGNAL ;
    PORT
      LAYER metal1 ;
      RECT 0 0 0.510 0.320 ;
    END
  END p
END m545
MACRO m546
  SIZE 0.510 BY 0.295 ;
  PIN p
    DIRECTION INOUT ;
    USE SIGNAL ;
    PORT
      LAYER metal1 ;
      RECT 0 0 0.510 0.295 ;
    END
  END p
END m546
MACRO m547
  SIZE 0.510 BY 0.427 ;
  PIN p
    DIRECTION INOUT ;
    USE SIGNAL ;
    PORT
      LAYER metal1 ;
      RECT 0 0 0.510 0.427 ;
    END
  END p
END m547
MACRO m548
  SIZE 0.510 BY 0.502 ;
  PIN p
    DIRECTION INOUT ;
    USE SIGNAL ;
    PORT
      LAYER metal1 ;
      RECT 0 0 0.510 0.502 ;
    END
  END p
END m548
MACRO m549
  SIZE 0.510 BY 0.326 ;
  PIN p
    DIRECTION INOUT ;
    USE SIGNAL ;
    PORT
      LAYER metal1 ;
      RECT 0 0 0.510 0.326 ;
    END
  END p
END m549
MACRO m550
  SIZE 0.510 BY 0.094 ;
  PIN p
    DIRECTION INOUT ;
    USE SIGNAL ;
    PORT
      LAYER metal1 ;
      RECT 0 0 0.510 0.094 ;
    END
  END p
END m550
MACRO m551
  SIZE 0.510 BY 0.602 ;
  PIN p
    DIRECTION INOUT ;
    USE SIGNAL ;
    PORT
      LAYER metal1 ;
      RECT 0 0 0.510 0.602 ;
    END
  END p
END m551
MACRO m552
  SIZE 0.510 BY 0.320 ;
  PIN p
    DIRECTION INOUT ;
    USE SIGNAL ;
    PORT
      LAYER metal1 ;
      RECT 0 0 0.510 0.320 ;
    END
  END p
END m552
MACRO m553
  SIZE 0.510 BY 0.251 ;
  PIN p
    DIRECTION INOUT ;
    USE SIGNAL ;
    PORT
      LAYER metal1 ;
      RECT 0 0 0.510 0.251 ;
    END
  END p
END m553
MACRO m554
  SIZE 0.510 BY 0.201 ;
  PIN p
    DIRECTION INOUT ;
    USE SIGNAL ;
    PORT
      LAYER metal1 ;
      RECT 0 0 0.510 0.201 ;
    END
  END p
END m554
MACRO m555
  SIZE 0.510 BY 0.527 ;
  PIN p
    DIRECTION INOUT ;
    USE SIGNAL ;
    PORT
      LAYER metal1 ;
      RECT 0 0 0.510 0.527 ;
    END
  END p
END m555
MACRO m556
  SIZE 0.510 BY 0.238 ;
  PIN p
    DIRECTION INOUT ;
    USE SIGNAL ;
    PORT
      LAYER metal1 ;
      RECT 0 0 0.510 0.238 ;
    END
  END p
END m556
MACRO m557
  SIZE 0.510 BY 0.301 ;
  PIN p
    DIRECTION INOUT ;
    USE SIGNAL ;
    PORT
      LAYER metal1 ;
      RECT 0 0 0.510 0.301 ;
    END
  END p
END m557
MACRO m558
  SIZE 0.510 BY 0.370 ;
  PIN p
    DIRECTION INOUT ;
    USE SIGNAL ;
    PORT
      LAYER metal1 ;
      RECT 0 0 0.510 0.370 ;
    END
  END p
END m558
MACRO m559
  SIZE 0.510 BY 0.552 ;
  PIN p
    DIRECTION INOUT ;
    USE SIGNAL ;
    PORT
      LAYER metal1 ;
      RECT 0 0 0.510 0.552 ;
    END
  END p
END m559
MACRO m560
  SIZE 0.510 BY 0.445 ;
  PIN p
    DIRECTION INOUT ;
    USE SIGNAL ;
    PORT
      LAYER metal1 ;
      RECT 0 0 0.510 0.445 ;
    END
  END p
END m560
MACRO m561
  SIZE 0.510 BY 0.558 ;
  PIN p
    DIRECTION INOUT ;
    USE SIGNAL ;
    PORT
      LAYER metal1 ;
      RECT 0 0 0.510 0.558 ;
    END
  END p
END m561
MACRO m562
  SIZE 0.510 BY 0.496 ;
  PIN p
    DIRECTION INOUT ;
    USE SIGNAL ;
    PORT
      LAYER metal1 ;
      RECT 0 0 0.510 0.496 ;
    END
  END p
END m562
MACRO m563
  SIZE 0.510 BY 0.100 ;
  PIN p
    DIRECTION INOUT ;
    USE SIGNAL ;
    PORT
      LAYER metal1 ;
      RECT 0 0 0.510 0.100 ;
    END
  END p
END m563
MACRO m564
  SIZE 0.510 BY 0.376 ;
  PIN p
    DIRECTION INOUT ;
    USE SIGNAL ;
    PORT
      LAYER metal1 ;
      RECT 0 0 0.510 0.376 ;
    END
  END p
END m564
MACRO m565
  SIZE 0.510 BY 0.220 ;
  PIN p
    DIRECTION INOUT ;
    USE SIGNAL ;
    PORT
      LAYER metal1 ;
      RECT 0 0 0.510 0.220 ;
    END
  END p
END m565
MACRO m566
  SIZE 0.510 BY 0.351 ;
  PIN p
    DIRECTION INOUT ;
    USE SIGNAL ;
    PORT
      LAYER metal1 ;
      RECT 0 0 0.510 0.351 ;
    END
  END p
END m566
MACRO m567
  SIZE 0.510 BY 0.113 ;
  PIN p
    DIRECTION INOUT ;
    USE SIGNAL ;
    PORT
      LAYER metal1 ;
      RECT 0 0 0.510 0.113 ;
    END
  END p
END m567
MACRO m568
  SIZE 0.510 BY 0.333 ;
  PIN p
    DIRECTION INOUT ;
    USE SIGNAL ;
    PORT
      LAYER metal1 ;
      RECT 0 0 0.510 0.333 ;
    END
  END p
END m568
MACRO m569
  SIZE 0.510 BY 0.445 ;
  PIN p
    DIRECTION INOUT ;
    USE SIGNAL ;
    PORT
      LAYER metal1 ;
      RECT 0 0 0.510 0.445 ;
    END
  END p
END m569
MACRO m570
  SIZE 0.510 BY 0.427 ;
  PIN p
    DIRECTION INOUT ;
    USE SIGNAL ;
    PORT
      LAYER metal1 ;
      RECT 0 0 0.510 0.427 ;
    END
  END p
END m570
MACRO m571
  SIZE 0.510 BY 0.540 ;
  PIN p
    DIRECTION INOUT ;
    USE SIGNAL ;
    PORT
      LAYER metal1 ;
      RECT 0 0 0.510 0.540 ;
    END
  END p
END m571
MACRO m572
  SIZE 0.510 BY 0.389 ;
  PIN p
    DIRECTION INOUT ;
    USE SIGNAL ;
    PORT
      LAYER metal1 ;
      RECT 0 0 0.510 0.389 ;
    END
  END p
END m572
MACRO m573
  SIZE 0.510 BY 0.351 ;
  PIN p
    DIRECTION INOUT ;
    USE SIGNAL ;
    PORT
      LAYER metal1 ;
      RECT 0 0 0.510 0.351 ;
    END
  END p
END m573
MACRO m574
  SIZE 0.510 BY 0.333 ;
  PIN p
    DIRECTION INOUT ;
    USE SIGNAL ;
    PORT
      LAYER metal1 ;
      RECT 0 0 0.510 0.333 ;
    END
  END p
END m574
MACRO m575
  SIZE 0.510 BY 0.445 ;
  PIN p
    DIRECTION INOUT ;
    USE SIGNAL ;
    PORT
      LAYER metal1 ;
      RECT 0 0 0.510 0.445 ;
    END
  END p
END m575
MACRO m576
  SIZE 0.510 BY 0.364 ;
  PIN p
    DIRECTION INOUT ;
    USE SIGNAL ;
    PORT
      LAYER metal1 ;
      RECT 0 0 0.510 0.364 ;
    END
  END p
END m576
MACRO m577
  SIZE 0.510 BY 0.376 ;
  PIN p
    DIRECTION INOUT ;
    USE SIGNAL ;
    PORT
      LAYER metal1 ;
      RECT 0 0 0.510 0.376 ;
    END
  END p
END m577
MACRO m578
  SIZE 0.510 BY 0.671 ;
  PIN p
    DIRECTION INOUT ;
    USE SIGNAL ;
    PORT
      LAYER metal1 ;
      RECT 0 0 0.510 0.671 ;
    END
  END p
END m578
MACRO m579
  SIZE 0.510 BY 0.282 ;
  PIN p
    DIRECTION INOUT ;
    USE SIGNAL ;
    PORT
      LAYER metal1 ;
      RECT 0 0 0.510 0.282 ;
    END
  END p
END m579
MACRO m580
  SIZE 0.510 BY 0.351 ;
  PIN p
    DIRECTION INOUT ;
    USE SIGNAL ;
    PORT
      LAYER metal1 ;
      RECT 0 0 0.510 0.351 ;
    END
  END p
END m580
MACRO m581
  SIZE 0.510 BY 0.540 ;
  PIN p
    DIRECTION INOUT ;
    USE SIGNAL ;
    PORT
      LAYER metal1 ;
      RECT 0 0 0.510 0.540 ;
    END
  END p
END m581
MACRO m582
  SIZE 0.510 BY 0.383 ;
  PIN p
    DIRECTION INOUT ;
    USE SIGNAL ;
    PORT
      LAYER metal1 ;
      RECT 0 0 0.510 0.383 ;
    END
  END p
END m582
MACRO m583
  SIZE 0.510 BY 0.420 ;
  PIN p
    DIRECTION INOUT ;
    USE SIGNAL ;
    PORT
      LAYER metal1 ;
      RECT 0 0 0.510 0.420 ;
    END
  END p
END m583
MACRO m584
  SIZE 0.510 BY 0.333 ;
  PIN p
    DIRECTION INOUT ;
    USE SIGNAL ;
    PORT
      LAYER metal1 ;
      RECT 0 0 0.510 0.333 ;
    END
  END p
END m584
MACRO m585
  SIZE 0.510 BY 0.558 ;
  PIN p
    DIRECTION INOUT ;
    USE SIGNAL ;
    PORT
      LAYER metal1 ;
      RECT 0 0 0.510 0.558 ;
    END
  END p
END m585
MACRO m586
  SIZE 0.510 BY 0.370 ;
  PIN p
    DIRECTION INOUT ;
    USE SIGNAL ;
    PORT
      LAYER metal1 ;
      RECT 0 0 0.510 0.370 ;
    END
  END p
END m586
MACRO m587
  SIZE 0.510 BY 0.207 ;
  PIN p
    DIRECTION INOUT ;
    USE SIGNAL ;
    PORT
      LAYER metal1 ;
      RECT 0 0 0.510 0.207 ;
    END
  END p
END m587
MACRO m588
  SIZE 0.510 BY 0.351 ;
  PIN p
    DIRECTION INOUT ;
    USE SIGNAL ;
    PORT
      LAYER metal1 ;
      RECT 0 0 0.510 0.351 ;
    END
  END p
END m588
MACRO m589
  SIZE 0.510 BY 0.464 ;
  PIN p
    DIRECTION INOUT ;
    USE SIGNAL ;
    PORT
      LAYER metal1 ;
      RECT 0 0 0.510 0.464 ;
    END
  END p
END m589
MACRO m590
  SIZE 0.510 BY 0.395 ;
  PIN p
    DIRECTION INOUT ;
    USE SIGNAL ;
    PORT
      LAYER metal1 ;
      RECT 0 0 0.510 0.395 ;
    END
  END p
END m590
MACRO m591
  SIZE 0.510 BY 0.552 ;
  PIN p
    DIRECTION INOUT ;
    USE SIGNAL ;
    PORT
      LAYER metal1 ;
      RECT 0 0 0.510 0.552 ;
    END
  END p
END m591
MACRO m592
  SIZE 0.510 BY 0.182 ;
  PIN p
    DIRECTION INOUT ;
    USE SIGNAL ;
    PORT
      LAYER metal1 ;
      RECT 0 0 0.510 0.182 ;
    END
  END p
END m592
MACRO m593
  SIZE 0.510 BY 0.238 ;
  PIN p
    DIRECTION INOUT ;
    USE SIGNAL ;
    PORT
      LAYER metal1 ;
      RECT 0 0 0.510 0.238 ;
    END
  END p
END m593
MACRO m594
  SIZE 0.510 BY 0.765 ;
  PIN p
    DIRECTION INOUT ;
    USE SIGNAL ;
    PORT
      LAYER metal1 ;
      RECT 0 0 0.510 0.765 ;
    END
  END p
END m594
MACRO m595
  SIZE 0.510 BY 0.634 ;
  PIN p
    DIRECTION INOUT ;
    USE SIGNAL ;
    PORT
      LAYER metal1 ;
      RECT 0 0 0.510 0.634 ;
    END
  END p
END m595
MACRO m596
  SIZE 0.510 BY 0.414 ;
  PIN p
    DIRECTION INOUT ;
    USE SIGNAL ;
    PORT
      LAYER metal1 ;
      RECT 0 0 0.510 0.414 ;
    END
  END p
END m596
MACRO m597
  SIZE 0.510 BY 0.220 ;
  PIN p
    DIRECTION INOUT ;
    USE SIGNAL ;
    PORT
      LAYER metal1 ;
      RECT 0 0 0.510 0.220 ;
    END
  END p
END m597
MACRO m598
  SIZE 0.510 BY 0.370 ;
  PIN p
    DIRECTION INOUT ;
    USE SIGNAL ;
    PORT
      LAYER metal1 ;
      RECT 0 0 0.510 0.370 ;
    END
  END p
END m598
MACRO m599
  SIZE 0.510 BY 0.201 ;
  PIN p
    DIRECTION INOUT ;
    USE SIGNAL ;
    PORT
      LAYER metal1 ;
      RECT 0 0 0.510 0.201 ;
    END
  END p
END m599
MACRO m600
  SIZE 0.510 BY 0.646 ;
  PIN p
    DIRECTION INOUT ;
    USE SIGNAL ;
    PORT
      LAYER metal1 ;
      RECT 0 0 0.510 0.646 ;
    END
  END p
END m600
MACRO m601
  SIZE 0.510 BY 0.226 ;
  PIN p
    DIRECTION INOUT ;
    USE SIGNAL ;
    PORT
      LAYER metal1 ;
      RECT 0 0 0.510 0.226 ;
    END
  END p
END m601
MACRO m602
  SIZE 0.510 BY 0.320 ;
  PIN p
    DIRECTION INOUT ;
    USE SIGNAL ;
    PORT
      LAYER metal1 ;
      RECT 0 0 0.510 0.320 ;
    END
  END p
END m602
MACRO m603
  SIZE 0.510 BY 0.439 ;
  PIN p
    DIRECTION INOUT ;
    USE SIGNAL ;
    PORT
      LAYER metal1 ;
      RECT 0 0 0.510 0.439 ;
    END
  END p
END m603
MACRO m604
  SIZE 0.510 BY 0.452 ;
  PIN p
    DIRECTION INOUT ;
    USE SIGNAL ;
    PORT
      LAYER metal1 ;
      RECT 0 0 0.510 0.452 ;
    END
  END p
END m604
MACRO m605
  SIZE 0.510 BY 0.251 ;
  PIN p
    DIRECTION INOUT ;
    USE SIGNAL ;
    PORT
      LAYER metal1 ;
      RECT 0 0 0.510 0.251 ;
    END
  END p
END m605
MACRO m606
  SIZE 0.510 BY 0.540 ;
  PIN p
    DIRECTION INOUT ;
    USE SIGNAL ;
    PORT
      LAYER metal1 ;
      RECT 0 0 0.510 0.540 ;
    END
  END p
END m606
MACRO m607
  SIZE 0.510 BY 0.841 ;
  PIN p
    DIRECTION INOUT ;
    USE SIGNAL ;
    PORT
      LAYER metal1 ;
      RECT 0 0 0.510 0.841 ;
    END
  END p
END m607
MACRO m608
  SIZE 0.510 BY 0.533 ;
  PIN p
    DIRECTION INOUT ;
    USE SIGNAL ;
    PORT
      LAYER metal1 ;
      RECT 0 0 0.510 0.533 ;
    END
  END p
END m608
MACRO m609
  SIZE 0.510 BY 0.157 ;
  PIN p
    DIRECTION INOUT ;
    USE SIGNAL ;
    PORT
      LAYER metal1 ;
      RECT 0 0 0.510 0.157 ;
    END
  END p
END m609
MACRO m610
  SIZE 0.510 BY 0.320 ;
  PIN p
    DIRECTION INOUT ;
    USE SIGNAL ;
    PORT
      LAYER metal1 ;
      RECT 0 0 0.510 0.320 ;
    END
  END p
END m610
MACRO m611
  SIZE 0.510 BY 1.161 ;
  PIN p
    DIRECTION INOUT ;
    USE SIGNAL ;
    PORT
      LAYER metal1 ;
      RECT 0 0 0.510 1.161 ;
    END
  END p
END m611
MACRO m612
  SIZE 0.510 BY 0.195 ;
  PIN p
    DIRECTION INOUT ;
    USE SIGNAL ;
    PORT
      LAYER metal1 ;
      RECT 0 0 0.510 0.195 ;
    END
  END p
END m612
MACRO m613
  SIZE 0.510 BY 0.458 ;
  PIN p
    DIRECTION INOUT ;
    USE SIGNAL ;
    PORT
      LAYER metal1 ;
      RECT 0 0 0.510 0.458 ;
    END
  END p
END m613
MACRO m614
  SIZE 0.510 BY 0.314 ;
  PIN p
    DIRECTION INOUT ;
    USE SIGNAL ;
    PORT
      LAYER metal1 ;
      RECT 0 0 0.510 0.314 ;
    END
  END p
END m614
MACRO m615
  SIZE 0.510 BY 0.464 ;
  PIN p
    DIRECTION INOUT ;
    USE SIGNAL ;
    PORT
      LAYER metal1 ;
      RECT 0 0 0.510 0.464 ;
    END
  END p
END m615
MACRO m616
  SIZE 0.510 BY 0.439 ;
  PIN p
    DIRECTION INOUT ;
    USE SIGNAL ;
    PORT
      LAYER metal1 ;
      RECT 0 0 0.510 0.439 ;
    END
  END p
END m616
MACRO m617
  SIZE 0.510 BY 0.376 ;
  PIN p
    DIRECTION INOUT ;
    USE SIGNAL ;
    PORT
      LAYER metal1 ;
      RECT 0 0 0.510 0.376 ;
    END
  END p
END m617
MACRO m618
  SIZE 0.510 BY 0.289 ;
  PIN p
    DIRECTION INOUT ;
    USE SIGNAL ;
    PORT
      LAYER metal1 ;
      RECT 0 0 0.510 0.289 ;
    END
  END p
END m618
MACRO m619
  SIZE 0.510 BY 0.301 ;
  PIN p
    DIRECTION INOUT ;
    USE SIGNAL ;
    PORT
      LAYER metal1 ;
      RECT 0 0 0.510 0.301 ;
    END
  END p
END m619
MACRO m620
  SIZE 0.510 BY 0.238 ;
  PIN p
    DIRECTION INOUT ;
    USE SIGNAL ;
    PORT
      LAYER metal1 ;
      RECT 0 0 0.510 0.238 ;
    END
  END p
END m620
MACRO m621
  SIZE 0.510 BY 0.232 ;
  PIN p
    DIRECTION INOUT ;
    USE SIGNAL ;
    PORT
      LAYER metal1 ;
      RECT 0 0 0.510 0.232 ;
    END
  END p
END m621
MACRO m622
  SIZE 0.510 BY 0.383 ;
  PIN p
    DIRECTION INOUT ;
    USE SIGNAL ;
    PORT
      LAYER metal1 ;
      RECT 0 0 0.510 0.383 ;
    END
  END p
END m622
MACRO m623
  SIZE 0.510 BY 0.289 ;
  PIN p
    DIRECTION INOUT ;
    USE SIGNAL ;
    PORT
      LAYER metal1 ;
      RECT 0 0 0.510 0.289 ;
    END
  END p
END m623
MACRO m624
  SIZE 0.510 BY 0.847 ;
  PIN p
    DIRECTION INOUT ;
    USE SIGNAL ;
    PORT
      LAYER metal1 ;
      RECT 0 0 0.510 0.847 ;
    END
  END p
END m624
MACRO m625
  SIZE 0.510 BY 0.345 ;
  PIN p
    DIRECTION INOUT ;
    USE SIGNAL ;
    PORT
      LAYER metal1 ;
      RECT 0 0 0.510 0.345 ;
    END
  END p
END m625
MACRO m626
  SIZE 0.510 BY 0.584 ;
  PIN p
    DIRECTION INOUT ;
    USE SIGNAL ;
    PORT
      LAYER metal1 ;
      RECT 0 0 0.510 0.584 ;
    END
  END p
END m626
MACRO m627
  SIZE 0.510 BY 0.163 ;
  PIN p
    DIRECTION INOUT ;
    USE SIGNAL ;
    PORT
      LAYER metal1 ;
      RECT 0 0 0.510 0.163 ;
    END
  END p
END m627
MACRO m628
  SIZE 0.510 BY 0.621 ;
  PIN p
    DIRECTION INOUT ;
    USE SIGNAL ;
    PORT
      LAYER metal1 ;
      RECT 0 0 0.510 0.621 ;
    END
  END p
END m628
MACRO m629
  SIZE 0.510 BY 0.577 ;
  PIN p
    DIRECTION INOUT ;
    USE SIGNAL ;
    PORT
      LAYER metal1 ;
      RECT 0 0 0.510 0.577 ;
    END
  END p
END m629
MACRO m630
  SIZE 0.510 BY 0.289 ;
  PIN p
    DIRECTION INOUT ;
    USE SIGNAL ;
    PORT
      LAYER metal1 ;
      RECT 0 0 0.510 0.289 ;
    END
  END p
END m630
MACRO m631
  SIZE 0.510 BY 0.508 ;
  PIN p
    DIRECTION INOUT ;
    USE SIGNAL ;
    PORT
      LAYER metal1 ;
      RECT 0 0 0.510 0.508 ;
    END
  END p
END m631
MACRO m632
  SIZE 0.510 BY 0.477 ;
  PIN p
    DIRECTION INOUT ;
    USE SIGNAL ;
    PORT
      LAYER metal1 ;
      RECT 0 0 0.510 0.477 ;
    END
  END p
END m632
MACRO m633
  SIZE 0.510 BY 0.571 ;
  PIN p
    DIRECTION INOUT ;
    USE SIGNAL ;
    PORT
      LAYER metal1 ;
      RECT 0 0 0.510 0.571 ;
    END
  END p
END m633
MACRO m634
  SIZE 0.510 BY 0.759 ;
  PIN p
    DIRECTION INOUT ;
    USE SIGNAL ;
    PORT
      LAYER metal1 ;
      RECT 0 0 0.510 0.759 ;
    END
  END p
END m634
MACRO m635
  SIZE 0.510 BY 0.835 ;
  PIN p
    DIRECTION INOUT ;
    USE SIGNAL ;
    PORT
      LAYER metal1 ;
      RECT 0 0 0.510 0.835 ;
    END
  END p
END m635
MACRO m636
  SIZE 0.510 BY 0.320 ;
  PIN p
    DIRECTION INOUT ;
    USE SIGNAL ;
    PORT
      LAYER metal1 ;
      RECT 0 0 0.510 0.320 ;
    END
  END p
END m636
MACRO m637
  SIZE 0.510 BY 0.414 ;
  PIN p
    DIRECTION INOUT ;
    USE SIGNAL ;
    PORT
      LAYER metal1 ;
      RECT 0 0 0.510 0.414 ;
    END
  END p
END m637
MACRO m638
  SIZE 0.510 BY 0.326 ;
  PIN p
    DIRECTION INOUT ;
    USE SIGNAL ;
    PORT
      LAYER metal1 ;
      RECT 0 0 0.510 0.326 ;
    END
  END p
END m638
MACRO m639
  SIZE 0.510 BY 0.339 ;
  PIN p
    DIRECTION INOUT ;
    USE SIGNAL ;
    PORT
      LAYER metal1 ;
      RECT 0 0 0.510 0.339 ;
    END
  END p
END m639
MACRO m640
  SIZE 0.510 BY 0.904 ;
  PIN p
    DIRECTION INOUT ;
    USE SIGNAL ;
    PORT
      LAYER metal1 ;
      RECT 0 0 0.510 0.904 ;
    END
  END p
END m640
MACRO m641
  SIZE 0.510 BY 0.364 ;
  PIN p
    DIRECTION INOUT ;
    USE SIGNAL ;
    PORT
      LAYER metal1 ;
      RECT 0 0 0.510 0.364 ;
    END
  END p
END m641
MACRO m642
  SIZE 0.510 BY 0.508 ;
  PIN p
    DIRECTION INOUT ;
    USE SIGNAL ;
    PORT
      LAYER metal1 ;
      RECT 0 0 0.510 0.508 ;
    END
  END p
END m642
MACRO m643
  SIZE 0.510 BY 0.414 ;
  PIN p
    DIRECTION INOUT ;
    USE SIGNAL ;
    PORT
      LAYER metal1 ;
      RECT 0 0 0.510 0.414 ;
    END
  END p
END m643
MACRO m644
  SIZE 0.510 BY 0.395 ;
  PIN p
    DIRECTION INOUT ;
    USE SIGNAL ;
    PORT
      LAYER metal1 ;
      RECT 0 0 0.510 0.395 ;
    END
  END p
END m644
MACRO m645
  SIZE 0.510 BY 0.584 ;
  PIN p
    DIRECTION INOUT ;
    USE SIGNAL ;
    PORT
      LAYER metal1 ;
      RECT 0 0 0.510 0.584 ;
    END
  END p
END m645
MACRO m646
  SIZE 0.510 BY 0.546 ;
  PIN p
    DIRECTION INOUT ;
    USE SIGNAL ;
    PORT
      LAYER metal1 ;
      RECT 0 0 0.510 0.546 ;
    END
  END p
END m646
MACRO m647
  SIZE 0.510 BY 0.803 ;
  PIN p
    DIRECTION INOUT ;
    USE SIGNAL ;
    PORT
      LAYER metal1 ;
      RECT 0 0 0.510 0.803 ;
    END
  END p
END m647
MACRO m648
  SIZE 0.510 BY 0.809 ;
  PIN p
    DIRECTION INOUT ;
    USE SIGNAL ;
    PORT
      LAYER metal1 ;
      RECT 0 0 0.510 0.809 ;
    END
  END p
END m648
MACRO m649
  SIZE 0.510 BY 0.678 ;
  PIN p
    DIRECTION INOUT ;
    USE SIGNAL ;
    PORT
      LAYER metal1 ;
      RECT 0 0 0.510 0.678 ;
    END
  END p
END m649
MACRO m650
  SIZE 0.510 BY 0.671 ;
  PIN p
    DIRECTION INOUT ;
    USE SIGNAL ;
    PORT
      LAYER metal1 ;
      RECT 0 0 0.510 0.671 ;
    END
  END p
END m650
MACRO m651
  SIZE 0.510 BY 0.483 ;
  PIN p
    DIRECTION INOUT ;
    USE SIGNAL ;
    PORT
      LAYER metal1 ;
      RECT 0 0 0.510 0.483 ;
    END
  END p
END m651
MACRO m652
  SIZE 0.510 BY 0.075 ;
  PIN p
    DIRECTION INOUT ;
    USE SIGNAL ;
    PORT
      LAYER metal1 ;
      RECT 0 0 0.510 0.075 ;
    END
  END p
END m652
MACRO m653
  SIZE 0.510 BY 0.615 ;
  PIN p
    DIRECTION INOUT ;
    USE SIGNAL ;
    PORT
      LAYER metal1 ;
      RECT 0 0 0.510 0.615 ;
    END
  END p
END m653
MACRO m654
  SIZE 0.510 BY 0.540 ;
  PIN p
    DIRECTION INOUT ;
    USE SIGNAL ;
    PORT
      LAYER metal1 ;
      RECT 0 0 0.510 0.540 ;
    END
  END p
END m654
MACRO m655
  SIZE 0.510 BY 0.427 ;
  PIN p
    DIRECTION INOUT ;
    USE SIGNAL ;
    PORT
      LAYER metal1 ;
      RECT 0 0 0.510 0.427 ;
    END
  END p
END m655
MACRO m656
  SIZE 0.510 BY 0.195 ;
  PIN p
    DIRECTION INOUT ;
    USE SIGNAL ;
    PORT
      LAYER metal1 ;
      RECT 0 0 0.510 0.195 ;
    END
  END p
END m656
MACRO m657
  SIZE 0.510 BY 0.176 ;
  PIN p
    DIRECTION INOUT ;
    USE SIGNAL ;
    PORT
      LAYER metal1 ;
      RECT 0 0 0.510 0.176 ;
    END
  END p
END m657
MACRO m658
  SIZE 0.510 BY 0.464 ;
  PIN p
    DIRECTION INOUT ;
    USE SIGNAL ;
    PORT
      LAYER metal1 ;
      RECT 0 0 0.510 0.464 ;
    END
  END p
END m658
MACRO m659
  SIZE 0.510 BY 0.709 ;
  PIN p
    DIRECTION INOUT ;
    USE SIGNAL ;
    PORT
      LAYER metal1 ;
      RECT 0 0 0.510 0.709 ;
    END
  END p
END m659
MACRO m660
  SIZE 0.510 BY 0.483 ;
  PIN p
    DIRECTION INOUT ;
    USE SIGNAL ;
    PORT
      LAYER metal1 ;
      RECT 0 0 0.510 0.483 ;
    END
  END p
END m660
MACRO m661
  SIZE 0.510 BY 0.515 ;
  PIN p
    DIRECTION INOUT ;
    USE SIGNAL ;
    PORT
      LAYER metal1 ;
      RECT 0 0 0.510 0.515 ;
    END
  END p
END m661
MACRO m662
  SIZE 0.510 BY 0.878 ;
  PIN p
    DIRECTION INOUT ;
    USE SIGNAL ;
    PORT
      LAYER metal1 ;
      RECT 0 0 0.510 0.878 ;
    END
  END p
END m662
MACRO m663
  SIZE 0.510 BY 0.740 ;
  PIN p
    DIRECTION INOUT ;
    USE SIGNAL ;
    PORT
      LAYER metal1 ;
      RECT 0 0 0.510 0.740 ;
    END
  END p
END m663
MACRO m664
  SIZE 0.510 BY 0.301 ;
  PIN p
    DIRECTION INOUT ;
    USE SIGNAL ;
    PORT
      LAYER metal1 ;
      RECT 0 0 0.510 0.301 ;
    END
  END p
END m664
MACRO m665
  SIZE 0.510 BY 0.615 ;
  PIN p
    DIRECTION INOUT ;
    USE SIGNAL ;
    PORT
      LAYER metal1 ;
      RECT 0 0 0.510 0.615 ;
    END
  END p
END m665
MACRO m666
  SIZE 0.510 BY 0.515 ;
  PIN p
    DIRECTION INOUT ;
    USE SIGNAL ;
    PORT
      LAYER metal1 ;
      RECT 0 0 0.510 0.515 ;
    END
  END p
END m666
MACRO m667
  SIZE 0.510 BY 0.847 ;
  PIN p
    DIRECTION INOUT ;
    USE SIGNAL ;
    PORT
      LAYER metal1 ;
      RECT 0 0 0.510 0.847 ;
    END
  END p
END m667
MACRO m668
  SIZE 0.510 BY 0.546 ;
  PIN p
    DIRECTION INOUT ;
    USE SIGNAL ;
    PORT
      LAYER metal1 ;
      RECT 0 0 0.510 0.546 ;
    END
  END p
END m668
MACRO m669
  SIZE 0.510 BY 0.759 ;
  PIN p
    DIRECTION INOUT ;
    USE SIGNAL ;
    PORT
      LAYER metal1 ;
      RECT 0 0 0.510 0.759 ;
    END
  END p
END m669
MACRO m670
  SIZE 0.510 BY 0.602 ;
  PIN p
    DIRECTION INOUT ;
    USE SIGNAL ;
    PORT
      LAYER metal1 ;
      RECT 0 0 0.510 0.602 ;
    END
  END p
END m670
MACRO m671
  SIZE 0.510 BY 0.584 ;
  PIN p
    DIRECTION INOUT ;
    USE SIGNAL ;
    PORT
      LAYER metal1 ;
      RECT 0 0 0.510 0.584 ;
    END
  END p
END m671
MACRO m672
  SIZE 0.510 BY 0.904 ;
  PIN p
    DIRECTION INOUT ;
    USE SIGNAL ;
    PORT
      LAYER metal1 ;
      RECT 0 0 0.510 0.904 ;
    END
  END p
END m672
MACRO m673
  SIZE 0.510 BY 0.609 ;
  PIN p
    DIRECTION INOUT ;
    USE SIGNAL ;
    PORT
      LAYER metal1 ;
      RECT 0 0 0.510 0.609 ;
    END
  END p
END m673
MACRO m674
  SIZE 0.510 BY 0.445 ;
  PIN p
    DIRECTION INOUT ;
    USE SIGNAL ;
    PORT
      LAYER metal1 ;
      RECT 0 0 0.510 0.445 ;
    END
  END p
END m674
MACRO m675
  SIZE 0.510 BY 0.533 ;
  PIN p
    DIRECTION INOUT ;
    USE SIGNAL ;
    PORT
      LAYER metal1 ;
      RECT 0 0 0.510 0.533 ;
    END
  END p
END m675
MACRO m676
  SIZE 0.510 BY 0.251 ;
  PIN p
    DIRECTION INOUT ;
    USE SIGNAL ;
    PORT
      LAYER metal1 ;
      RECT 0 0 0.510 0.251 ;
    END
  END p
END m676
MACRO m677
  SIZE 0.510 BY 0.502 ;
  PIN p
    DIRECTION INOUT ;
    USE SIGNAL ;
    PORT
      LAYER metal1 ;
      RECT 0 0 0.510 0.502 ;
    END
  END p
END m677
MACRO m678
  SIZE 0.510 BY 0.979 ;
  PIN p
    DIRECTION INOUT ;
    USE SIGNAL ;
    PORT
      LAYER metal1 ;
      RECT 0 0 0.510 0.979 ;
    END
  END p
END m678
MACRO m679
  SIZE 0.510 BY 0.540 ;
  PIN p
    DIRECTION INOUT ;
    USE SIGNAL ;
    PORT
      LAYER metal1 ;
      RECT 0 0 0.510 0.540 ;
    END
  END p
END m679
MACRO m680
  SIZE 0.510 BY 0.646 ;
  PIN p
    DIRECTION INOUT ;
    USE SIGNAL ;
    PORT
      LAYER metal1 ;
      RECT 0 0 0.510 0.646 ;
    END
  END p
END m680
MACRO m681
  SIZE 0.510 BY 0.169 ;
  PIN p
    DIRECTION INOUT ;
    USE SIGNAL ;
    PORT
      LAYER metal1 ;
      RECT 0 0 0.510 0.169 ;
    END
  END p
END m681
MACRO m682
  SIZE 0.510 BY 0.364 ;
  PIN p
    DIRECTION INOUT ;
    USE SIGNAL ;
    PORT
      LAYER metal1 ;
      RECT 0 0 0.510 0.364 ;
    END
  END p
END m682
MACRO m683
  SIZE 0.510 BY 0.991 ;
  PIN p
    DIRECTION INOUT ;
    USE SIGNAL ;
    PORT
      LAYER metal1 ;
      RECT 0 0 0.510 0.991 ;
    END
  END p
END m683
MACRO m684
  SIZE 0.510 BY 0.565 ;
  PIN p
    DIRECTION INOUT ;
    USE SIGNAL ;
    PORT
      LAYER metal1 ;
      RECT 0 0 0.510 0.565 ;
    END
  END p
END m684
MACRO m685
  SIZE 0.510 BY 0.665 ;
  PIN p
    DIRECTION INOUT ;
    USE SIGNAL ;
    PORT
      LAYER metal1 ;
      RECT 0 0 0.510 0.665 ;
    END
  END p
END m685
MACRO m686
  SIZE 0.510 BY 0.276 ;
  PIN p
    DIRECTION INOUT ;
    USE SIGNAL ;
    PORT
      LAYER metal1 ;
      RECT 0 0 0.510 0.276 ;
    END
  END p
END m686
MACRO m687
  SIZE 0.510 BY 0.558 ;
  PIN p
    DIRECTION INOUT ;
    USE SIGNAL ;
    PORT
      LAYER metal1 ;
      RECT 0 0 0.510 0.558 ;
    END
  END p
END m687
MACRO m688
  SIZE 0.510 BY 0.540 ;
  PIN p
    DIRECTION INOUT ;
    USE SIGNAL ;
    PORT
      LAYER metal1 ;
      RECT 0 0 0.510 0.540 ;
    END
  END p
END m688
MACRO m689
  SIZE 0.510 BY 1.073 ;
  PIN p
    DIRECTION INOUT ;
    USE SIGNAL ;
    PORT
      LAYER metal1 ;
      RECT 0 0 0.510 1.073 ;
    END
  END p
END m689
MACRO m690
  SIZE 0.510 BY 0.364 ;
  PIN p
    DIRECTION INOUT ;
    USE SIGNAL ;
    PORT
      LAYER metal1 ;
      RECT 0 0 0.510 0.364 ;
    END
  END p
END m690
MACRO m691
  SIZE 0.510 BY 0.351 ;
  PIN p
    DIRECTION INOUT ;
    USE SIGNAL ;
    PORT
      LAYER metal1 ;
      RECT 0 0 0.510 0.351 ;
    END
  END p
END m691
MACRO m692
  SIZE 0.510 BY 0.602 ;
  PIN p
    DIRECTION INOUT ;
    USE SIGNAL ;
    PORT
      LAYER metal1 ;
      RECT 0 0 0.510 0.602 ;
    END
  END p
END m692
MACRO m693
  SIZE 0.510 BY 0.577 ;
  PIN p
    DIRECTION INOUT ;
    USE SIGNAL ;
    PORT
      LAYER metal1 ;
      RECT 0 0 0.510 0.577 ;
    END
  END p
END m693
MACRO m694
  SIZE 0.510 BY 0.546 ;
  PIN p
    DIRECTION INOUT ;
    USE SIGNAL ;
    PORT
      LAYER metal1 ;
      RECT 0 0 0.510 0.546 ;
    END
  END p
END m694
MACRO m695
  SIZE 0.510 BY 0.515 ;
  PIN p
    DIRECTION INOUT ;
    USE SIGNAL ;
    PORT
      LAYER metal1 ;
      RECT 0 0 0.510 0.515 ;
    END
  END p
END m695
MACRO m696
  SIZE 0.510 BY 0.508 ;
  PIN p
    DIRECTION INOUT ;
    USE SIGNAL ;
    PORT
      LAYER metal1 ;
      RECT 0 0 0.510 0.508 ;
    END
  END p
END m696
MACRO m697
  SIZE 0.510 BY 0.477 ;
  PIN p
    DIRECTION INOUT ;
    USE SIGNAL ;
    PORT
      LAYER metal1 ;
      RECT 0 0 0.510 0.477 ;
    END
  END p
END m697
MACRO m698
  SIZE 0.510 BY 0.552 ;
  PIN p
    DIRECTION INOUT ;
    USE SIGNAL ;
    PORT
      LAYER metal1 ;
      RECT 0 0 0.510 0.552 ;
    END
  END p
END m698
MACRO m699
  SIZE 0.510 BY 0.345 ;
  PIN p
    DIRECTION INOUT ;
    USE SIGNAL ;
    PORT
      LAYER metal1 ;
      RECT 0 0 0.510 0.345 ;
    END
  END p
END m699
MACRO m700
  SIZE 0.510 BY 0.389 ;
  PIN p
    DIRECTION INOUT ;
    USE SIGNAL ;
    PORT
      LAYER metal1 ;
      RECT 0 0 0.510 0.389 ;
    END
  END p
END m700
MACRO m701
  SIZE 0.510 BY 0.433 ;
  PIN p
    DIRECTION INOUT ;
    USE SIGNAL ;
    PORT
      LAYER metal1 ;
      RECT 0 0 0.510 0.433 ;
    END
  END p
END m701
MACRO m702
  SIZE 0.510 BY 0.734 ;
  PIN p
    DIRECTION INOUT ;
    USE SIGNAL ;
    PORT
      LAYER metal1 ;
      RECT 0 0 0.510 0.734 ;
    END
  END p
END m702
MACRO m703
  SIZE 0.510 BY 0.659 ;
  PIN p
    DIRECTION INOUT ;
    USE SIGNAL ;
    PORT
      LAYER metal1 ;
      RECT 0 0 0.510 0.659 ;
    END
  END p
END m703
MACRO m704
  SIZE 0.510 BY 0.684 ;
  PIN p
    DIRECTION INOUT ;
    USE SIGNAL ;
    PORT
      LAYER metal1 ;
      RECT 0 0 0.510 0.684 ;
    END
  END p
END m704
MACRO m705
  SIZE 0.510 BY 0.966 ;
  PIN p
    DIRECTION INOUT ;
    USE SIGNAL ;
    PORT
      LAYER metal1 ;
      RECT 0 0 0.510 0.966 ;
    END
  END p
END m705
MACRO m706
  SIZE 0.510 BY 0.213 ;
  PIN p
    DIRECTION INOUT ;
    USE SIGNAL ;
    PORT
      LAYER metal1 ;
      RECT 0 0 0.510 0.213 ;
    END
  END p
END m706
MACRO m707
  SIZE 0.510 BY 0.257 ;
  PIN p
    DIRECTION INOUT ;
    USE SIGNAL ;
    PORT
      LAYER metal1 ;
      RECT 0 0 0.510 0.257 ;
    END
  END p
END m707
MACRO m708
  SIZE 0.510 BY 0.508 ;
  PIN p
    DIRECTION INOUT ;
    USE SIGNAL ;
    PORT
      LAYER metal1 ;
      RECT 0 0 0.510 0.508 ;
    END
  END p
END m708
MACRO m709
  SIZE 0.510 BY 0.922 ;
  PIN p
    DIRECTION INOUT ;
    USE SIGNAL ;
    PORT
      LAYER metal1 ;
      RECT 0 0 0.510 0.922 ;
    END
  END p
END m709
MACRO m710
  SIZE 0.510 BY 0.835 ;
  PIN p
    DIRECTION INOUT ;
    USE SIGNAL ;
    PORT
      LAYER metal1 ;
      RECT 0 0 0.510 0.835 ;
    END
  END p
END m710
MACRO m711
  SIZE 0.510 BY 1.311 ;
  PIN p
    DIRECTION INOUT ;
    USE SIGNAL ;
    PORT
      LAYER metal1 ;
      RECT 0 0 0.510 1.311 ;
    END
  END p
END m711
MACRO m712
  SIZE 0.510 BY 0.420 ;
  PIN p
    DIRECTION INOUT ;
    USE SIGNAL ;
    PORT
      LAYER metal1 ;
      RECT 0 0 0.510 0.420 ;
    END
  END p
END m712
MACRO m713
  SIZE 0.510 BY 0.351 ;
  PIN p
    DIRECTION INOUT ;
    USE SIGNAL ;
    PORT
      LAYER metal1 ;
      RECT 0 0 0.510 0.351 ;
    END
  END p
END m713
MACRO m714
  SIZE 0.510 BY 0.602 ;
  PIN p
    DIRECTION INOUT ;
    USE SIGNAL ;
    PORT
      LAYER metal1 ;
      RECT 0 0 0.510 0.602 ;
    END
  END p
END m714
MACRO m715
  SIZE 0.510 BY 0.740 ;
  PIN p
    DIRECTION INOUT ;
    USE SIGNAL ;
    PORT
      LAYER metal1 ;
      RECT 0 0 0.510 0.740 ;
    END
  END p
END m715
MACRO m716
  SIZE 0.510 BY 0.922 ;
  PIN p
    DIRECTION INOUT ;
    USE SIGNAL ;
    PORT
      LAYER metal1 ;
      RECT 0 0 0.510 0.922 ;
    END
  END p
END m716
MACRO m717
  SIZE 0.510 BY 0.464 ;
  PIN p
    DIRECTION INOUT ;
    USE SIGNAL ;
    PORT
      LAYER metal1 ;
      RECT 0 0 0.510 0.464 ;
    END
  END p
END m717
MACRO m718
  SIZE 0.510 BY 0.508 ;
  PIN p
    DIRECTION INOUT ;
    USE SIGNAL ;
    PORT
      LAYER metal1 ;
      RECT 0 0 0.510 0.508 ;
    END
  END p
END m718
MACRO m719
  SIZE 0.510 BY 0.464 ;
  PIN p
    DIRECTION INOUT ;
    USE SIGNAL ;
    PORT
      LAYER metal1 ;
      RECT 0 0 0.510 0.464 ;
    END
  END p
END m719
MACRO m720
  SIZE 0.510 BY 0.427 ;
  PIN p
    DIRECTION INOUT ;
    USE SIGNAL ;
    PORT
      LAYER metal1 ;
      RECT 0 0 0.510 0.427 ;
    END
  END p
END m720
MACRO m721
  SIZE 0.510 BY 0.427 ;
  PIN p
    DIRECTION INOUT ;
    USE SIGNAL ;
    PORT
      LAYER metal1 ;
      RECT 0 0 0.510 0.427 ;
    END
  END p
END m721
MACRO m722
  SIZE 0.510 BY 0.527 ;
  PIN p
    DIRECTION INOUT ;
    USE SIGNAL ;
    PORT
      LAYER metal1 ;
      RECT 0 0 0.510 0.527 ;
    END
  END p
END m722
MACRO m723
  SIZE 0.510 BY 0.464 ;
  PIN p
    DIRECTION INOUT ;
    USE SIGNAL ;
    PORT
      LAYER metal1 ;
      RECT 0 0 0.510 0.464 ;
    END
  END p
END m723
MACRO m724
  SIZE 0.510 BY 0.734 ;
  PIN p
    DIRECTION INOUT ;
    USE SIGNAL ;
    PORT
      LAYER metal1 ;
      RECT 0 0 0.510 0.734 ;
    END
  END p
END m724
MACRO m725
  SIZE 0.510 BY 0.420 ;
  PIN p
    DIRECTION INOUT ;
    USE SIGNAL ;
    PORT
      LAYER metal1 ;
      RECT 0 0 0.510 0.420 ;
    END
  END p
END m725
MACRO m726
  SIZE 0.510 BY 0.333 ;
  PIN p
    DIRECTION INOUT ;
    USE SIGNAL ;
    PORT
      LAYER metal1 ;
      RECT 0 0 0.510 0.333 ;
    END
  END p
END m726
MACRO m727
  SIZE 0.510 BY 0.740 ;
  PIN p
    DIRECTION INOUT ;
    USE SIGNAL ;
    PORT
      LAYER metal1 ;
      RECT 0 0 0.510 0.740 ;
    END
  END p
END m727
MACRO m728
  SIZE 0.510 BY 0.477 ;
  PIN p
    DIRECTION INOUT ;
    USE SIGNAL ;
    PORT
      LAYER metal1 ;
      RECT 0 0 0.510 0.477 ;
    END
  END p
END m728
MACRO m729
  SIZE 0.510 BY 0.358 ;
  PIN p
    DIRECTION INOUT ;
    USE SIGNAL ;
    PORT
      LAYER metal1 ;
      RECT 0 0 0.510 0.358 ;
    END
  END p
END m729
MACRO m730
  SIZE 0.510 BY 0.973 ;
  PIN p
    DIRECTION INOUT ;
    USE SIGNAL ;
    PORT
      LAYER metal1 ;
      RECT 0 0 0.510 0.973 ;
    END
  END p
END m730
MACRO m731
  SIZE 0.510 BY 0.176 ;
  PIN p
    DIRECTION INOUT ;
    USE SIGNAL ;
    PORT
      LAYER metal1 ;
      RECT 0 0 0.510 0.176 ;
    END
  END p
END m731
MACRO m732
  SIZE 0.510 BY 0.395 ;
  PIN p
    DIRECTION INOUT ;
    USE SIGNAL ;
    PORT
      LAYER metal1 ;
      RECT 0 0 0.510 0.395 ;
    END
  END p
END m732
MACRO m733
  SIZE 0.510 BY 0.646 ;
  PIN p
    DIRECTION INOUT ;
    USE SIGNAL ;
    PORT
      LAYER metal1 ;
      RECT 0 0 0.510 0.646 ;
    END
  END p
END m733
MACRO m734
  SIZE 0.510 BY 0.753 ;
  PIN p
    DIRECTION INOUT ;
    USE SIGNAL ;
    PORT
      LAYER metal1 ;
      RECT 0 0 0.510 0.753 ;
    END
  END p
END m734
MACRO m735
  SIZE 0.510 BY 0.740 ;
  PIN p
    DIRECTION INOUT ;
    USE SIGNAL ;
    PORT
      LAYER metal1 ;
      RECT 0 0 0.510 0.740 ;
    END
  END p
END m735
MACRO m736
  SIZE 0.510 BY 0.772 ;
  PIN p
    DIRECTION INOUT ;
    USE SIGNAL ;
    PORT
      LAYER metal1 ;
      RECT 0 0 0.510 0.772 ;
    END
  END p
END m736
MACRO m737
  SIZE 0.510 BY 0.546 ;
  PIN p
    DIRECTION INOUT ;
    USE SIGNAL ;
    PORT
      LAYER metal1 ;
      RECT 0 0 0.510 0.546 ;
    END
  END p
END m737
MACRO m738
  SIZE 0.510 BY 0.615 ;
  PIN p
    DIRECTION INOUT ;
    USE SIGNAL ;
    PORT
      LAYER metal1 ;
      RECT 0 0 0.510 0.615 ;
    END
  END p
END m738
MACRO m739
  SIZE 0.510 BY 0.477 ;
  PIN p
    DIRECTION INOUT ;
    USE SIGNAL ;
    PORT
      LAYER metal1 ;
      RECT 0 0 0.510 0.477 ;
    END
  END p
END m739
MACRO m740
  SIZE 0.510 BY 0.257 ;
  PIN p
    DIRECTION INOUT ;
    USE SIGNAL ;
    PORT
      LAYER metal1 ;
      RECT 0 0 0.510 0.257 ;
    END
  END p
END m740
MACRO m741
  SIZE 0.510 BY 0.301 ;
  PIN p
    DIRECTION INOUT ;
    USE SIGNAL ;
    PORT
      LAYER metal1 ;
      RECT 0 0 0.510 0.301 ;
    END
  END p
END m741
MACRO m742
  SIZE 0.510 BY 0.584 ;
  PIN p
    DIRECTION INOUT ;
    USE SIGNAL ;
    PORT
      LAYER metal1 ;
      RECT 0 0 0.510 0.584 ;
    END
  END p
END m742
MACRO m743
  SIZE 0.510 BY 0.458 ;
  PIN p
    DIRECTION INOUT ;
    USE SIGNAL ;
    PORT
      LAYER metal1 ;
      RECT 0 0 0.510 0.458 ;
    END
  END p
END m743
MACRO m744
  SIZE 0.510 BY 0.521 ;
  PIN p
    DIRECTION INOUT ;
    USE SIGNAL ;
    PORT
      LAYER metal1 ;
      RECT 0 0 0.510 0.521 ;
    END
  END p
END m744
MACRO m745
  SIZE 0.510 BY 0.822 ;
  PIN p
    DIRECTION INOUT ;
    USE SIGNAL ;
    PORT
      LAYER metal1 ;
      RECT 0 0 0.510 0.822 ;
    END
  END p
END m745
MACRO m746
  SIZE 0.510 BY 0.489 ;
  PIN p
    DIRECTION INOUT ;
    USE SIGNAL ;
    PORT
      LAYER metal1 ;
      RECT 0 0 0.510 0.489 ;
    END
  END p
END m746
MACRO m747
  SIZE 0.510 BY 1.136 ;
  PIN p
    DIRECTION INOUT ;
    USE SIGNAL ;
    PORT
      LAYER metal1 ;
      RECT 0 0 0.510 1.136 ;
    END
  END p
END m747
MACRO m748
  SIZE 0.510 BY 0.489 ;
  PIN p
    DIRECTION INOUT ;
    USE SIGNAL ;
    PORT
      LAYER metal1 ;
      RECT 0 0 0.510 0.489 ;
    END
  END p
END m748
MACRO m749
  SIZE 0.510 BY 0.571 ;
  PIN p
    DIRECTION INOUT ;
    USE SIGNAL ;
    PORT
      LAYER metal1 ;
      RECT 0 0 0.510 0.571 ;
    END
  END p
END m749
MACRO m750
  SIZE 0.510 BY 0.157 ;
  PIN p
    DIRECTION INOUT ;
    USE SIGNAL ;
    PORT
      LAYER metal1 ;
      RECT 0 0 0.510 0.157 ;
    END
  END p
END m750
MACRO m751
  SIZE 0.510 BY 0.609 ;
  PIN p
    DIRECTION INOUT ;
    USE SIGNAL ;
    PORT
      LAYER metal1 ;
      RECT 0 0 0.510 0.609 ;
    END
  END p
END m751
MACRO m752
  SIZE 0.510 BY 1.054 ;
  PIN p
    DIRECTION INOUT ;
    USE SIGNAL ;
    PORT
      LAYER metal1 ;
      RECT 0 0 0.510 1.054 ;
    END
  END p
END m752
MACRO m753
  SIZE 0.510 BY 0.540 ;
  PIN p
    DIRECTION INOUT ;
    USE SIGNAL ;
    PORT
      LAYER metal1 ;
      RECT 0 0 0.510 0.540 ;
    END
  END p
END m753
MACRO m754
  SIZE 0.510 BY 0.791 ;
  PIN p
    DIRECTION INOUT ;
    USE SIGNAL ;
    PORT
      LAYER metal1 ;
      RECT 0 0 0.510 0.791 ;
    END
  END p
END m754
MACRO m755
  SIZE 0.510 BY 0.376 ;
  PIN p
    DIRECTION INOUT ;
    USE SIGNAL ;
    PORT
      LAYER metal1 ;
      RECT 0 0 0.510 0.376 ;
    END
  END p
END m755
MACRO m756
  SIZE 0.510 BY 0.289 ;
  PIN p
    DIRECTION INOUT ;
    USE SIGNAL ;
    PORT
      LAYER metal1 ;
      RECT 0 0 0.510 0.289 ;
    END
  END p
END m756
MACRO m757
  SIZE 0.510 BY 0.659 ;
  PIN p
    DIRECTION INOUT ;
    USE SIGNAL ;
    PORT
      LAYER metal1 ;
      RECT 0 0 0.510 0.659 ;
    END
  END p
END m757
MACRO m758
  SIZE 0.510 BY 0.678 ;
  PIN p
    DIRECTION INOUT ;
    USE SIGNAL ;
    PORT
      LAYER metal1 ;
      RECT 0 0 0.510 0.678 ;
    END
  END p
END m758
MACRO m759
  SIZE 0.510 BY 0.866 ;
  PIN p
    DIRECTION INOUT ;
    USE SIGNAL ;
    PORT
      LAYER metal1 ;
      RECT 0 0 0.510 0.866 ;
    END
  END p
END m759
MACRO m760
  SIZE 0.510 BY 0.414 ;
  PIN p
    DIRECTION INOUT ;
    USE SIGNAL ;
    PORT
      LAYER metal1 ;
      RECT 0 0 0.510 0.414 ;
    END
  END p
END m760
MACRO m761
  SIZE 0.510 BY 0.301 ;
  PIN p
    DIRECTION INOUT ;
    USE SIGNAL ;
    PORT
      LAYER metal1 ;
      RECT 0 0 0.510 0.301 ;
    END
  END p
END m761
MACRO m762
  SIZE 0.510 BY 0.615 ;
  PIN p
    DIRECTION INOUT ;
    USE SIGNAL ;
    PORT
      LAYER metal1 ;
      RECT 0 0 0.510 0.615 ;
    END
  END p
END m762
MACRO m763
  SIZE 0.510 BY 0.383 ;
  PIN p
    DIRECTION INOUT ;
    USE SIGNAL ;
    PORT
      LAYER metal1 ;
      RECT 0 0 0.510 0.383 ;
    END
  END p
END m763
MACRO m764
  SIZE 0.510 BY 0.395 ;
  PIN p
    DIRECTION INOUT ;
    USE SIGNAL ;
    PORT
      LAYER metal1 ;
      RECT 0 0 0.510 0.395 ;
    END
  END p
END m764
MACRO m765
  SIZE 0.510 BY 0.571 ;
  PIN p
    DIRECTION INOUT ;
    USE SIGNAL ;
    PORT
      LAYER metal1 ;
      RECT 0 0 0.510 0.571 ;
    END
  END p
END m765
MACRO m766
  SIZE 0.510 BY 0.389 ;
  PIN p
    DIRECTION INOUT ;
    USE SIGNAL ;
    PORT
      LAYER metal1 ;
      RECT 0 0 0.510 0.389 ;
    END
  END p
END m766
MACRO m767
  SIZE 0.510 BY 0.358 ;
  PIN p
    DIRECTION INOUT ;
    USE SIGNAL ;
    PORT
      LAYER metal1 ;
      RECT 0 0 0.510 0.358 ;
    END
  END p
END m767
MACRO m768
  SIZE 0.510 BY 0.251 ;
  PIN p
    DIRECTION INOUT ;
    USE SIGNAL ;
    PORT
      LAYER metal1 ;
      RECT 0 0 0.510 0.251 ;
    END
  END p
END m768
MACRO m769
  SIZE 0.510 BY 0.496 ;
  PIN p
    DIRECTION INOUT ;
    USE SIGNAL ;
    PORT
      LAYER metal1 ;
      RECT 0 0 0.510 0.496 ;
    END
  END p
END m769
MACRO m770
  SIZE 0.510 BY 0.502 ;
  PIN p
    DIRECTION INOUT ;
    USE SIGNAL ;
    PORT
      LAYER metal1 ;
      RECT 0 0 0.510 0.502 ;
    END
  END p
END m770
MACRO m771
  SIZE 0.510 BY 0.113 ;
  PIN p
    DIRECTION INOUT ;
    USE SIGNAL ;
    PORT
      LAYER metal1 ;
      RECT 0 0 0.510 0.113 ;
    END
  END p
END m771
MACRO m772
  SIZE 0.510 BY 0.665 ;
  PIN p
    DIRECTION INOUT ;
    USE SIGNAL ;
    PORT
      LAYER metal1 ;
      RECT 0 0 0.510 0.665 ;
    END
  END p
END m772
MACRO m773
  SIZE 0.510 BY 0.703 ;
  PIN p
    DIRECTION INOUT ;
    USE SIGNAL ;
    PORT
      LAYER metal1 ;
      RECT 0 0 0.510 0.703 ;
    END
  END p
END m773
MACRO m774
  SIZE 0.510 BY 0.439 ;
  PIN p
    DIRECTION INOUT ;
    USE SIGNAL ;
    PORT
      LAYER metal1 ;
      RECT 0 0 0.510 0.439 ;
    END
  END p
END m774
MACRO m775
  SIZE 0.510 BY 0.408 ;
  PIN p
    DIRECTION INOUT ;
    USE SIGNAL ;
    PORT
      LAYER metal1 ;
      RECT 0 0 0.510 0.408 ;
    END
  END p
END m775
MACRO m776
  SIZE 0.510 BY 0.370 ;
  PIN p
    DIRECTION INOUT ;
    USE SIGNAL ;
    PORT
      LAYER metal1 ;
      RECT 0 0 0.510 0.370 ;
    END
  END p
END m776
MACRO m777
  SIZE 0.510 BY 0.709 ;
  PIN p
    DIRECTION INOUT ;
    USE SIGNAL ;
    PORT
      LAYER metal1 ;
      RECT 0 0 0.510 0.709 ;
    END
  END p
END m777
MACRO m778
  SIZE 0.510 BY 0.358 ;
  PIN p
    DIRECTION INOUT ;
    USE SIGNAL ;
    PORT
      LAYER metal1 ;
      RECT 0 0 0.510 0.358 ;
    END
  END p
END m778
MACRO m779
  SIZE 0.510 BY 0.345 ;
  PIN p
    DIRECTION INOUT ;
    USE SIGNAL ;
    PORT
      LAYER metal1 ;
      RECT 0 0 0.510 0.345 ;
    END
  END p
END m779
MACRO m780
  SIZE 0.510 BY 0.521 ;
  PIN p
    DIRECTION INOUT ;
    USE SIGNAL ;
    PORT
      LAYER metal1 ;
      RECT 0 0 0.510 0.521 ;
    END
  END p
END m780
MACRO m781
  SIZE 0.510 BY 0.376 ;
  PIN p
    DIRECTION INOUT ;
    USE SIGNAL ;
    PORT
      LAYER metal1 ;
      RECT 0 0 0.510 0.376 ;
    END
  END p
END m781
MACRO m782
  SIZE 0.510 BY 0.408 ;
  PIN p
    DIRECTION INOUT ;
    USE SIGNAL ;
    PORT
      LAYER metal1 ;
      RECT 0 0 0.510 0.408 ;
    END
  END p
END m782
MACRO m783
  SIZE 0.510 BY 0.483 ;
  PIN p
    DIRECTION INOUT ;
    USE SIGNAL ;
    PORT
      LAYER metal1 ;
      RECT 0 0 0.510 0.483 ;
    END
  END p
END m783
MACRO m784
  SIZE 0.510 BY 0.508 ;
  PIN p
    DIRECTION INOUT ;
    USE SIGNAL ;
    PORT
      LAYER metal1 ;
      RECT 0 0 0.510 0.508 ;
    END
  END p
END m784
MACRO m785
  SIZE 0.510 BY 0.182 ;
  PIN p
    DIRECTION INOUT ;
    USE SIGNAL ;
    PORT
      LAYER metal1 ;
      RECT 0 0 0.510 0.182 ;
    END
  END p
END m785
MACRO m786
  SIZE 0.510 BY 0.740 ;
  PIN p
    DIRECTION INOUT ;
    USE SIGNAL ;
    PORT
      LAYER metal1 ;
      RECT 0 0 0.510 0.740 ;
    END
  END p
END m786
MACRO m787
  SIZE 0.510 BY 0.345 ;
  PIN p
    DIRECTION INOUT ;
    USE SIGNAL ;
    PORT
      LAYER metal1 ;
      RECT 0 0 0.510 0.345 ;
    END
  END p
END m787
MACRO m788
  SIZE 0.510 BY 0.722 ;
  PIN p
    DIRECTION INOUT ;
    USE SIGNAL ;
    PORT
      LAYER metal1 ;
      RECT 0 0 0.510 0.722 ;
    END
  END p
END m788
MACRO m789
  SIZE 0.510 BY 0.483 ;
  PIN p
    DIRECTION INOUT ;
    USE SIGNAL ;
    PORT
      LAYER metal1 ;
      RECT 0 0 0.510 0.483 ;
    END
  END p
END m789
MACRO m790
  SIZE 0.510 BY 0.370 ;
  PIN p
    DIRECTION INOUT ;
    USE SIGNAL ;
    PORT
      LAYER metal1 ;
      RECT 0 0 0.510 0.370 ;
    END
  END p
END m790
MACRO m791
  SIZE 0.510 BY 0.445 ;
  PIN p
    DIRECTION INOUT ;
    USE SIGNAL ;
    PORT
      LAYER metal1 ;
      RECT 0 0 0.510 0.445 ;
    END
  END p
END m791
MACRO m792
  SIZE 0.510 BY 0.533 ;
  PIN p
    DIRECTION INOUT ;
    USE SIGNAL ;
    PORT
      LAYER metal1 ;
      RECT 0 0 0.510 0.533 ;
    END
  END p
END m792
MACRO m793
  SIZE 0.510 BY 0.527 ;
  PIN p
    DIRECTION INOUT ;
    USE SIGNAL ;
    PORT
      LAYER metal1 ;
      RECT 0 0 0.510 0.527 ;
    END
  END p
END m793
MACRO m794
  SIZE 0.510 BY 0.471 ;
  PIN p
    DIRECTION INOUT ;
    USE SIGNAL ;
    PORT
      LAYER metal1 ;
      RECT 0 0 0.510 0.471 ;
    END
  END p
END m794
MACRO m795
  SIZE 0.510 BY 0.445 ;
  PIN p
    DIRECTION INOUT ;
    USE SIGNAL ;
    PORT
      LAYER metal1 ;
      RECT 0 0 0.510 0.445 ;
    END
  END p
END m795
MACRO m796
  SIZE 0.510 BY 0.571 ;
  PIN p
    DIRECTION INOUT ;
    USE SIGNAL ;
    PORT
      LAYER metal1 ;
      RECT 0 0 0.510 0.571 ;
    END
  END p
END m796
MACRO m797
  SIZE 0.510 BY 0.571 ;
  PIN p
    DIRECTION INOUT ;
    USE SIGNAL ;
    PORT
      LAYER metal1 ;
      RECT 0 0 0.510 0.571 ;
    END
  END p
END m797
MACRO m798
  SIZE 0.510 BY 0.728 ;
  PIN p
    DIRECTION INOUT ;
    USE SIGNAL ;
    PORT
      LAYER metal1 ;
      RECT 0 0 0.510 0.728 ;
    END
  END p
END m798
MACRO m799
  SIZE 0.510 BY 0.351 ;
  PIN p
    DIRECTION INOUT ;
    USE SIGNAL ;
    PORT
      LAYER metal1 ;
      RECT 0 0 0.510 0.351 ;
    END
  END p
END m799
MACRO m800
  SIZE 0.510 BY 1.311 ;
  PIN p
    DIRECTION INOUT ;
    USE SIGNAL ;
    PORT
      LAYER metal1 ;
      RECT 0 0 0.510 1.311 ;
    END
  END p
END m800
MACRO m801
  SIZE 0.510 BY 0.201 ;
  PIN p
    DIRECTION INOUT ;
    USE SIGNAL ;
    PORT
      LAYER metal1 ;
      RECT 0 0 0.510 0.201 ;
    END
  END p
END m801
MACRO m802
  SIZE 0.510 BY 0.540 ;
  PIN p
    DIRECTION INOUT ;
    USE SIGNAL ;
    PORT
      LAYER metal1 ;
      RECT 0 0 0.510 0.540 ;
    END
  END p
END m802
MACRO m803
  SIZE 0.510 BY 0.753 ;
  PIN p
    DIRECTION INOUT ;
    USE SIGNAL ;
    PORT
      LAYER metal1 ;
      RECT 0 0 0.510 0.753 ;
    END
  END p
END m803
MACRO m804
  SIZE 0.510 BY 0.427 ;
  PIN p
    DIRECTION INOUT ;
    USE SIGNAL ;
    PORT
      LAYER metal1 ;
      RECT 0 0 0.510 0.427 ;
    END
  END p
END m804
MACRO m805
  SIZE 0.510 BY 0.590 ;
  PIN p
    DIRECTION INOUT ;
    USE SIGNAL ;
    PORT
      LAYER metal1 ;
      RECT 0 0 0.510 0.590 ;
    END
  END p
END m805
MACRO m806
  SIZE 0.510 BY 0.370 ;
  PIN p
    DIRECTION INOUT ;
    USE SIGNAL ;
    PORT
      LAYER metal1 ;
      RECT 0 0 0.510 0.370 ;
    END
  END p
END m806
MACRO m807
  SIZE 0.510 BY 0.558 ;
  PIN p
    DIRECTION INOUT ;
    USE SIGNAL ;
    PORT
      LAYER metal1 ;
      RECT 0 0 0.510 0.558 ;
    END
  END p
END m807
MACRO m808
  SIZE 0.510 BY 0.533 ;
  PIN p
    DIRECTION INOUT ;
    USE SIGNAL ;
    PORT
      LAYER metal1 ;
      RECT 0 0 0.510 0.533 ;
    END
  END p
END m808
MACRO m809
  SIZE 0.510 BY 0.489 ;
  PIN p
    DIRECTION INOUT ;
    USE SIGNAL ;
    PORT
      LAYER metal1 ;
      RECT 0 0 0.510 0.489 ;
    END
  END p
END m809
MACRO m810
  SIZE 0.510 BY 0.866 ;
  PIN p
    DIRECTION INOUT ;
    USE SIGNAL ;
    PORT
      LAYER metal1 ;
      RECT 0 0 0.510 0.866 ;
    END
  END p
END m810
MACRO m811
  SIZE 0.510 BY 0.496 ;
  PIN p
    DIRECTION INOUT ;
    USE SIGNAL ;
    PORT
      LAYER metal1 ;
      RECT 0 0 0.510 0.496 ;
    END
  END p
END m811
MACRO m812
  SIZE 0.510 BY 1.173 ;
  PIN p
    DIRECTION INOUT ;
    USE SIGNAL ;
    PORT
      LAYER metal1 ;
      RECT 0 0 0.510 1.173 ;
    END
  END p
END m812
MACRO m813
  SIZE 0.510 BY 0.408 ;
  PIN p
    DIRECTION INOUT ;
    USE SIGNAL ;
    PORT
      LAYER metal1 ;
      RECT 0 0 0.510 0.408 ;
    END
  END p
END m813
MACRO m814
  SIZE 0.510 BY 0.088 ;
  PIN p
    DIRECTION INOUT ;
    USE SIGNAL ;
    PORT
      LAYER metal1 ;
      RECT 0 0 0.510 0.088 ;
    END
  END p
END m814
MACRO m815
  SIZE 0.510 BY 0.402 ;
  PIN p
    DIRECTION INOUT ;
    USE SIGNAL ;
    PORT
      LAYER metal1 ;
      RECT 0 0 0.510 0.402 ;
    END
  END p
END m815
MACRO m816
  SIZE 0.510 BY 0.295 ;
  PIN p
    DIRECTION INOUT ;
    USE SIGNAL ;
    PORT
      LAYER metal1 ;
      RECT 0 0 0.510 0.295 ;
    END
  END p
END m816
MACRO m817
  SIZE 0.510 BY 0.489 ;
  PIN p
    DIRECTION INOUT ;
    USE SIGNAL ;
    PORT
      LAYER metal1 ;
      RECT 0 0 0.510 0.489 ;
    END
  END p
END m817
MACRO m818
  SIZE 0.510 BY 0.176 ;
  PIN p
    DIRECTION INOUT ;
    USE SIGNAL ;
    PORT
      LAYER metal1 ;
      RECT 0 0 0.510 0.176 ;
    END
  END p
END m818
MACRO m819
  SIZE 0.510 BY 0.502 ;
  PIN p
    DIRECTION INOUT ;
    USE SIGNAL ;
    PORT
      LAYER metal1 ;
      RECT 0 0 0.510 0.502 ;
    END
  END p
END m819
MACRO m820
  SIZE 0.510 BY 0.571 ;
  PIN p
    DIRECTION INOUT ;
    USE SIGNAL ;
    PORT
      LAYER metal1 ;
      RECT 0 0 0.510 0.571 ;
    END
  END p
END m820
MACRO m821
  SIZE 0.510 BY 0.602 ;
  PIN p
    DIRECTION INOUT ;
    USE SIGNAL ;
    PORT
      LAYER metal1 ;
      RECT 0 0 0.510 0.602 ;
    END
  END p
END m821
MACRO m822
  SIZE 0.510 BY 0.496 ;
  PIN p
    DIRECTION INOUT ;
    USE SIGNAL ;
    PORT
      LAYER metal1 ;
      RECT 0 0 0.510 0.496 ;
    END
  END p
END m822
MACRO m823
  SIZE 0.510 BY 0.621 ;
  PIN p
    DIRECTION INOUT ;
    USE SIGNAL ;
    PORT
      LAYER metal1 ;
      RECT 0 0 0.510 0.621 ;
    END
  END p
END m823
MACRO m824
  SIZE 0.510 BY 0.678 ;
  PIN p
    DIRECTION INOUT ;
    USE SIGNAL ;
    PORT
      LAYER metal1 ;
      RECT 0 0 0.510 0.678 ;
    END
  END p
END m824
MACRO m825
  SIZE 0.510 BY 0.577 ;
  PIN p
    DIRECTION INOUT ;
    USE SIGNAL ;
    PORT
      LAYER metal1 ;
      RECT 0 0 0.510 0.577 ;
    END
  END p
END m825
MACRO m826
  SIZE 0.510 BY 0.596 ;
  PIN p
    DIRECTION INOUT ;
    USE SIGNAL ;
    PORT
      LAYER metal1 ;
      RECT 0 0 0.510 0.596 ;
    END
  END p
END m826
MACRO m827
  SIZE 0.510 BY 0.753 ;
  PIN p
    DIRECTION INOUT ;
    USE SIGNAL ;
    PORT
      LAYER metal1 ;
      RECT 0 0 0.510 0.753 ;
    END
  END p
END m827
MACRO m828
  SIZE 0.510 BY 0.464 ;
  PIN p
    DIRECTION INOUT ;
    USE SIGNAL ;
    PORT
      LAYER metal1 ;
      RECT 0 0 0.510 0.464 ;
    END
  END p
END m828
MACRO m829
  SIZE 0.510 BY 0.307 ;
  PIN p
    DIRECTION INOUT ;
    USE SIGNAL ;
    PORT
      LAYER metal1 ;
      RECT 0 0 0.510 0.307 ;
    END
  END p
END m829
MACRO m830
  SIZE 0.510 BY 0.722 ;
  PIN p
    DIRECTION INOUT ;
    USE SIGNAL ;
    PORT
      LAYER metal1 ;
      RECT 0 0 0.510 0.722 ;
    END
  END p
END m830
MACRO m831
  SIZE 0.510 BY 0.345 ;
  PIN p
    DIRECTION INOUT ;
    USE SIGNAL ;
    PORT
      LAYER metal1 ;
      RECT 0 0 0.510 0.345 ;
    END
  END p
END m831
MACRO m832
  SIZE 0.510 BY 0.527 ;
  PIN p
    DIRECTION INOUT ;
    USE SIGNAL ;
    PORT
      LAYER metal1 ;
      RECT 0 0 0.510 0.527 ;
    END
  END p
END m832
MACRO m833
  SIZE 0.510 BY 1.035 ;
  PIN p
    DIRECTION INOUT ;
    USE SIGNAL ;
    PORT
      LAYER metal1 ;
      RECT 0 0 0.510 1.035 ;
    END
  END p
END m833
MACRO m834
  SIZE 0.510 BY 0.841 ;
  PIN p
    DIRECTION INOUT ;
    USE SIGNAL ;
    PORT
      LAYER metal1 ;
      RECT 0 0 0.510 0.841 ;
    END
  END p
END m834
MACRO m835
  SIZE 0.510 BY 0.540 ;
  PIN p
    DIRECTION INOUT ;
    USE SIGNAL ;
    PORT
      LAYER metal1 ;
      RECT 0 0 0.510 0.540 ;
    END
  END p
END m835
MACRO m836
  SIZE 0.510 BY 0.665 ;
  PIN p
    DIRECTION INOUT ;
    USE SIGNAL ;
    PORT
      LAYER metal1 ;
      RECT 0 0 0.510 0.665 ;
    END
  END p
END m836
MACRO m837
  SIZE 0.510 BY 0.477 ;
  PIN p
    DIRECTION INOUT ;
    USE SIGNAL ;
    PORT
      LAYER metal1 ;
      RECT 0 0 0.510 0.477 ;
    END
  END p
END m837
MACRO m838
  SIZE 0.510 BY 0.979 ;
  PIN p
    DIRECTION INOUT ;
    USE SIGNAL ;
    PORT
      LAYER metal1 ;
      RECT 0 0 0.510 0.979 ;
    END
  END p
END m838
MACRO m839
  SIZE 0.510 BY 0.527 ;
  PIN p
    DIRECTION INOUT ;
    USE SIGNAL ;
    PORT
      LAYER metal1 ;
      RECT 0 0 0.510 0.527 ;
    END
  END p
END m839
MACRO m840
  SIZE 0.510 BY 0.439 ;
  PIN p
    DIRECTION INOUT ;
    USE SIGNAL ;
    PORT
      LAYER metal1 ;
      RECT 0 0 0.510 0.439 ;
    END
  END p
END m840
MACRO m841
  SIZE 0.510 BY 0.452 ;
  PIN p
    DIRECTION INOUT ;
    USE SIGNAL ;
    PORT
      LAYER metal1 ;
      RECT 0 0 0.510 0.452 ;
    END
  END p
END m841
MACRO m842
  SIZE 0.510 BY 0.176 ;
  PIN p
    DIRECTION INOUT ;
    USE SIGNAL ;
    PORT
      LAYER metal1 ;
      RECT 0 0 0.510 0.176 ;
    END
  END p
END m842
MACRO m843
  SIZE 0.510 BY 0.515 ;
  PIN p
    DIRECTION INOUT ;
    USE SIGNAL ;
    PORT
      LAYER metal1 ;
      RECT 0 0 0.510 0.515 ;
    END
  END p
END m843
MACRO m844
  SIZE 0.510 BY 0.301 ;
  PIN p
    DIRECTION INOUT ;
    USE SIGNAL ;
    PORT
      LAYER metal1 ;
      RECT 0 0 0.510 0.301 ;
    END
  END p
END m844
MACRO m845
  SIZE 0.510 BY 0.376 ;
  PIN p
    DIRECTION INOUT ;
    USE SIGNAL ;
    PORT
      LAYER metal1 ;
      RECT 0 0 0.510 0.376 ;
    END
  END p
END m845
MACRO m846
  SIZE 0.510 BY 0.615 ;
  PIN p
    DIRECTION INOUT ;
    USE SIGNAL ;
    PORT
      LAYER metal1 ;
      RECT 0 0 0.510 0.615 ;
    END
  END p
END m846
MACRO m847
  SIZE 0.510 BY 0.471 ;
  PIN p
    DIRECTION INOUT ;
    USE SIGNAL ;
    PORT
      LAYER metal1 ;
      RECT 0 0 0.510 0.471 ;
    END
  END p
END m847
MACRO m848
  SIZE 0.510 BY 0.590 ;
  PIN p
    DIRECTION INOUT ;
    USE SIGNAL ;
    PORT
      LAYER metal1 ;
      RECT 0 0 0.510 0.590 ;
    END
  END p
END m848
MACRO m849
  SIZE 0.510 BY 0.527 ;
  PIN p
    DIRECTION INOUT ;
    USE SIGNAL ;
    PORT
      LAYER metal1 ;
      RECT 0 0 0.510 0.527 ;
    END
  END p
END m849
MACRO m850
  SIZE 0.510 BY 0.445 ;
  PIN p
    DIRECTION INOUT ;
    USE SIGNAL ;
    PORT
      LAYER metal1 ;
      RECT 0 0 0.510 0.445 ;
    END
  END p
END m850
MACRO m851
  SIZE 0.510 BY 0.515 ;
  PIN p
    DIRECTION INOUT ;
    USE SIGNAL ;
    PORT
      LAYER metal1 ;
      RECT 0 0 0.510 0.515 ;
    END
  END p
END m851
MACRO m852
  SIZE 0.510 BY 0.483 ;
  PIN p
    DIRECTION INOUT ;
    USE SIGNAL ;
    PORT
      LAYER metal1 ;
      RECT 0 0 0.510 0.483 ;
    END
  END p
END m852
MACRO m853
  SIZE 0.510 BY 0.333 ;
  PIN p
    DIRECTION INOUT ;
    USE SIGNAL ;
    PORT
      LAYER metal1 ;
      RECT 0 0 0.510 0.333 ;
    END
  END p
END m853
MACRO m854
  SIZE 0.510 BY 0.376 ;
  PIN p
    DIRECTION INOUT ;
    USE SIGNAL ;
    PORT
      LAYER metal1 ;
      RECT 0 0 0.510 0.376 ;
    END
  END p
END m854
MACRO m855
  SIZE 0.510 BY 0.546 ;
  PIN p
    DIRECTION INOUT ;
    USE SIGNAL ;
    PORT
      LAYER metal1 ;
      RECT 0 0 0.510 0.546 ;
    END
  END p
END m855
MACRO m856
  SIZE 0.510 BY 0.408 ;
  PIN p
    DIRECTION INOUT ;
    USE SIGNAL ;
    PORT
      LAYER metal1 ;
      RECT 0 0 0.510 0.408 ;
    END
  END p
END m856
MACRO m857
  SIZE 0.510 BY 1.355 ;
  PIN p
    DIRECTION INOUT ;
    USE SIGNAL ;
    PORT
      LAYER metal1 ;
      RECT 0 0 0.510 1.355 ;
    END
  END p
END m857
MACRO m858
  SIZE 0.510 BY 0.627 ;
  PIN p
    DIRECTION INOUT ;
    USE SIGNAL ;
    PORT
      LAYER metal1 ;
      RECT 0 0 0.510 0.627 ;
    END
  END p
END m858
MACRO m859
  SIZE 0.510 BY 0.703 ;
  PIN p
    DIRECTION INOUT ;
    USE SIGNAL ;
    PORT
      LAYER metal1 ;
      RECT 0 0 0.510 0.703 ;
    END
  END p
END m859
MACRO m860
  SIZE 0.510 BY 0.515 ;
  PIN p
    DIRECTION INOUT ;
    USE SIGNAL ;
    PORT
      LAYER metal1 ;
      RECT 0 0 0.510 0.515 ;
    END
  END p
END m860
MACRO m861
  SIZE 0.510 BY 0.558 ;
  PIN p
    DIRECTION INOUT ;
    USE SIGNAL ;
    PORT
      LAYER metal1 ;
      RECT 0 0 0.510 0.558 ;
    END
  END p
END m861
MACRO m862
  SIZE 0.510 BY 0.715 ;
  PIN p
    DIRECTION INOUT ;
    USE SIGNAL ;
    PORT
      LAYER metal1 ;
      RECT 0 0 0.510 0.715 ;
    END
  END p
END m862
MACRO m863
  SIZE 0.510 BY 0.169 ;
  PIN p
    DIRECTION INOUT ;
    USE SIGNAL ;
    PORT
      LAYER metal1 ;
      RECT 0 0 0.510 0.169 ;
    END
  END p
END m863
MACRO m864
  SIZE 0.510 BY 1.274 ;
  PIN p
    DIRECTION INOUT ;
    USE SIGNAL ;
    PORT
      LAYER metal1 ;
      RECT 0 0 0.510 1.274 ;
    END
  END p
END m864
MACRO m865
  SIZE 0.510 BY 0.389 ;
  PIN p
    DIRECTION INOUT ;
    USE SIGNAL ;
    PORT
      LAYER metal1 ;
      RECT 0 0 0.510 0.389 ;
    END
  END p
END m865
MACRO m866
  SIZE 0.510 BY 0.565 ;
  PIN p
    DIRECTION INOUT ;
    USE SIGNAL ;
    PORT
      LAYER metal1 ;
      RECT 0 0 0.510 0.565 ;
    END
  END p
END m866
MACRO m867
  SIZE 0.510 BY 0.445 ;
  PIN p
    DIRECTION INOUT ;
    USE SIGNAL ;
    PORT
      LAYER metal1 ;
      RECT 0 0 0.510 0.445 ;
    END
  END p
END m867
MACRO m868
  SIZE 0.510 BY 0.791 ;
  PIN p
    DIRECTION INOUT ;
    USE SIGNAL ;
    PORT
      LAYER metal1 ;
      RECT 0 0 0.510 0.791 ;
    END
  END p
END m868
MACRO m869
  SIZE 0.510 BY 1.004 ;
  PIN p
    DIRECTION INOUT ;
    USE SIGNAL ;
    PORT
      LAYER metal1 ;
      RECT 0 0 0.510 1.004 ;
    END
  END p
END m869
MACRO m870
  SIZE 0.510 BY 0.402 ;
  PIN p
    DIRECTION INOUT ;
    USE SIGNAL ;
    PORT
      LAYER metal1 ;
      RECT 0 0 0.510 0.402 ;
    END
  END p
END m870
MACRO m871
  SIZE 0.510 BY 0.427 ;
  PIN p
    DIRECTION INOUT ;
    USE SIGNAL ;
    PORT
      LAYER metal1 ;
      RECT 0 0 0.510 0.427 ;
    END
  END p
END m871
MACRO m872
  SIZE 0.510 BY 0.358 ;
  PIN p
    DIRECTION INOUT ;
    USE SIGNAL ;
    PORT
      LAYER metal1 ;
      RECT 0 0 0.510 0.358 ;
    END
  END p
END m872
MACRO m873
  SIZE 0.510 BY 0.414 ;
  PIN p
    DIRECTION INOUT ;
    USE SIGNAL ;
    PORT
      LAYER metal1 ;
      RECT 0 0 0.510 0.414 ;
    END
  END p
END m873
MACRO m874
  SIZE 0.510 BY 0.584 ;
  PIN p
    DIRECTION INOUT ;
    USE SIGNAL ;
    PORT
      LAYER metal1 ;
      RECT 0 0 0.510 0.584 ;
    END
  END p
END m874
MACRO m875
  SIZE 0.510 BY 0.571 ;
  PIN p
    DIRECTION INOUT ;
    USE SIGNAL ;
    PORT
      LAYER metal1 ;
      RECT 0 0 0.510 0.571 ;
    END
  END p
END m875
MACRO m876
  SIZE 0.510 BY 0.226 ;
  PIN p
    DIRECTION INOUT ;
    USE SIGNAL ;
    PORT
      LAYER metal1 ;
      RECT 0 0 0.510 0.226 ;
    END
  END p
END m876
MACRO m877
  SIZE 0.510 BY 0.584 ;
  PIN p
    DIRECTION INOUT ;
    USE SIGNAL ;
    PORT
      LAYER metal1 ;
      RECT 0 0 0.510 0.584 ;
    END
  END p
END m877
MACRO m878
  SIZE 0.510 BY 0.433 ;
  PIN p
    DIRECTION INOUT ;
    USE SIGNAL ;
    PORT
      LAYER metal1 ;
      RECT 0 0 0.510 0.433 ;
    END
  END p
END m878
MACRO m879
  SIZE 0.510 BY 0.364 ;
  PIN p
    DIRECTION INOUT ;
    USE SIGNAL ;
    PORT
      LAYER metal1 ;
      RECT 0 0 0.510 0.364 ;
    END
  END p
END m879
MACRO m880
  SIZE 0.510 BY 0.295 ;
  PIN p
    DIRECTION INOUT ;
    USE SIGNAL ;
    PORT
      LAYER metal1 ;
      RECT 0 0 0.510 0.295 ;
    END
  END p
END m880
MACRO m881
  SIZE 0.510 BY 1.820 ;
  PIN p
    DIRECTION INOUT ;
    USE SIGNAL ;
    PORT
      LAYER metal1 ;
      RECT 0 0 0.510 1.820 ;
    END
  END p
END m881
MACRO m882
  SIZE 0.510 BY 1.870 ;
  PIN p
    DIRECTION INOUT ;
    USE SIGNAL ;
    PORT
      LAYER metal1 ;
      RECT 0 0 0.510 1.870 ;
    END
  END p
END m882
MACRO m883
  SIZE 0.510 BY 0.339 ;
  PIN p
    DIRECTION INOUT ;
    USE SIGNAL ;
    PORT
      LAYER metal1 ;
      RECT 0 0 0.510 0.339 ;
    END
  END p
END m883
MACRO m884
  SIZE 0.510 BY 0.973 ;
  PIN p
    DIRECTION INOUT ;
    USE SIGNAL ;
    PORT
      LAYER metal1 ;
      RECT 0 0 0.510 0.973 ;
    END
  END p
END m884
MACRO m885
  SIZE 0.510 BY 0.508 ;
  PIN p
    DIRECTION INOUT ;
    USE SIGNAL ;
    PORT
      LAYER metal1 ;
      RECT 0 0 0.510 0.508 ;
    END
  END p
END m885
MACRO m886
  SIZE 0.510 BY 0.816 ;
  PIN p
    DIRECTION INOUT ;
    USE SIGNAL ;
    PORT
      LAYER metal1 ;
      RECT 0 0 0.510 0.816 ;
    END
  END p
END m886
MACRO m887
  SIZE 0.510 BY 1.004 ;
  PIN p
    DIRECTION INOUT ;
    USE SIGNAL ;
    PORT
      LAYER metal1 ;
      RECT 0 0 0.510 1.004 ;
    END
  END p
END m887
MACRO m888
  SIZE 0.510 BY 0.358 ;
  PIN p
    DIRECTION INOUT ;
    USE SIGNAL ;
    PORT
      LAYER metal1 ;
      RECT 0 0 0.510 0.358 ;
    END
  END p
END m888
MACRO m889
  SIZE 0.510 BY 0.878 ;
  PIN p
    DIRECTION INOUT ;
    USE SIGNAL ;
    PORT
      LAYER metal1 ;
      RECT 0 0 0.510 0.878 ;
    END
  END p
END m889
MACRO m890
  SIZE 0.510 BY 0.954 ;
  PIN p
    DIRECTION INOUT ;
    USE SIGNAL ;
    PORT
      LAYER metal1 ;
      RECT 0 0 0.510 0.954 ;
    END
  END p
END m890
MACRO m891
  SIZE 0.510 BY 0.634 ;
  PIN p
    DIRECTION INOUT ;
    USE SIGNAL ;
    PORT
      LAYER metal1 ;
      RECT 0 0 0.510 0.634 ;
    END
  END p
END m891
MACRO m892
  SIZE 0.510 BY 0.690 ;
  PIN p
    DIRECTION INOUT ;
    USE SIGNAL ;
    PORT
      LAYER metal1 ;
      RECT 0 0 0.510 0.690 ;
    END
  END p
END m892
MACRO m893
  SIZE 0.510 BY 0.370 ;
  PIN p
    DIRECTION INOUT ;
    USE SIGNAL ;
    PORT
      LAYER metal1 ;
      RECT 0 0 0.510 0.370 ;
    END
  END p
END m893
MACRO m894
  SIZE 0.510 BY 0.634 ;
  PIN p
    DIRECTION INOUT ;
    USE SIGNAL ;
    PORT
      LAYER metal1 ;
      RECT 0 0 0.510 0.634 ;
    END
  END p
END m894
MACRO m895
  SIZE 0.510 BY 0.690 ;
  PIN p
    DIRECTION INOUT ;
    USE SIGNAL ;
    PORT
      LAYER metal1 ;
      RECT 0 0 0.510 0.690 ;
    END
  END p
END m895
MACRO m896
  SIZE 0.510 BY 0.703 ;
  PIN p
    DIRECTION INOUT ;
    USE SIGNAL ;
    PORT
      LAYER metal1 ;
      RECT 0 0 0.510 0.703 ;
    END
  END p
END m896
MACRO m897
  SIZE 0.510 BY 0.527 ;
  PIN p
    DIRECTION INOUT ;
    USE SIGNAL ;
    PORT
      LAYER metal1 ;
      RECT 0 0 0.510 0.527 ;
    END
  END p
END m897
MACRO m898
  SIZE 0.510 BY 0.759 ;
  PIN p
    DIRECTION INOUT ;
    USE SIGNAL ;
    PORT
      LAYER metal1 ;
      RECT 0 0 0.510 0.759 ;
    END
  END p
END m898
MACRO m899
  SIZE 0.510 BY 0.439 ;
  PIN p
    DIRECTION INOUT ;
    USE SIGNAL ;
    PORT
      LAYER metal1 ;
      RECT 0 0 0.510 0.439 ;
    END
  END p
END m899
MACRO m900
  SIZE 0.510 BY 0.452 ;
  PIN p
    DIRECTION INOUT ;
    USE SIGNAL ;
    PORT
      LAYER metal1 ;
      RECT 0 0 0.510 0.452 ;
    END
  END p
END m900
MACRO m901
  SIZE 0.510 BY 0.659 ;
  PIN p
    DIRECTION INOUT ;
    USE SIGNAL ;
    PORT
      LAYER metal1 ;
      RECT 0 0 0.510 0.659 ;
    END
  END p
END m901
MACRO m902
  SIZE 0.510 BY 0.803 ;
  PIN p
    DIRECTION INOUT ;
    USE SIGNAL ;
    PORT
      LAYER metal1 ;
      RECT 0 0 0.510 0.803 ;
    END
  END p
END m902
MACRO m903
  SIZE 0.510 BY 0.659 ;
  PIN p
    DIRECTION INOUT ;
    USE SIGNAL ;
    PORT
      LAYER metal1 ;
      RECT 0 0 0.510 0.659 ;
    END
  END p
END m903
MACRO m904
  SIZE 0.510 BY 0.778 ;
  PIN p
    DIRECTION INOUT ;
    USE SIGNAL ;
    PORT
      LAYER metal1 ;
      RECT 0 0 0.510 0.778 ;
    END
  END p
END m904
MACRO m905
  SIZE 0.510 BY 0.414 ;
  PIN p
    DIRECTION INOUT ;
    USE SIGNAL ;
    PORT
      LAYER metal1 ;
      RECT 0 0 0.510 0.414 ;
    END
  END p
END m905
MACRO m906
  SIZE 0.510 BY 0.477 ;
  PIN p
    DIRECTION INOUT ;
    USE SIGNAL ;
    PORT
      LAYER metal1 ;
      RECT 0 0 0.510 0.477 ;
    END
  END p
END m906
MACRO m907
  SIZE 0.510 BY 0.684 ;
  PIN p
    DIRECTION INOUT ;
    USE SIGNAL ;
    PORT
      LAYER metal1 ;
      RECT 0 0 0.510 0.684 ;
    END
  END p
END m907
MACRO m908
  SIZE 0.510 BY 0.922 ;
  PIN p
    DIRECTION INOUT ;
    USE SIGNAL ;
    PORT
      LAYER metal1 ;
      RECT 0 0 0.510 0.922 ;
    END
  END p
END m908
MACRO m909
  SIZE 0.510 BY 0.433 ;
  PIN p
    DIRECTION INOUT ;
    USE SIGNAL ;
    PORT
      LAYER metal1 ;
      RECT 0 0 0.510 0.433 ;
    END
  END p
END m909
MACRO m910
  SIZE 0.510 BY 1.098 ;
  PIN p
    DIRECTION INOUT ;
    USE SIGNAL ;
    PORT
      LAYER metal1 ;
      RECT 0 0 0.510 1.098 ;
    END
  END p
END m910
MACRO m911
  SIZE 0.510 BY 0.339 ;
  PIN p
    DIRECTION INOUT ;
    USE SIGNAL ;
    PORT
      LAYER metal1 ;
      RECT 0 0 0.510 0.339 ;
    END
  END p
END m911
MACRO m912
  SIZE 0.510 BY 0.082 ;
  PIN p
    DIRECTION INOUT ;
    USE SIGNAL ;
    PORT
      LAYER metal1 ;
      RECT 0 0 0.510 0.082 ;
    END
  END p
END m912
MACRO m913
  SIZE 0.510 BY 1.098 ;
  PIN p
    DIRECTION INOUT ;
    USE SIGNAL ;
    PORT
      LAYER metal1 ;
      RECT 0 0 0.510 1.098 ;
    END
  END p
END m913
MACRO m914
  SIZE 0.510 BY 0.326 ;
  PIN p
    DIRECTION INOUT ;
    USE SIGNAL ;
    PORT
      LAYER metal1 ;
      RECT 0 0 0.510 0.326 ;
    END
  END p
END m914
MACRO m915
  SIZE 0.510 BY 0.521 ;
  PIN p
    DIRECTION INOUT ;
    USE SIGNAL ;
    PORT
      LAYER metal1 ;
      RECT 0 0 0.510 0.521 ;
    END
  END p
END m915
MACRO m916
  SIZE 0.510 BY 0.521 ;
  PIN p
    DIRECTION INOUT ;
    USE SIGNAL ;
    PORT
      LAYER metal1 ;
      RECT 0 0 0.510 0.521 ;
    END
  END p
END m916
MACRO m917
  SIZE 0.510 BY 0.740 ;
  PIN p
    DIRECTION INOUT ;
    USE SIGNAL ;
    PORT
      LAYER metal1 ;
      RECT 0 0 0.510 0.740 ;
    END
  END p
END m917
MACRO m918
  SIZE 0.510 BY 0.703 ;
  PIN p
    DIRECTION INOUT ;
    USE SIGNAL ;
    PORT
      LAYER metal1 ;
      RECT 0 0 0.510 0.703 ;
    END
  END p
END m918
MACRO m919
  SIZE 0.510 BY 0.558 ;
  PIN p
    DIRECTION INOUT ;
    USE SIGNAL ;
    PORT
      LAYER metal1 ;
      RECT 0 0 0.510 0.558 ;
    END
  END p
END m919
MACRO m920
  SIZE 0.510 BY 0.615 ;
  PIN p
    DIRECTION INOUT ;
    USE SIGNAL ;
    PORT
      LAYER metal1 ;
      RECT 0 0 0.510 0.615 ;
    END
  END p
END m920
MACRO m921
  SIZE 0.510 BY 0.471 ;
  PIN p
    DIRECTION INOUT ;
    USE SIGNAL ;
    PORT
      LAYER metal1 ;
      RECT 0 0 0.510 0.471 ;
    END
  END p
END m921
MACRO m922
  SIZE 0.510 BY 0.420 ;
  PIN p
    DIRECTION INOUT ;
    USE SIGNAL ;
    PORT
      LAYER metal1 ;
      RECT 0 0 0.510 0.420 ;
    END
  END p
END m922
MACRO m923
  SIZE 0.510 BY 0.816 ;
  PIN p
    DIRECTION INOUT ;
    USE SIGNAL ;
    PORT
      LAYER metal1 ;
      RECT 0 0 0.510 0.816 ;
    END
  END p
END m923
MACRO m924
  SIZE 0.510 BY 0.339 ;
  PIN p
    DIRECTION INOUT ;
    USE SIGNAL ;
    PORT
      LAYER metal1 ;
      RECT 0 0 0.510 0.339 ;
    END
  END p
END m924
MACRO m925
  SIZE 0.510 BY 0.483 ;
  PIN p
    DIRECTION INOUT ;
    USE SIGNAL ;
    PORT
      LAYER metal1 ;
      RECT 0 0 0.510 0.483 ;
    END
  END p
END m925
MACRO m926
  SIZE 0.510 BY 0.621 ;
  PIN p
    DIRECTION INOUT ;
    USE SIGNAL ;
    PORT
      LAYER metal1 ;
      RECT 0 0 0.510 0.621 ;
    END
  END p
END m926
MACRO m927
  SIZE 0.510 BY 0.540 ;
  PIN p
    DIRECTION INOUT ;
    USE SIGNAL ;
    PORT
      LAYER metal1 ;
      RECT 0 0 0.510 0.540 ;
    END
  END p
END m927
MACRO m928
  SIZE 0.510 BY 0.383 ;
  PIN p
    DIRECTION INOUT ;
    USE SIGNAL ;
    PORT
      LAYER metal1 ;
      RECT 0 0 0.510 0.383 ;
    END
  END p
END m928
MACRO m929
  SIZE 0.510 BY 0.778 ;
  PIN p
    DIRECTION INOUT ;
    USE SIGNAL ;
    PORT
      LAYER metal1 ;
      RECT 0 0 0.510 0.778 ;
    END
  END p
END m929
MACRO m930
  SIZE 0.510 BY 0.847 ;
  PIN p
    DIRECTION INOUT ;
    USE SIGNAL ;
    PORT
      LAYER metal1 ;
      RECT 0 0 0.510 0.847 ;
    END
  END p
END m930
MACRO m931
  SIZE 0.510 BY 0.264 ;
  PIN p
    DIRECTION INOUT ;
    USE SIGNAL ;
    PORT
      LAYER metal1 ;
      RECT 0 0 0.510 0.264 ;
    END
  END p
END m931
MACRO m932
  SIZE 0.510 BY 0.621 ;
  PIN p
    DIRECTION INOUT ;
    USE SIGNAL ;
    PORT
      LAYER metal1 ;
      RECT 0 0 0.510 0.621 ;
    END
  END p
END m932
MACRO m933
  SIZE 0.510 BY 0.627 ;
  PIN p
    DIRECTION INOUT ;
    USE SIGNAL ;
    PORT
      LAYER metal1 ;
      RECT 0 0 0.510 0.627 ;
    END
  END p
END m933
MACRO m934
  SIZE 0.510 BY 0.502 ;
  PIN p
    DIRECTION INOUT ;
    USE SIGNAL ;
    PORT
      LAYER metal1 ;
      RECT 0 0 0.510 0.502 ;
    END
  END p
END m934
MACRO m935
  SIZE 0.510 BY 0.427 ;
  PIN p
    DIRECTION INOUT ;
    USE SIGNAL ;
    PORT
      LAYER metal1 ;
      RECT 0 0 0.510 0.427 ;
    END
  END p
END m935
MACRO m936
  SIZE 0.510 BY 0.207 ;
  PIN p
    DIRECTION INOUT ;
    USE SIGNAL ;
    PORT
      LAYER metal1 ;
      RECT 0 0 0.510 0.207 ;
    END
  END p
END m936
MACRO m937
  SIZE 0.510 BY 0.220 ;
  PIN p
    DIRECTION INOUT ;
    USE SIGNAL ;
    PORT
      LAYER metal1 ;
      RECT 0 0 0.510 0.220 ;
    END
  END p
END m937
MACRO m938
  SIZE 0.510 BY 0.615 ;
  PIN p
    DIRECTION INOUT ;
    USE SIGNAL ;
    PORT
      LAYER metal1 ;
      RECT 0 0 0.510 0.615 ;
    END
  END p
END m938
MACRO m939
  SIZE 0.510 BY 0.828 ;
  PIN p
    DIRECTION INOUT ;
    USE SIGNAL ;
    PORT
      LAYER metal1 ;
      RECT 0 0 0.510 0.828 ;
    END
  END p
END m939
MACRO m940
  SIZE 0.510 BY 0.502 ;
  PIN p
    DIRECTION INOUT ;
    USE SIGNAL ;
    PORT
      LAYER metal1 ;
      RECT 0 0 0.510 0.502 ;
    END
  END p
END m940
MACRO m941
  SIZE 0.510 BY 0.659 ;
  PIN p
    DIRECTION INOUT ;
    USE SIGNAL ;
    PORT
      LAYER metal1 ;
      RECT 0 0 0.510 0.659 ;
    END
  END p
END m941
MACRO m942
  SIZE 0.510 BY 0.326 ;
  PIN p
    DIRECTION INOUT ;
    USE SIGNAL ;
    PORT
      LAYER metal1 ;
      RECT 0 0 0.510 0.326 ;
    END
  END p
END m942
MACRO m943
  SIZE 0.510 BY 0.609 ;
  PIN p
    DIRECTION INOUT ;
    USE SIGNAL ;
    PORT
      LAYER metal1 ;
      RECT 0 0 0.510 0.609 ;
    END
  END p
END m943
MACRO m944
  SIZE 0.510 BY 0.508 ;
  PIN p
    DIRECTION INOUT ;
    USE SIGNAL ;
    PORT
      LAYER metal1 ;
      RECT 0 0 0.510 0.508 ;
    END
  END p
END m944
MACRO m945
  SIZE 0.510 BY 0.301 ;
  PIN p
    DIRECTION INOUT ;
    USE SIGNAL ;
    PORT
      LAYER metal1 ;
      RECT 0 0 0.510 0.301 ;
    END
  END p
END m945
MACRO m946
  SIZE 0.510 BY 0.590 ;
  PIN p
    DIRECTION INOUT ;
    USE SIGNAL ;
    PORT
      LAYER metal1 ;
      RECT 0 0 0.510 0.590 ;
    END
  END p
END m946
MACRO m947
  SIZE 0.510 BY 0.389 ;
  PIN p
    DIRECTION INOUT ;
    USE SIGNAL ;
    PORT
      LAYER metal1 ;
      RECT 0 0 0.510 0.389 ;
    END
  END p
END m947
MACRO m948
  SIZE 0.510 BY 0.646 ;
  PIN p
    DIRECTION INOUT ;
    USE SIGNAL ;
    PORT
      LAYER metal1 ;
      RECT 0 0 0.510 0.646 ;
    END
  END p
END m948
MACRO m949
  SIZE 0.510 BY 0.320 ;
  PIN p
    DIRECTION INOUT ;
    USE SIGNAL ;
    PORT
      LAYER metal1 ;
      RECT 0 0 0.510 0.320 ;
    END
  END p
END m949
MACRO m950
  SIZE 0.510 BY 0.464 ;
  PIN p
    DIRECTION INOUT ;
    USE SIGNAL ;
    PORT
      LAYER metal1 ;
      RECT 0 0 0.510 0.464 ;
    END
  END p
END m950
MACRO m951
  SIZE 0.510 BY 0.973 ;
  PIN p
    DIRECTION INOUT ;
    USE SIGNAL ;
    PORT
      LAYER metal1 ;
      RECT 0 0 0.510 0.973 ;
    END
  END p
END m951
MACRO m952
  SIZE 0.510 BY 0.860 ;
  PIN p
    DIRECTION INOUT ;
    USE SIGNAL ;
    PORT
      LAYER metal1 ;
      RECT 0 0 0.510 0.860 ;
    END
  END p
END m952
MACRO m953
  SIZE 0.510 BY 1.575 ;
  PIN p
    DIRECTION INOUT ;
    USE SIGNAL ;
    PORT
      LAYER metal1 ;
      RECT 0 0 0.510 1.575 ;
    END
  END p
END m953
MACRO m954
  SIZE 0.510 BY 0.765 ;
  PIN p
    DIRECTION INOUT ;
    USE SIGNAL ;
    PORT
      LAYER metal1 ;
      RECT 0 0 0.510 0.765 ;
    END
  END p
END m954
MACRO m955
  SIZE 0.510 BY 0.753 ;
  PIN p
    DIRECTION INOUT ;
    USE SIGNAL ;
    PORT
      LAYER metal1 ;
      RECT 0 0 0.510 0.753 ;
    END
  END p
END m955
MACRO m956
  SIZE 0.510 BY 0.402 ;
  PIN p
    DIRECTION INOUT ;
    USE SIGNAL ;
    PORT
      LAYER metal1 ;
      RECT 0 0 0.510 0.402 ;
    END
  END p
END m956
MACRO m957
  SIZE 0.510 BY 0.803 ;
  PIN p
    DIRECTION INOUT ;
    USE SIGNAL ;
    PORT
      LAYER metal1 ;
      RECT 0 0 0.510 0.803 ;
    END
  END p
END m957
MACRO m958
  SIZE 0.510 BY 0.458 ;
  PIN p
    DIRECTION INOUT ;
    USE SIGNAL ;
    PORT
      LAYER metal1 ;
      RECT 0 0 0.510 0.458 ;
    END
  END p
END m958
MACRO m959
  SIZE 0.510 BY 0.445 ;
  PIN p
    DIRECTION INOUT ;
    USE SIGNAL ;
    PORT
      LAYER metal1 ;
      RECT 0 0 0.510 0.445 ;
    END
  END p
END m959
MACRO m960
  SIZE 0.510 BY 0.690 ;
  PIN p
    DIRECTION INOUT ;
    USE SIGNAL ;
    PORT
      LAYER metal1 ;
      RECT 0 0 0.510 0.690 ;
    END
  END p
END m960
MACRO m961
  SIZE 0.510 BY 0.433 ;
  PIN p
    DIRECTION INOUT ;
    USE SIGNAL ;
    PORT
      LAYER metal1 ;
      RECT 0 0 0.510 0.433 ;
    END
  END p
END m961
MACRO m962
  SIZE 0.510 BY 1.205 ;
  PIN p
    DIRECTION INOUT ;
    USE SIGNAL ;
    PORT
      LAYER metal1 ;
      RECT 0 0 0.510 1.205 ;
    END
  END p
END m962
MACRO m963
  SIZE 0.510 BY 0.684 ;
  PIN p
    DIRECTION INOUT ;
    USE SIGNAL ;
    PORT
      LAYER metal1 ;
      RECT 0 0 0.510 0.684 ;
    END
  END p
END m963
MACRO m964
  SIZE 0.510 BY 0.389 ;
  PIN p
    DIRECTION INOUT ;
    USE SIGNAL ;
    PORT
      LAYER metal1 ;
      RECT 0 0 0.510 0.389 ;
    END
  END p
END m964
MACRO m965
  SIZE 0.510 BY 0.577 ;
  PIN p
    DIRECTION INOUT ;
    USE SIGNAL ;
    PORT
      LAYER metal1 ;
      RECT 0 0 0.510 0.577 ;
    END
  END p
END m965
MACRO m966
  SIZE 0.510 BY 0.634 ;
  PIN p
    DIRECTION INOUT ;
    USE SIGNAL ;
    PORT
      LAYER metal1 ;
      RECT 0 0 0.510 0.634 ;
    END
  END p
END m966
MACRO m967
  SIZE 0.510 BY 0.659 ;
  PIN p
    DIRECTION INOUT ;
    USE SIGNAL ;
    PORT
      LAYER metal1 ;
      RECT 0 0 0.510 0.659 ;
    END
  END p
END m967
MACRO m968
  SIZE 0.510 BY 0.502 ;
  PIN p
    DIRECTION INOUT ;
    USE SIGNAL ;
    PORT
      LAYER metal1 ;
      RECT 0 0 0.510 0.502 ;
    END
  END p
END m968
MACRO m969
  SIZE 0.510 BY 0.703 ;
  PIN p
    DIRECTION INOUT ;
    USE SIGNAL ;
    PORT
      LAYER metal1 ;
      RECT 0 0 0.510 0.703 ;
    END
  END p
END m969
MACRO m970
  SIZE 0.510 BY 0.803 ;
  PIN p
    DIRECTION INOUT ;
    USE SIGNAL ;
    PORT
      LAYER metal1 ;
      RECT 0 0 0.510 0.803 ;
    END
  END p
END m970
MACRO m971
  SIZE 0.510 BY 0.653 ;
  PIN p
    DIRECTION INOUT ;
    USE SIGNAL ;
    PORT
      LAYER metal1 ;
      RECT 0 0 0.510 0.653 ;
    END
  END p
END m971
MACRO m972
  SIZE 0.510 BY 0.395 ;
  PIN p
    DIRECTION INOUT ;
    USE SIGNAL ;
    PORT
      LAYER metal1 ;
      RECT 0 0 0.510 0.395 ;
    END
  END p
END m972
MACRO m973
  SIZE 0.510 BY 0.665 ;
  PIN p
    DIRECTION INOUT ;
    USE SIGNAL ;
    PORT
      LAYER metal1 ;
      RECT 0 0 0.510 0.665 ;
    END
  END p
END m973
MACRO m974
  SIZE 0.510 BY 0.420 ;
  PIN p
    DIRECTION INOUT ;
    USE SIGNAL ;
    PORT
      LAYER metal1 ;
      RECT 0 0 0.510 0.420 ;
    END
  END p
END m974
MACRO m975
  SIZE 0.510 BY 1.023 ;
  PIN p
    DIRECTION INOUT ;
    USE SIGNAL ;
    PORT
      LAYER metal1 ;
      RECT 0 0 0.510 1.023 ;
    END
  END p
END m975
MACRO m976
  SIZE 0.510 BY 0.540 ;
  PIN p
    DIRECTION INOUT ;
    USE SIGNAL ;
    PORT
      LAYER metal1 ;
      RECT 0 0 0.510 0.540 ;
    END
  END p
END m976
MACRO m977
  SIZE 0.510 BY 0.389 ;
  PIN p
    DIRECTION INOUT ;
    USE SIGNAL ;
    PORT
      LAYER metal1 ;
      RECT 0 0 0.510 0.389 ;
    END
  END p
END m977
MACRO m978
  SIZE 0.510 BY 0.678 ;
  PIN p
    DIRECTION INOUT ;
    USE SIGNAL ;
    PORT
      LAYER metal1 ;
      RECT 0 0 0.510 0.678 ;
    END
  END p
END m978
MACRO m979
  SIZE 0.510 BY 0.558 ;
  PIN p
    DIRECTION INOUT ;
    USE SIGNAL ;
    PORT
      LAYER metal1 ;
      RECT 0 0 0.510 0.558 ;
    END
  END p
END m979
MACRO m980
  SIZE 0.510 BY 0.860 ;
  PIN p
    DIRECTION INOUT ;
    USE SIGNAL ;
    PORT
      LAYER metal1 ;
      RECT 0 0 0.510 0.860 ;
    END
  END p
END m980
MACRO m981
  SIZE 0.510 BY 0.464 ;
  PIN p
    DIRECTION INOUT ;
    USE SIGNAL ;
    PORT
      LAYER metal1 ;
      RECT 0 0 0.510 0.464 ;
    END
  END p
END m981
MACRO m982
  SIZE 0.510 BY 0.615 ;
  PIN p
    DIRECTION INOUT ;
    USE SIGNAL ;
    PORT
      LAYER metal1 ;
      RECT 0 0 0.510 0.615 ;
    END
  END p
END m982
MACRO m983
  SIZE 0.510 BY 0.571 ;
  PIN p
    DIRECTION INOUT ;
    USE SIGNAL ;
    PORT
      LAYER metal1 ;
      RECT 0 0 0.510 0.571 ;
    END
  END p
END m983
MACRO m984
  SIZE 0.510 BY 0.615 ;
  PIN p
    DIRECTION INOUT ;
    USE SIGNAL ;
    PORT
      LAYER metal1 ;
      RECT 0 0 0.510 0.615 ;
    END
  END p
END m984
MACRO m985
  SIZE 0.510 BY 0.690 ;
  PIN p
    DIRECTION INOUT ;
    USE SIGNAL ;
    PORT
      LAYER metal1 ;
      RECT 0 0 0.510 0.690 ;
    END
  END p
END m985
MACRO m986
  SIZE 0.510 BY 0.282 ;
  PIN p
    DIRECTION INOUT ;
    USE SIGNAL ;
    PORT
      LAYER metal1 ;
      RECT 0 0 0.510 0.282 ;
    END
  END p
END m986
MACRO m987
  SIZE 0.510 BY 0.678 ;
  PIN p
    DIRECTION INOUT ;
    USE SIGNAL ;
    PORT
      LAYER metal1 ;
      RECT 0 0 0.510 0.678 ;
    END
  END p
END m987
MACRO m988
  SIZE 0.510 BY 0.402 ;
  PIN p
    DIRECTION INOUT ;
    USE SIGNAL ;
    PORT
      LAYER metal1 ;
      RECT 0 0 0.510 0.402 ;
    END
  END p
END m988
MACRO m989
  SIZE 0.510 BY 0.420 ;
  PIN p
    DIRECTION INOUT ;
    USE SIGNAL ;
    PORT
      LAYER metal1 ;
      RECT 0 0 0.510 0.420 ;
    END
  END p
END m989
MACRO m990
  SIZE 0.510 BY 0.973 ;
  PIN p
    DIRECTION INOUT ;
    USE SIGNAL ;
    PORT
      LAYER metal1 ;
      RECT 0 0 0.510 0.973 ;
    END
  END p
END m990
MACRO m991
  SIZE 0.510 BY 0.477 ;
  PIN p
    DIRECTION INOUT ;
    USE SIGNAL ;
    PORT
      LAYER metal1 ;
      RECT 0 0 0.510 0.477 ;
    END
  END p
END m991
MACRO m992
  SIZE 0.510 BY 0.358 ;
  PIN p
    DIRECTION INOUT ;
    USE SIGNAL ;
    PORT
      LAYER metal1 ;
      RECT 0 0 0.510 0.358 ;
    END
  END p
END m992
MACRO m993
  SIZE 0.510 BY 0.389 ;
  PIN p
    DIRECTION INOUT ;
    USE SIGNAL ;
    PORT
      LAYER metal1 ;
      RECT 0 0 0.510 0.389 ;
    END
  END p
END m993
MACRO m994
  SIZE 0.510 BY 0.358 ;
  PIN p
    DIRECTION INOUT ;
    USE SIGNAL ;
    PORT
      LAYER metal1 ;
      RECT 0 0 0.510 0.358 ;
    END
  END p
END m994
MACRO m995
  SIZE 0.510 BY 0.565 ;
  PIN p
    DIRECTION INOUT ;
    USE SIGNAL ;
    PORT
      LAYER metal1 ;
      RECT 0 0 0.510 0.565 ;
    END
  END p
END m995
MACRO m996
  SIZE 0.510 BY 0.558 ;
  PIN p
    DIRECTION INOUT ;
    USE SIGNAL ;
    PORT
      LAYER metal1 ;
      RECT 0 0 0.510 0.558 ;
    END
  END p
END m996
MACRO m997
  SIZE 0.510 BY 0.696 ;
  PIN p
    DIRECTION INOUT ;
    USE SIGNAL ;
    PORT
      LAYER metal1 ;
      RECT 0 0 0.510 0.696 ;
    END
  END p
END m997
MACRO m998
  SIZE 0.510 BY 0.791 ;
  PIN p
    DIRECTION INOUT ;
    USE SIGNAL ;
    PORT
      LAYER metal1 ;
      RECT 0 0 0.510 0.791 ;
    END
  END p
END m998
MACRO m999
  SIZE 0.510 BY 0.860 ;
  PIN p
    DIRECTION INOUT ;
    USE SIGNAL ;
    PORT
      LAYER metal1 ;
      RECT 0 0 0.510 0.860 ;
    END
  END p
END m999
MACRO m1000
  SIZE 0.510 BY 0.791 ;
  PIN p
    DIRECTION INOUT ;
    USE SIGNAL ;
    PORT
      LAYER metal1 ;
      RECT 0 0 0.510 0.791 ;
    END
  END p
END m1000
MACRO m1001
  SIZE 0.510 BY 0.245 ;
  PIN p
    DIRECTION INOUT ;
    USE SIGNAL ;
    PORT
      LAYER metal1 ;
      RECT 0 0 0.510 0.245 ;
    END
  END p
END m1001
MACRO m1002
  SIZE 0.510 BY 0.464 ;
  PIN p
    DIRECTION INOUT ;
    USE SIGNAL ;
    PORT
      LAYER metal1 ;
      RECT 0 0 0.510 0.464 ;
    END
  END p
END m1002
MACRO m1003
  SIZE 0.510 BY 0.326 ;
  PIN p
    DIRECTION INOUT ;
    USE SIGNAL ;
    PORT
      LAYER metal1 ;
      RECT 0 0 0.510 0.326 ;
    END
  END p
END m1003
MACRO m1004
  SIZE 0.510 BY 0.540 ;
  PIN p
    DIRECTION INOUT ;
    USE SIGNAL ;
    PORT
      LAYER metal1 ;
      RECT 0 0 0.510 0.540 ;
    END
  END p
END m1004
MACRO m1005
  SIZE 0.510 BY 0.339 ;
  PIN p
    DIRECTION INOUT ;
    USE SIGNAL ;
    PORT
      LAYER metal1 ;
      RECT 0 0 0.510 0.339 ;
    END
  END p
END m1005
MACRO m1006
  SIZE 0.510 BY 0.502 ;
  PIN p
    DIRECTION INOUT ;
    USE SIGNAL ;
    PORT
      LAYER metal1 ;
      RECT 0 0 0.510 0.502 ;
    END
  END p
END m1006
MACRO m1007
  SIZE 0.510 BY 0.590 ;
  PIN p
    DIRECTION INOUT ;
    USE SIGNAL ;
    PORT
      LAYER metal1 ;
      RECT 0 0 0.510 0.590 ;
    END
  END p
END m1007
MACRO m1008
  SIZE 0.510 BY 0.941 ;
  PIN p
    DIRECTION INOUT ;
    USE SIGNAL ;
    PORT
      LAYER metal1 ;
      RECT 0 0 0.510 0.941 ;
    END
  END p
END m1008
MACRO m1009
  SIZE 0.510 BY 0.527 ;
  PIN p
    DIRECTION INOUT ;
    USE SIGNAL ;
    PORT
      LAYER metal1 ;
      RECT 0 0 0.510 0.527 ;
    END
  END p
END m1009
MACRO m1010
  SIZE 0.510 BY 0.558 ;
  PIN p
    DIRECTION INOUT ;
    USE SIGNAL ;
    PORT
      LAYER metal1 ;
      RECT 0 0 0.510 0.558 ;
    END
  END p
END m1010
MACRO m1011
  SIZE 0.510 BY 0.577 ;
  PIN p
    DIRECTION INOUT ;
    USE SIGNAL ;
    PORT
      LAYER metal1 ;
      RECT 0 0 0.510 0.577 ;
    END
  END p
END m1011
MACRO m1012
  SIZE 0.510 BY 0.571 ;
  PIN p
    DIRECTION INOUT ;
    USE SIGNAL ;
    PORT
      LAYER metal1 ;
      RECT 0 0 0.510 0.571 ;
    END
  END p
END m1012
MACRO m1013
  SIZE 0.510 BY 0.295 ;
  PIN p
    DIRECTION INOUT ;
    USE SIGNAL ;
    PORT
      LAYER metal1 ;
      RECT 0 0 0.510 0.295 ;
    END
  END p
END m1013
MACRO m1014
  SIZE 0.510 BY 0.722 ;
  PIN p
    DIRECTION INOUT ;
    USE SIGNAL ;
    PORT
      LAYER metal1 ;
      RECT 0 0 0.510 0.722 ;
    END
  END p
END m1014
MACRO m1015
  SIZE 0.510 BY 0.414 ;
  PIN p
    DIRECTION INOUT ;
    USE SIGNAL ;
    PORT
      LAYER metal1 ;
      RECT 0 0 0.510 0.414 ;
    END
  END p
END m1015
MACRO m1016
  SIZE 0.510 BY 0.577 ;
  PIN p
    DIRECTION INOUT ;
    USE SIGNAL ;
    PORT
      LAYER metal1 ;
      RECT 0 0 0.510 0.577 ;
    END
  END p
END m1016
MACRO m1017
  SIZE 0.510 BY 0.960 ;
  PIN p
    DIRECTION INOUT ;
    USE SIGNAL ;
    PORT
      LAYER metal1 ;
      RECT 0 0 0.510 0.960 ;
    END
  END p
END m1017
MACRO m1018
  SIZE 0.510 BY 0.571 ;
  PIN p
    DIRECTION INOUT ;
    USE SIGNAL ;
    PORT
      LAYER metal1 ;
      RECT 0 0 0.510 0.571 ;
    END
  END p
END m1018
MACRO m1019
  SIZE 0.510 BY 0.483 ;
  PIN p
    DIRECTION INOUT ;
    USE SIGNAL ;
    PORT
      LAYER metal1 ;
      RECT 0 0 0.510 0.483 ;
    END
  END p
END m1019
MACRO m1020
  SIZE 0.510 BY 0.609 ;
  PIN p
    DIRECTION INOUT ;
    USE SIGNAL ;
    PORT
      LAYER metal1 ;
      RECT 0 0 0.510 0.609 ;
    END
  END p
END m1020
MACRO m1021
  SIZE 0.510 BY 0.552 ;
  PIN p
    DIRECTION INOUT ;
    USE SIGNAL ;
    PORT
      LAYER metal1 ;
      RECT 0 0 0.510 0.552 ;
    END
  END p
END m1021
MACRO m1022
  SIZE 0.510 BY 0.232 ;
  PIN p
    DIRECTION INOUT ;
    USE SIGNAL ;
    PORT
      LAYER metal1 ;
      RECT 0 0 0.510 0.232 ;
    END
  END p
END m1022
MACRO m1023
  SIZE 0.510 BY 0.979 ;
  PIN p
    DIRECTION INOUT ;
    USE SIGNAL ;
    PORT
      LAYER metal1 ;
      RECT 0 0 0.510 0.979 ;
    END
  END p
END m1023
MACRO m1024
  SIZE 0.510 BY 0.590 ;
  PIN p
    DIRECTION INOUT ;
    USE SIGNAL ;
    PORT
      LAYER metal1 ;
      RECT 0 0 0.510 0.590 ;
    END
  END p
END m1024
MACRO m1025
  SIZE 0.510 BY 0.439 ;
  PIN p
    DIRECTION INOUT ;
    USE SIGNAL ;
    PORT
      LAYER metal1 ;
      RECT 0 0 0.510 0.439 ;
    END
  END p
END m1025
MACRO m1026
  SIZE 0.510 BY 0.515 ;
  PIN p
    DIRECTION INOUT ;
    USE SIGNAL ;
    PORT
      LAYER metal1 ;
      RECT 0 0 0.510 0.515 ;
    END
  END p
END m1026
MACRO m1027
  SIZE 0.510 BY 0.439 ;
  PIN p
    DIRECTION INOUT ;
    USE SIGNAL ;
    PORT
      LAYER metal1 ;
      RECT 0 0 0.510 0.439 ;
    END
  END p
END m1027
MACRO m1028
  SIZE 0.510 BY 0.452 ;
  PIN p
    DIRECTION INOUT ;
    USE SIGNAL ;
    PORT
      LAYER metal1 ;
      RECT 0 0 0.510 0.452 ;
    END
  END p
END m1028
MACRO m1029
  SIZE 0.510 BY 0.665 ;
  PIN p
    DIRECTION INOUT ;
    USE SIGNAL ;
    PORT
      LAYER metal1 ;
      RECT 0 0 0.510 0.665 ;
    END
  END p
END m1029
MACRO m1030
  SIZE 0.510 BY 0.590 ;
  PIN p
    DIRECTION INOUT ;
    USE SIGNAL ;
    PORT
      LAYER metal1 ;
      RECT 0 0 0.510 0.590 ;
    END
  END p
END m1030
MACRO m1031
  SIZE 0.510 BY 0.853 ;
  PIN p
    DIRECTION INOUT ;
    USE SIGNAL ;
    PORT
      LAYER metal1 ;
      RECT 0 0 0.510 0.853 ;
    END
  END p
END m1031
MACRO m1032
  SIZE 0.510 BY 0.489 ;
  PIN p
    DIRECTION INOUT ;
    USE SIGNAL ;
    PORT
      LAYER metal1 ;
      RECT 0 0 0.510 0.489 ;
    END
  END p
END m1032
MACRO m1033
  SIZE 0.510 BY 0.552 ;
  PIN p
    DIRECTION INOUT ;
    USE SIGNAL ;
    PORT
      LAYER metal1 ;
      RECT 0 0 0.510 0.552 ;
    END
  END p
END m1033
MACRO m1034
  SIZE 0.510 BY 0.816 ;
  PIN p
    DIRECTION INOUT ;
    USE SIGNAL ;
    PORT
      LAYER metal1 ;
      RECT 0 0 0.510 0.816 ;
    END
  END p
END m1034
MACRO m1035
  SIZE 0.510 BY 1.060 ;
  PIN p
    DIRECTION INOUT ;
    USE SIGNAL ;
    PORT
      LAYER metal1 ;
      RECT 0 0 0.510 1.060 ;
    END
  END p
END m1035
MACRO m1036
  SIZE 0.510 BY 0.264 ;
  PIN p
    DIRECTION INOUT ;
    USE SIGNAL ;
    PORT
      LAYER metal1 ;
      RECT 0 0 0.510 0.264 ;
    END
  END p
END m1036
MACRO m1037
  SIZE 0.510 BY 0.370 ;
  PIN p
    DIRECTION INOUT ;
    USE SIGNAL ;
    PORT
      LAYER metal1 ;
      RECT 0 0 0.510 0.370 ;
    END
  END p
END m1037
MACRO m1038
  SIZE 0.510 BY 0.797 ;
  PIN p
    DIRECTION INOUT ;
    USE SIGNAL ;
    PORT
      LAYER metal1 ;
      RECT 0 0 0.510 0.797 ;
    END
  END p
END m1038
MACRO m1039
  SIZE 0.510 BY 0.646 ;
  PIN p
    DIRECTION INOUT ;
    USE SIGNAL ;
    PORT
      LAYER metal1 ;
      RECT 0 0 0.510 0.646 ;
    END
  END p
END m1039
MACRO m1040
  SIZE 0.510 BY 0.458 ;
  PIN p
    DIRECTION INOUT ;
    USE SIGNAL ;
    PORT
      LAYER metal1 ;
      RECT 0 0 0.510 0.458 ;
    END
  END p
END m1040
MACRO m1041
  SIZE 0.510 BY 0.402 ;
  PIN p
    DIRECTION INOUT ;
    USE SIGNAL ;
    PORT
      LAYER metal1 ;
      RECT 0 0 0.510 0.402 ;
    END
  END p
END m1041
MACRO m1042
  SIZE 0.510 BY 1.004 ;
  PIN p
    DIRECTION INOUT ;
    USE SIGNAL ;
    PORT
      LAYER metal1 ;
      RECT 0 0 0.510 1.004 ;
    END
  END p
END m1042
MACRO m1043
  SIZE 0.510 BY 0.734 ;
  PIN p
    DIRECTION INOUT ;
    USE SIGNAL ;
    PORT
      LAYER metal1 ;
      RECT 0 0 0.510 0.734 ;
    END
  END p
END m1043
MACRO m1044
  SIZE 0.510 BY 0.709 ;
  PIN p
    DIRECTION INOUT ;
    USE SIGNAL ;
    PORT
      LAYER metal1 ;
      RECT 0 0 0.510 0.709 ;
    END
  END p
END m1044
MACRO m1045
  SIZE 0.510 BY 0.540 ;
  PIN p
    DIRECTION INOUT ;
    USE SIGNAL ;
    PORT
      LAYER metal1 ;
      RECT 0 0 0.510 0.540 ;
    END
  END p
END m1045
MACRO m1046
  SIZE 0.510 BY 0.640 ;
  PIN p
    DIRECTION INOUT ;
    USE SIGNAL ;
    PORT
      LAYER metal1 ;
      RECT 0 0 0.510 0.640 ;
    END
  END p
END m1046
MACRO m1047
  SIZE 0.510 BY 0.615 ;
  PIN p
    DIRECTION INOUT ;
    USE SIGNAL ;
    PORT
      LAYER metal1 ;
      RECT 0 0 0.510 0.615 ;
    END
  END p
END m1047
MACRO m1048
  SIZE 0.510 BY 0.979 ;
  PIN p
    DIRECTION INOUT ;
    USE SIGNAL ;
    PORT
      LAYER metal1 ;
      RECT 0 0 0.510 0.979 ;
    END
  END p
END m1048
MACRO m1049
  SIZE 0.510 BY 0.439 ;
  PIN p
    DIRECTION INOUT ;
    USE SIGNAL ;
    PORT
      LAYER metal1 ;
      RECT 0 0 0.510 0.439 ;
    END
  END p
END m1049
MACRO m1050
  SIZE 0.510 BY 0.728 ;
  PIN p
    DIRECTION INOUT ;
    USE SIGNAL ;
    PORT
      LAYER metal1 ;
      RECT 0 0 0.510 0.728 ;
    END
  END p
END m1050
MACRO m1051
  SIZE 0.510 BY 0.326 ;
  PIN p
    DIRECTION INOUT ;
    USE SIGNAL ;
    PORT
      LAYER metal1 ;
      RECT 0 0 0.510 0.326 ;
    END
  END p
END m1051
MACRO m1052
  SIZE 0.510 BY 0.885 ;
  PIN p
    DIRECTION INOUT ;
    USE SIGNAL ;
    PORT
      LAYER metal1 ;
      RECT 0 0 0.510 0.885 ;
    END
  END p
END m1052
MACRO m1053
  SIZE 0.510 BY 0.364 ;
  PIN p
    DIRECTION INOUT ;
    USE SIGNAL ;
    PORT
      LAYER metal1 ;
      RECT 0 0 0.510 0.364 ;
    END
  END p
END m1053
MACRO m1054
  SIZE 0.510 BY 0.696 ;
  PIN p
    DIRECTION INOUT ;
    USE SIGNAL ;
    PORT
      LAYER metal1 ;
      RECT 0 0 0.510 0.696 ;
    END
  END p
END m1054
MACRO m1055
  SIZE 0.510 BY 0.709 ;
  PIN p
    DIRECTION INOUT ;
    USE SIGNAL ;
    PORT
      LAYER metal1 ;
      RECT 0 0 0.510 0.709 ;
    END
  END p
END m1055
MACRO m1056
  SIZE 0.510 BY 0.590 ;
  PIN p
    DIRECTION INOUT ;
    USE SIGNAL ;
    PORT
      LAYER metal1 ;
      RECT 0 0 0.510 0.590 ;
    END
  END p
END m1056
MACRO m1057
  SIZE 0.510 BY 0.496 ;
  PIN p
    DIRECTION INOUT ;
    USE SIGNAL ;
    PORT
      LAYER metal1 ;
      RECT 0 0 0.510 0.496 ;
    END
  END p
END m1057
MACRO m1058
  SIZE 0.510 BY 0.998 ;
  PIN p
    DIRECTION INOUT ;
    USE SIGNAL ;
    PORT
      LAYER metal1 ;
      RECT 0 0 0.510 0.998 ;
    END
  END p
END m1058
MACRO m1059
  SIZE 0.510 BY 1.431 ;
  PIN p
    DIRECTION INOUT ;
    USE SIGNAL ;
    PORT
      LAYER metal1 ;
      RECT 0 0 0.510 1.431 ;
    END
  END p
END m1059
MACRO m1060
  SIZE 0.510 BY 0.301 ;
  PIN p
    DIRECTION INOUT ;
    USE SIGNAL ;
    PORT
      LAYER metal1 ;
      RECT 0 0 0.510 0.301 ;
    END
  END p
END m1060
MACRO m1061
  SIZE 0.510 BY 0.546 ;
  PIN p
    DIRECTION INOUT ;
    USE SIGNAL ;
    PORT
      LAYER metal1 ;
      RECT 0 0 0.510 0.546 ;
    END
  END p
END m1061
MACRO m1062
  SIZE 0.510 BY 0.326 ;
  PIN p
    DIRECTION INOUT ;
    USE SIGNAL ;
    PORT
      LAYER metal1 ;
      RECT 0 0 0.510 0.326 ;
    END
  END p
END m1062
MACRO m1063
  SIZE 0.510 BY 0.985 ;
  PIN p
    DIRECTION INOUT ;
    USE SIGNAL ;
    PORT
      LAYER metal1 ;
      RECT 0 0 0.510 0.985 ;
    END
  END p
END m1063
MACRO m1064
  SIZE 0.510 BY 0.715 ;
  PIN p
    DIRECTION INOUT ;
    USE SIGNAL ;
    PORT
      LAYER metal1 ;
      RECT 0 0 0.510 0.715 ;
    END
  END p
END m1064
MACRO m1065
  SIZE 0.510 BY 0.722 ;
  PIN p
    DIRECTION INOUT ;
    USE SIGNAL ;
    PORT
      LAYER metal1 ;
      RECT 0 0 0.510 0.722 ;
    END
  END p
END m1065
MACRO m1066
  SIZE 0.510 BY 0.515 ;
  PIN p
    DIRECTION INOUT ;
    USE SIGNAL ;
    PORT
      LAYER metal1 ;
      RECT 0 0 0.510 0.515 ;
    END
  END p
END m1066
MACRO m1067
  SIZE 0.510 BY 0.445 ;
  PIN p
    DIRECTION INOUT ;
    USE SIGNAL ;
    PORT
      LAYER metal1 ;
      RECT 0 0 0.510 0.445 ;
    END
  END p
END m1067
MACRO m1068
  SIZE 0.510 BY 0.207 ;
  PIN p
    DIRECTION INOUT ;
    USE SIGNAL ;
    PORT
      LAYER metal1 ;
      RECT 0 0 0.510 0.207 ;
    END
  END p
END m1068
MACRO m1069
  SIZE 0.510 BY 0.646 ;
  PIN p
    DIRECTION INOUT ;
    USE SIGNAL ;
    PORT
      LAYER metal1 ;
      RECT 0 0 0.510 0.646 ;
    END
  END p
END m1069
MACRO m1070
  SIZE 0.510 BY 0.590 ;
  PIN p
    DIRECTION INOUT ;
    USE SIGNAL ;
    PORT
      LAYER metal1 ;
      RECT 0 0 0.510 0.590 ;
    END
  END p
END m1070
MACRO m1071
  SIZE 0.510 BY 0.351 ;
  PIN p
    DIRECTION INOUT ;
    USE SIGNAL ;
    PORT
      LAYER metal1 ;
      RECT 0 0 0.510 0.351 ;
    END
  END p
END m1071
MACRO m1072
  SIZE 0.510 BY 0.389 ;
  PIN p
    DIRECTION INOUT ;
    USE SIGNAL ;
    PORT
      LAYER metal1 ;
      RECT 0 0 0.510 0.389 ;
    END
  END p
END m1072
MACRO m1073
  SIZE 0.510 BY 0.634 ;
  PIN p
    DIRECTION INOUT ;
    USE SIGNAL ;
    PORT
      LAYER metal1 ;
      RECT 0 0 0.510 0.634 ;
    END
  END p
END m1073
MACRO m1074
  SIZE 0.510 BY 0.772 ;
  PIN p
    DIRECTION INOUT ;
    USE SIGNAL ;
    PORT
      LAYER metal1 ;
      RECT 0 0 0.510 0.772 ;
    END
  END p
END m1074
MACRO m1075
  SIZE 0.510 BY 0.458 ;
  PIN p
    DIRECTION INOUT ;
    USE SIGNAL ;
    PORT
      LAYER metal1 ;
      RECT 0 0 0.510 0.458 ;
    END
  END p
END m1075
MACRO m1076
  SIZE 0.510 BY 0.464 ;
  PIN p
    DIRECTION INOUT ;
    USE SIGNAL ;
    PORT
      LAYER metal1 ;
      RECT 0 0 0.510 0.464 ;
    END
  END p
END m1076
MACRO m1077
  SIZE 0.510 BY 0.778 ;
  PIN p
    DIRECTION INOUT ;
    USE SIGNAL ;
    PORT
      LAYER metal1 ;
      RECT 0 0 0.510 0.778 ;
    END
  END p
END m1077
MACRO m1078
  SIZE 0.510 BY 0.584 ;
  PIN p
    DIRECTION INOUT ;
    USE SIGNAL ;
    PORT
      LAYER metal1 ;
      RECT 0 0 0.510 0.584 ;
    END
  END p
END m1078
MACRO m1079
  SIZE 0.510 BY 0.640 ;
  PIN p
    DIRECTION INOUT ;
    USE SIGNAL ;
    PORT
      LAYER metal1 ;
      RECT 0 0 0.510 0.640 ;
    END
  END p
END m1079
MACRO m1080
  SIZE 0.510 BY 0.609 ;
  PIN p
    DIRECTION INOUT ;
    USE SIGNAL ;
    PORT
      LAYER metal1 ;
      RECT 0 0 0.510 0.609 ;
    END
  END p
END m1080
MACRO m1081
  SIZE 0.510 BY 0.747 ;
  PIN p
    DIRECTION INOUT ;
    USE SIGNAL ;
    PORT
      LAYER metal1 ;
      RECT 0 0 0.510 0.747 ;
    END
  END p
END m1081
MACRO m1082
  SIZE 0.510 BY 0.678 ;
  PIN p
    DIRECTION INOUT ;
    USE SIGNAL ;
    PORT
      LAYER metal1 ;
      RECT 0 0 0.510 0.678 ;
    END
  END p
END m1082
MACRO m1083
  SIZE 0.510 BY 0.276 ;
  PIN p
    DIRECTION INOUT ;
    USE SIGNAL ;
    PORT
      LAYER metal1 ;
      RECT 0 0 0.510 0.276 ;
    END
  END p
END m1083
MACRO m1084
  SIZE 0.510 BY 0.320 ;
  PIN p
    DIRECTION INOUT ;
    USE SIGNAL ;
    PORT
      LAYER metal1 ;
      RECT 0 0 0.510 0.320 ;
    END
  END p
END m1084
MACRO m1085
  SIZE 0.510 BY 0.452 ;
  PIN p
    DIRECTION INOUT ;
    USE SIGNAL ;
    PORT
      LAYER metal1 ;
      RECT 0 0 0.510 0.452 ;
    END
  END p
END m1085
MACRO m1086
  SIZE 0.510 BY 0.734 ;
  PIN p
    DIRECTION INOUT ;
    USE SIGNAL ;
    PORT
      LAYER metal1 ;
      RECT 0 0 0.510 0.734 ;
    END
  END p
END m1086
MACRO m1087
  SIZE 0.510 BY 0.376 ;
  PIN p
    DIRECTION INOUT ;
    USE SIGNAL ;
    PORT
      LAYER metal1 ;
      RECT 0 0 0.510 0.376 ;
    END
  END p
END m1087
MACRO m1088
  SIZE 0.510 BY 1.035 ;
  PIN p
    DIRECTION INOUT ;
    USE SIGNAL ;
    PORT
      LAYER metal1 ;
      RECT 0 0 0.510 1.035 ;
    END
  END p
END m1088
MACRO m1089
  SIZE 0.510 BY 0.609 ;
  PIN p
    DIRECTION INOUT ;
    USE SIGNAL ;
    PORT
      LAYER metal1 ;
      RECT 0 0 0.510 0.609 ;
    END
  END p
END m1089
MACRO m1090
  SIZE 0.510 BY 0.615 ;
  PIN p
    DIRECTION INOUT ;
    USE SIGNAL ;
    PORT
      LAYER metal1 ;
      RECT 0 0 0.510 0.615 ;
    END
  END p
END m1090
MACRO m1091
  SIZE 0.510 BY 0.383 ;
  PIN p
    DIRECTION INOUT ;
    USE SIGNAL ;
    PORT
      LAYER metal1 ;
      RECT 0 0 0.510 0.383 ;
    END
  END p
END m1091
MACRO m1092
  SIZE 0.510 BY 0.433 ;
  PIN p
    DIRECTION INOUT ;
    USE SIGNAL ;
    PORT
      LAYER metal1 ;
      RECT 0 0 0.510 0.433 ;
    END
  END p
END m1092
MACRO m1093
  SIZE 0.510 BY 0.835 ;
  PIN p
    DIRECTION INOUT ;
    USE SIGNAL ;
    PORT
      LAYER metal1 ;
      RECT 0 0 0.510 0.835 ;
    END
  END p
END m1093
MACRO m1094
  SIZE 0.510 BY 0.420 ;
  PIN p
    DIRECTION INOUT ;
    USE SIGNAL ;
    PORT
      LAYER metal1 ;
      RECT 0 0 0.510 0.420 ;
    END
  END p
END m1094
MACRO m1095
  SIZE 0.510 BY 0.590 ;
  PIN p
    DIRECTION INOUT ;
    USE SIGNAL ;
    PORT
      LAYER metal1 ;
      RECT 0 0 0.510 0.590 ;
    END
  END p
END m1095
MACRO m1096
  SIZE 0.510 BY 0.370 ;
  PIN p
    DIRECTION INOUT ;
    USE SIGNAL ;
    PORT
      LAYER metal1 ;
      RECT 0 0 0.510 0.370 ;
    END
  END p
END m1096
MACRO m1097
  SIZE 0.510 BY 0.985 ;
  PIN p
    DIRECTION INOUT ;
    USE SIGNAL ;
    PORT
      LAYER metal1 ;
      RECT 0 0 0.510 0.985 ;
    END
  END p
END m1097
MACRO m1098
  SIZE 0.510 BY 0.220 ;
  PIN p
    DIRECTION INOUT ;
    USE SIGNAL ;
    PORT
      LAYER metal1 ;
      RECT 0 0 0.510 0.220 ;
    END
  END p
END m1098
MACRO m1099
  SIZE 0.510 BY 0.326 ;
  PIN p
    DIRECTION INOUT ;
    USE SIGNAL ;
    PORT
      LAYER metal1 ;
      RECT 0 0 0.510 0.326 ;
    END
  END p
END m1099
MACRO m1100
  SIZE 0.510 BY 0.596 ;
  PIN p
    DIRECTION INOUT ;
    USE SIGNAL ;
    PORT
      LAYER metal1 ;
      RECT 0 0 0.510 0.596 ;
    END
  END p
END m1100
MACRO m1101
  SIZE 0.510 BY 0.671 ;
  PIN p
    DIRECTION INOUT ;
    USE SIGNAL ;
    PORT
      LAYER metal1 ;
      RECT 0 0 0.510 0.671 ;
    END
  END p
END m1101
MACRO m1102
  SIZE 0.510 BY 0.376 ;
  PIN p
    DIRECTION INOUT ;
    USE SIGNAL ;
    PORT
      LAYER metal1 ;
      RECT 0 0 0.510 0.376 ;
    END
  END p
END m1102
MACRO m1103
  SIZE 0.510 BY 0.408 ;
  PIN p
    DIRECTION INOUT ;
    USE SIGNAL ;
    PORT
      LAYER metal1 ;
      RECT 0 0 0.510 0.408 ;
    END
  END p
END m1103
MACRO m1104
  SIZE 0.510 BY 0.540 ;
  PIN p
    DIRECTION INOUT ;
    USE SIGNAL ;
    PORT
      LAYER metal1 ;
      RECT 0 0 0.510 0.540 ;
    END
  END p
END m1104
MACRO m1105
  SIZE 0.510 BY 0.282 ;
  PIN p
    DIRECTION INOUT ;
    USE SIGNAL ;
    PORT
      LAYER metal1 ;
      RECT 0 0 0.510 0.282 ;
    END
  END p
END m1105
MACRO m1106
  SIZE 0.510 BY 0.703 ;
  PIN p
    DIRECTION INOUT ;
    USE SIGNAL ;
    PORT
      LAYER metal1 ;
      RECT 0 0 0.510 0.703 ;
    END
  END p
END m1106
MACRO m1107
  SIZE 0.510 BY 0.577 ;
  PIN p
    DIRECTION INOUT ;
    USE SIGNAL ;
    PORT
      LAYER metal1 ;
      RECT 0 0 0.510 0.577 ;
    END
  END p
END m1107
MACRO m1108
  SIZE 0.510 BY 0.326 ;
  PIN p
    DIRECTION INOUT ;
    USE SIGNAL ;
    PORT
      LAYER metal1 ;
      RECT 0 0 0.510 0.326 ;
    END
  END p
END m1108
MACRO m1109
  SIZE 0.510 BY 0.489 ;
  PIN p
    DIRECTION INOUT ;
    USE SIGNAL ;
    PORT
      LAYER metal1 ;
      RECT 0 0 0.510 0.489 ;
    END
  END p
END m1109
MACRO m1110
  SIZE 0.510 BY 0.847 ;
  PIN p
    DIRECTION INOUT ;
    USE SIGNAL ;
    PORT
      LAYER metal1 ;
      RECT 0 0 0.510 0.847 ;
    END
  END p
END m1110
MACRO m1111
  SIZE 0.510 BY 0.019 ;
  PIN p
    DIRECTION INOUT ;
    USE SIGNAL ;
    PORT
      LAYER metal1 ;
      RECT 0 0 0.510 0.019 ;
    END
  END p
END m1111
MACRO m1112
  SIZE 0.510 BY 0.013 ;
  PIN p
    DIRECTION INOUT ;
    USE SIGNAL ;
    PORT
      LAYER metal1 ;
      RECT 0 0 0.510 0.013 ;
    END
  END p
END m1112
MACRO m1113
  SIZE 0.510 BY 0.013 ;
  PIN p
    DIRECTION INOUT ;
    USE SIGNAL ;
    PORT
      LAYER metal1 ;
      RECT 0 0 0.510 0.013 ;
    END
  END p
END m1113
MACRO m1114
  SIZE 0.510 BY 0.013 ;
  PIN p
    DIRECTION INOUT ;
    USE SIGNAL ;
    PORT
      LAYER metal1 ;
      RECT 0 0 0.510 0.013 ;
    END
  END p
END m1114
MACRO m1115
  SIZE 0.510 BY 0.025 ;
  PIN p
    DIRECTION INOUT ;
    USE SIGNAL ;
    PORT
      LAYER metal1 ;
      RECT 0 0 0.510 0.025 ;
    END
  END p
END m1115
MACRO m1116
  SIZE 0.510 BY 0.056 ;
  PIN p
    DIRECTION INOUT ;
    USE SIGNAL ;
    PORT
      LAYER metal1 ;
      RECT 0 0 0.510 0.056 ;
    END
  END p
END m1116
MACRO m1117
  SIZE 0.510 BY 0.025 ;
  PIN p
    DIRECTION INOUT ;
    USE SIGNAL ;
    PORT
      LAYER metal1 ;
      RECT 0 0 0.510 0.025 ;
    END
  END p
END m1117
MACRO m1118
  SIZE 0.510 BY 0.013 ;
  PIN p
    DIRECTION INOUT ;
    USE SIGNAL ;
    PORT
      LAYER metal1 ;
      RECT 0 0 0.510 0.013 ;
    END
  END p
END m1118
MACRO m1119
  SIZE 0.510 BY 0.013 ;
  PIN p
    DIRECTION INOUT ;
    USE SIGNAL ;
    PORT
      LAYER metal1 ;
      RECT 0 0 0.510 0.013 ;
    END
  END p
END m1119
MACRO m1120
  SIZE 0.510 BY 0.075 ;
  PIN p
    DIRECTION INOUT ;
    USE SIGNAL ;
    PORT
      LAYER metal1 ;
      RECT 0 0 0.510 0.075 ;
    END
  END p
END m1120
MACRO m1121
  SIZE 0.510 BY 0.013 ;
  PIN p
    DIRECTION INOUT ;
    USE SIGNAL ;
    PORT
      LAYER metal1 ;
      RECT 0 0 0.510 0.013 ;
    END
  END p
END m1121
MACRO m1122
  SIZE 0.510 BY 0.069 ;
  PIN p
    DIRECTION INOUT ;
    USE SIGNAL ;
    PORT
      LAYER metal1 ;
      RECT 0 0 0.510 0.069 ;
    END
  END p
END m1122
MACRO m1123
  SIZE 0.510 BY 0.013 ;
  PIN p
    DIRECTION INOUT ;
    USE SIGNAL ;
    PORT
      LAYER metal1 ;
      RECT 0 0 0.510 0.013 ;
    END
  END p
END m1123
MACRO m1124
  SIZE 0.510 BY 0.056 ;
  PIN p
    DIRECTION INOUT ;
    USE SIGNAL ;
    PORT
      LAYER metal1 ;
      RECT 0 0 0.510 0.056 ;
    END
  END p
END m1124
MACRO m1125
  SIZE 0.510 BY 0.006 ;
  PIN p
    DIRECTION INOUT ;
    USE SIGNAL ;
    PORT
      LAYER metal1 ;
      RECT 0 0 0.510 0.006 ;
    END
  END p
END m1125
MACRO m1126
  SIZE 0.510 BY 0.013 ;
  PIN p
    DIRECTION INOUT ;
    USE SIGNAL ;
    PORT
      LAYER metal1 ;
      RECT 0 0 0.510 0.013 ;
    END
  END p
END m1126
MACRO m1127
  SIZE 0.510 BY 0.088 ;
  PIN p
    DIRECTION INOUT ;
    USE SIGNAL ;
    PORT
      LAYER metal1 ;
      RECT 0 0 0.510 0.088 ;
    END
  END p
END m1127
MACRO m1128
  SIZE 0.510 BY 0.038 ;
  PIN p
    DIRECTION INOUT ;
    USE SIGNAL ;
    PORT
      LAYER metal1 ;
      RECT 0 0 0.510 0.038 ;
    END
  END p
END m1128
MACRO m1129
  SIZE 0.510 BY 0.100 ;
  PIN p
    DIRECTION INOUT ;
    USE SIGNAL ;
    PORT
      LAYER metal1 ;
      RECT 0 0 0.510 0.100 ;
    END
  END p
END m1129
MACRO m1130
  SIZE 0.510 BY 0.100 ;
  PIN p
    DIRECTION INOUT ;
    USE SIGNAL ;
    PORT
      LAYER metal1 ;
      RECT 0 0 0.510 0.100 ;
    END
  END p
END m1130
MACRO m1131
  SIZE 0.510 BY 0.251 ;
  PIN p
    DIRECTION INOUT ;
    USE SIGNAL ;
    PORT
      LAYER metal1 ;
      RECT 0 0 0.510 0.251 ;
    END
  END p
END m1131
MACRO m1132
  SIZE 0.510 BY 0.044 ;
  PIN p
    DIRECTION INOUT ;
    USE SIGNAL ;
    PORT
      LAYER metal1 ;
      RECT 0 0 0.510 0.044 ;
    END
  END p
END m1132
MACRO m1133
  SIZE 0.510 BY 0.019 ;
  PIN p
    DIRECTION INOUT ;
    USE SIGNAL ;
    PORT
      LAYER metal1 ;
      RECT 0 0 0.510 0.019 ;
    END
  END p
END m1133
MACRO m1134
  SIZE 0.510 BY 0.038 ;
  PIN p
    DIRECTION INOUT ;
    USE SIGNAL ;
    PORT
      LAYER metal1 ;
      RECT 0 0 0.510 0.038 ;
    END
  END p
END m1134
MACRO m1135
  SIZE 0.510 BY 0.019 ;
  PIN p
    DIRECTION INOUT ;
    USE SIGNAL ;
    PORT
      LAYER metal1 ;
      RECT 0 0 0.510 0.019 ;
    END
  END p
END m1135
MACRO m1136
  SIZE 0.510 BY 0.038 ;
  PIN p
    DIRECTION INOUT ;
    USE SIGNAL ;
    PORT
      LAYER metal1 ;
      RECT 0 0 0.510 0.038 ;
    END
  END p
END m1136
MACRO m1137
  SIZE 0.510 BY 0.019 ;
  PIN p
    DIRECTION INOUT ;
    USE SIGNAL ;
    PORT
      LAYER metal1 ;
      RECT 0 0 0.510 0.019 ;
    END
  END p
END m1137
MACRO m1138
  SIZE 0.510 BY 0.138 ;
  PIN p
    DIRECTION INOUT ;
    USE SIGNAL ;
    PORT
      LAYER metal1 ;
      RECT 0 0 0.510 0.138 ;
    END
  END p
END m1138
MACRO m1139
  SIZE 0.510 BY 0.201 ;
  PIN p
    DIRECTION INOUT ;
    USE SIGNAL ;
    PORT
      LAYER metal1 ;
      RECT 0 0 0.510 0.201 ;
    END
  END p
END m1139
MACRO dummy
  SIZE 0.1 1.0 ;
  PIN p
    DIRECTION INOUT ;
    PORT
      LAYER metal1 ;
      RECT 0 0 0.1 1.0 ;
    END
  END p
END dummy
END LIBRARY
